VERSION 5.8 ;
BUSBITCHARS "[]" ;
DIVIDERCHAR "/" ;
UNITS
    DATABASE MICRONS 1000 ;
END UNITS

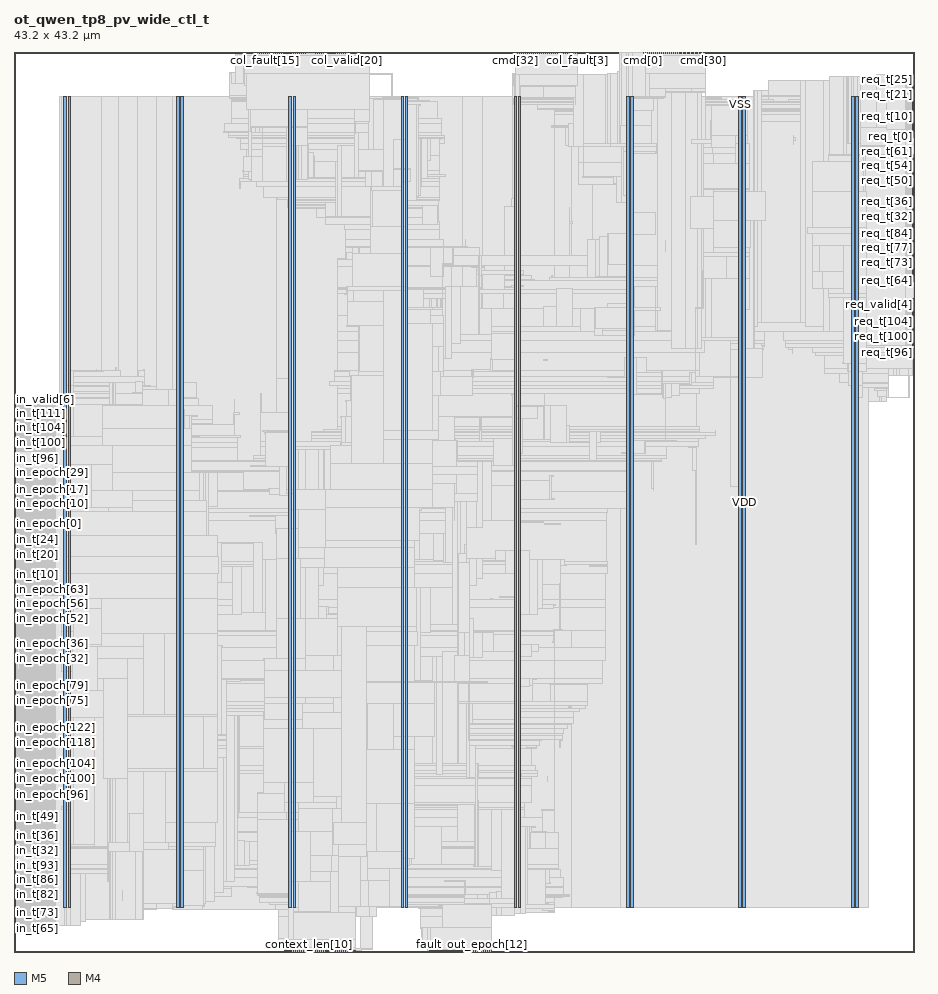
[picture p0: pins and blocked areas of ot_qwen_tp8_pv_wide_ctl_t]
MACRO ot_qwen_tp8_pv_wide_ctl_t
  FOREIGN ot_qwen_tp8_pv_wide_ctl_t 0 0 ;
  CLASS BLOCK ;
  SIZE 43.2 BY 43.2 ;
  PIN busy
    DIRECTION OUTPUT ;
    USE SIGNAL ;
    PORT
      LAYER M5 ;
        RECT  13.008 0 13.032 0.084 ;
    END
  END busy
  PIN clk
    DIRECTION INPUT ;
    USE SIGNAL ;
    PORT
      LAYER M5 ;
        RECT  13.104 0 13.128 0.084 ;
    END
  END clk
  PIN cmd[0]
    DIRECTION OUTPUT ;
    USE SIGNAL ;
    PORT
      LAYER M5 ;
        RECT  30.192 43.116 30.216 43.2 ;
    END
  END cmd[0]
  PIN cmd[10]
    DIRECTION OUTPUT ;
    USE SIGNAL ;
    PORT
      LAYER M5 ;
        RECT  31.152 43.116 31.176 43.2 ;
    END
  END cmd[10]
  PIN cmd[11]
    DIRECTION OUTPUT ;
    USE SIGNAL ;
    PORT
      LAYER M5 ;
        RECT  31.248 43.116 31.272 43.2 ;
    END
  END cmd[11]
  PIN cmd[12]
    DIRECTION OUTPUT ;
    USE SIGNAL ;
    PORT
      LAYER M5 ;
        RECT  31.344 43.116 31.368 43.2 ;
    END
  END cmd[12]
  PIN cmd[13]
    DIRECTION OUTPUT ;
    USE SIGNAL ;
    PORT
      LAYER M5 ;
        RECT  31.44 43.116 31.464 43.2 ;
    END
  END cmd[13]
  PIN cmd[14]
    DIRECTION OUTPUT ;
    USE SIGNAL ;
    PORT
      LAYER M5 ;
        RECT  31.536 43.116 31.56 43.2 ;
    END
  END cmd[14]
  PIN cmd[15]
    DIRECTION OUTPUT ;
    USE SIGNAL ;
    PORT
      LAYER M5 ;
        RECT  31.632 43.116 31.656 43.2 ;
    END
  END cmd[15]
  PIN cmd[16]
    DIRECTION OUTPUT ;
    USE SIGNAL ;
    PORT
      LAYER M5 ;
        RECT  31.728 43.116 31.752 43.2 ;
    END
  END cmd[16]
  PIN cmd[17]
    DIRECTION OUTPUT ;
    USE SIGNAL ;
    PORT
      LAYER M5 ;
        RECT  31.824 43.116 31.848 43.2 ;
    END
  END cmd[17]
  PIN cmd[18]
    DIRECTION OUTPUT ;
    USE SIGNAL ;
    PORT
      LAYER M5 ;
        RECT  31.92 43.116 31.944 43.2 ;
    END
  END cmd[18]
  PIN cmd[19]
    DIRECTION OUTPUT ;
    USE SIGNAL ;
    PORT
      LAYER M5 ;
        RECT  32.016 43.116 32.04 43.2 ;
    END
  END cmd[19]
  PIN cmd[1]
    DIRECTION OUTPUT ;
    USE SIGNAL ;
    PORT
      LAYER M5 ;
        RECT  30.288 43.116 30.312 43.2 ;
    END
  END cmd[1]
  PIN cmd[20]
    DIRECTION OUTPUT ;
    USE SIGNAL ;
    PORT
      LAYER M5 ;
        RECT  32.112 43.116 32.136 43.2 ;
    END
  END cmd[20]
  PIN cmd[21]
    DIRECTION OUTPUT ;
    USE SIGNAL ;
    PORT
      LAYER M5 ;
        RECT  32.208 43.116 32.232 43.2 ;
    END
  END cmd[21]
  PIN cmd[22]
    DIRECTION OUTPUT ;
    USE SIGNAL ;
    PORT
      LAYER M5 ;
        RECT  32.304 43.116 32.328 43.2 ;
    END
  END cmd[22]
  PIN cmd[23]
    DIRECTION OUTPUT ;
    USE SIGNAL ;
    PORT
      LAYER M5 ;
        RECT  32.4 43.116 32.424 43.2 ;
    END
  END cmd[23]
  PIN cmd[24]
    DIRECTION OUTPUT ;
    USE SIGNAL ;
    PORT
      LAYER M5 ;
        RECT  32.496 43.116 32.52 43.2 ;
    END
  END cmd[24]
  PIN cmd[25]
    DIRECTION OUTPUT ;
    USE SIGNAL ;
    PORT
      LAYER M5 ;
        RECT  32.592 43.116 32.616 43.2 ;
    END
  END cmd[25]
  PIN cmd[26]
    DIRECTION OUTPUT ;
    USE SIGNAL ;
    PORT
      LAYER M5 ;
        RECT  32.688 43.116 32.712 43.2 ;
    END
  END cmd[26]
  PIN cmd[27]
    DIRECTION OUTPUT ;
    USE SIGNAL ;
    PORT
      LAYER M5 ;
        RECT  32.784 43.116 32.808 43.2 ;
    END
  END cmd[27]
  PIN cmd[28]
    DIRECTION OUTPUT ;
    USE SIGNAL ;
    PORT
      LAYER M5 ;
        RECT  32.88 43.116 32.904 43.2 ;
    END
  END cmd[28]
  PIN cmd[29]
    DIRECTION OUTPUT ;
    USE SIGNAL ;
    PORT
      LAYER M5 ;
        RECT  32.976 43.116 33 43.2 ;
    END
  END cmd[29]
  PIN cmd[2]
    DIRECTION OUTPUT ;
    USE SIGNAL ;
    PORT
      LAYER M5 ;
        RECT  30.384 43.116 30.408 43.2 ;
    END
  END cmd[2]
  PIN cmd[30]
    DIRECTION OUTPUT ;
    USE SIGNAL ;
    PORT
      LAYER M5 ;
        RECT  33.072 43.116 33.096 43.2 ;
    END
  END cmd[30]
  PIN cmd[31]
    DIRECTION OUTPUT ;
    USE SIGNAL ;
    PORT
      LAYER M5 ;
        RECT  33.168 43.116 33.192 43.2 ;
    END
  END cmd[31]
  PIN cmd[32]
    DIRECTION OUTPUT ;
    USE SIGNAL ;
    PORT
      LAYER M5 ;
        RECT  24.048 43.116 24.072 43.2 ;
    END
  END cmd[32]
  PIN cmd[33]
    DIRECTION OUTPUT ;
    USE SIGNAL ;
    PORT
      LAYER M5 ;
        RECT  24.144 43.116 24.168 43.2 ;
    END
  END cmd[33]
  PIN cmd[34]
    DIRECTION OUTPUT ;
    USE SIGNAL ;
    PORT
      LAYER M5 ;
        RECT  24.24 43.116 24.264 43.2 ;
    END
  END cmd[34]
  PIN cmd[35]
    DIRECTION OUTPUT ;
    USE SIGNAL ;
    PORT
      LAYER M5 ;
        RECT  24.336 43.116 24.36 43.2 ;
    END
  END cmd[35]
  PIN cmd[36]
    DIRECTION OUTPUT ;
    USE SIGNAL ;
    PORT
      LAYER M5 ;
        RECT  24.432 43.116 24.456 43.2 ;
    END
  END cmd[36]
  PIN cmd[37]
    DIRECTION OUTPUT ;
    USE SIGNAL ;
    PORT
      LAYER M5 ;
        RECT  24.528 43.116 24.552 43.2 ;
    END
  END cmd[37]
  PIN cmd[38]
    DIRECTION OUTPUT ;
    USE SIGNAL ;
    PORT
      LAYER M5 ;
        RECT  24.624 43.116 24.648 43.2 ;
    END
  END cmd[38]
  PIN cmd[39]
    DIRECTION OUTPUT ;
    USE SIGNAL ;
    PORT
      LAYER M5 ;
        RECT  24.72 43.116 24.744 43.2 ;
    END
  END cmd[39]
  PIN cmd[3]
    DIRECTION OUTPUT ;
    USE SIGNAL ;
    PORT
      LAYER M5 ;
        RECT  30.48 43.116 30.504 43.2 ;
    END
  END cmd[3]
  PIN cmd[40]
    DIRECTION OUTPUT ;
    USE SIGNAL ;
    PORT
      LAYER M5 ;
        RECT  24.816 43.116 24.84 43.2 ;
    END
  END cmd[40]
  PIN cmd[41]
    DIRECTION OUTPUT ;
    USE SIGNAL ;
    PORT
      LAYER M5 ;
        RECT  24.912 43.116 24.936 43.2 ;
    END
  END cmd[41]
  PIN cmd[42]
    DIRECTION OUTPUT ;
    USE SIGNAL ;
    PORT
      LAYER M5 ;
        RECT  25.008 43.116 25.032 43.2 ;
    END
  END cmd[42]
  PIN cmd[43]
    DIRECTION OUTPUT ;
    USE SIGNAL ;
    PORT
      LAYER M5 ;
        RECT  25.104 43.116 25.128 43.2 ;
    END
  END cmd[43]
  PIN cmd[44]
    DIRECTION OUTPUT ;
    USE SIGNAL ;
    PORT
      LAYER M5 ;
        RECT  25.2 43.116 25.224 43.2 ;
    END
  END cmd[44]
  PIN cmd[45]
    DIRECTION OUTPUT ;
    USE SIGNAL ;
    PORT
      LAYER M5 ;
        RECT  25.296 43.116 25.32 43.2 ;
    END
  END cmd[45]
  PIN cmd[46]
    DIRECTION OUTPUT ;
    USE SIGNAL ;
    PORT
      LAYER M5 ;
        RECT  25.392 43.116 25.416 43.2 ;
    END
  END cmd[46]
  PIN cmd[47]
    DIRECTION OUTPUT ;
    USE SIGNAL ;
    PORT
      LAYER M5 ;
        RECT  25.488 43.116 25.512 43.2 ;
    END
  END cmd[47]
  PIN cmd[48]
    DIRECTION OUTPUT ;
    USE SIGNAL ;
    PORT
      LAYER M5 ;
        RECT  25.584 43.116 25.608 43.2 ;
    END
  END cmd[48]
  PIN cmd[49]
    DIRECTION OUTPUT ;
    USE SIGNAL ;
    PORT
      LAYER M5 ;
        RECT  25.68 43.116 25.704 43.2 ;
    END
  END cmd[49]
  PIN cmd[4]
    DIRECTION OUTPUT ;
    USE SIGNAL ;
    PORT
      LAYER M5 ;
        RECT  30.576 43.116 30.6 43.2 ;
    END
  END cmd[4]
  PIN cmd[50]
    DIRECTION OUTPUT ;
    USE SIGNAL ;
    PORT
      LAYER M5 ;
        RECT  25.776 43.116 25.8 43.2 ;
    END
  END cmd[50]
  PIN cmd[51]
    DIRECTION OUTPUT ;
    USE SIGNAL ;
    PORT
      LAYER M5 ;
        RECT  25.872 43.116 25.896 43.2 ;
    END
  END cmd[51]
  PIN cmd[52]
    DIRECTION OUTPUT ;
    USE SIGNAL ;
    PORT
      LAYER M5 ;
        RECT  25.968 43.116 25.992 43.2 ;
    END
  END cmd[52]
  PIN cmd[53]
    DIRECTION OUTPUT ;
    USE SIGNAL ;
    PORT
      LAYER M5 ;
        RECT  26.064 43.116 26.088 43.2 ;
    END
  END cmd[53]
  PIN cmd[54]
    DIRECTION OUTPUT ;
    USE SIGNAL ;
    PORT
      LAYER M5 ;
        RECT  26.16 43.116 26.184 43.2 ;
    END
  END cmd[54]
  PIN cmd[55]
    DIRECTION OUTPUT ;
    USE SIGNAL ;
    PORT
      LAYER M5 ;
        RECT  26.256 43.116 26.28 43.2 ;
    END
  END cmd[55]
  PIN cmd[56]
    DIRECTION OUTPUT ;
    USE SIGNAL ;
    PORT
      LAYER M5 ;
        RECT  26.352 43.116 26.376 43.2 ;
    END
  END cmd[56]
  PIN cmd[57]
    DIRECTION OUTPUT ;
    USE SIGNAL ;
    PORT
      LAYER M5 ;
        RECT  26.448 43.116 26.472 43.2 ;
    END
  END cmd[57]
  PIN cmd[58]
    DIRECTION OUTPUT ;
    USE SIGNAL ;
    PORT
      LAYER M5 ;
        RECT  26.544 43.116 26.568 43.2 ;
    END
  END cmd[58]
  PIN cmd[59]
    DIRECTION OUTPUT ;
    USE SIGNAL ;
    PORT
      LAYER M5 ;
        RECT  26.64 43.116 26.664 43.2 ;
    END
  END cmd[59]
  PIN cmd[5]
    DIRECTION OUTPUT ;
    USE SIGNAL ;
    PORT
      LAYER M5 ;
        RECT  30.672 43.116 30.696 43.2 ;
    END
  END cmd[5]
  PIN cmd[6]
    DIRECTION OUTPUT ;
    USE SIGNAL ;
    PORT
      LAYER M5 ;
        RECT  30.768 43.116 30.792 43.2 ;
    END
  END cmd[6]
  PIN cmd[7]
    DIRECTION OUTPUT ;
    USE SIGNAL ;
    PORT
      LAYER M5 ;
        RECT  30.864 43.116 30.888 43.2 ;
    END
  END cmd[7]
  PIN cmd[8]
    DIRECTION OUTPUT ;
    USE SIGNAL ;
    PORT
      LAYER M5 ;
        RECT  30.96 43.116 30.984 43.2 ;
    END
  END cmd[8]
  PIN cmd[9]
    DIRECTION OUTPUT ;
    USE SIGNAL ;
    PORT
      LAYER M5 ;
        RECT  31.056 43.116 31.08 43.2 ;
    END
  END cmd[9]
  PIN col_fault[0]
    DIRECTION INPUT ;
    USE SIGNAL ;
    PORT
      LAYER M5 ;
        RECT  26.736 43.116 26.76 43.2 ;
    END
  END col_fault[0]
  PIN col_fault[10]
    DIRECTION INPUT ;
    USE SIGNAL ;
    PORT
      LAYER M5 ;
        RECT  11.568 43.116 11.592 43.2 ;
    END
  END col_fault[10]
  PIN col_fault[11]
    DIRECTION INPUT ;
    USE SIGNAL ;
    PORT
      LAYER M5 ;
        RECT  11.664 43.116 11.688 43.2 ;
    END
  END col_fault[11]
  PIN col_fault[12]
    DIRECTION INPUT ;
    USE SIGNAL ;
    PORT
      LAYER M5 ;
        RECT  11.76 43.116 11.784 43.2 ;
    END
  END col_fault[12]
  PIN col_fault[13]
    DIRECTION INPUT ;
    USE SIGNAL ;
    PORT
      LAYER M5 ;
        RECT  11.856 43.116 11.88 43.2 ;
    END
  END col_fault[13]
  PIN col_fault[14]
    DIRECTION INPUT ;
    USE SIGNAL ;
    PORT
      LAYER M5 ;
        RECT  11.952 43.116 11.976 43.2 ;
    END
  END col_fault[14]
  PIN col_fault[15]
    DIRECTION INPUT ;
    USE SIGNAL ;
    PORT
      LAYER M5 ;
        RECT  12.048 43.116 12.072 43.2 ;
    END
  END col_fault[15]
  PIN col_fault[16]
    DIRECTION INPUT ;
    USE SIGNAL ;
    PORT
      LAYER M5 ;
        RECT  12.144 43.116 12.168 43.2 ;
    END
  END col_fault[16]
  PIN col_fault[17]
    DIRECTION INPUT ;
    USE SIGNAL ;
    PORT
      LAYER M5 ;
        RECT  12.24 43.116 12.264 43.2 ;
    END
  END col_fault[17]
  PIN col_fault[18]
    DIRECTION INPUT ;
    USE SIGNAL ;
    PORT
      LAYER M5 ;
        RECT  12.336 43.116 12.36 43.2 ;
    END
  END col_fault[18]
  PIN col_fault[19]
    DIRECTION INPUT ;
    USE SIGNAL ;
    PORT
      LAYER M5 ;
        RECT  12.432 43.116 12.456 43.2 ;
    END
  END col_fault[19]
  PIN col_fault[1]
    DIRECTION INPUT ;
    USE SIGNAL ;
    PORT
      LAYER M5 ;
        RECT  26.832 43.116 26.856 43.2 ;
    END
  END col_fault[1]
  PIN col_fault[20]
    DIRECTION INPUT ;
    USE SIGNAL ;
    PORT
      LAYER M5 ;
        RECT  12.528 43.116 12.552 43.2 ;
    END
  END col_fault[20]
  PIN col_fault[21]
    DIRECTION INPUT ;
    USE SIGNAL ;
    PORT
      LAYER M5 ;
        RECT  12.624 43.116 12.648 43.2 ;
    END
  END col_fault[21]
  PIN col_fault[22]
    DIRECTION INPUT ;
    USE SIGNAL ;
    PORT
      LAYER M5 ;
        RECT  12.72 43.116 12.744 43.2 ;
    END
  END col_fault[22]
  PIN col_fault[23]
    DIRECTION INPUT ;
    USE SIGNAL ;
    PORT
      LAYER M5 ;
        RECT  12.816 43.116 12.84 43.2 ;
    END
  END col_fault[23]
  PIN col_fault[24]
    DIRECTION INPUT ;
    USE SIGNAL ;
    PORT
      LAYER M5 ;
        RECT  12.912 43.116 12.936 43.2 ;
    END
  END col_fault[24]
  PIN col_fault[25]
    DIRECTION INPUT ;
    USE SIGNAL ;
    PORT
      LAYER M5 ;
        RECT  13.008 43.116 13.032 43.2 ;
    END
  END col_fault[25]
  PIN col_fault[26]
    DIRECTION INPUT ;
    USE SIGNAL ;
    PORT
      LAYER M5 ;
        RECT  13.104 43.116 13.128 43.2 ;
    END
  END col_fault[26]
  PIN col_fault[27]
    DIRECTION INPUT ;
    USE SIGNAL ;
    PORT
      LAYER M5 ;
        RECT  13.2 43.116 13.224 43.2 ;
    END
  END col_fault[27]
  PIN col_fault[28]
    DIRECTION INPUT ;
    USE SIGNAL ;
    PORT
      LAYER M5 ;
        RECT  13.296 43.116 13.32 43.2 ;
    END
  END col_fault[28]
  PIN col_fault[29]
    DIRECTION INPUT ;
    USE SIGNAL ;
    PORT
      LAYER M5 ;
        RECT  13.392 43.116 13.416 43.2 ;
    END
  END col_fault[29]
  PIN col_fault[2]
    DIRECTION INPUT ;
    USE SIGNAL ;
    PORT
      LAYER M5 ;
        RECT  26.928 43.116 26.952 43.2 ;
    END
  END col_fault[2]
  PIN col_fault[30]
    DIRECTION INPUT ;
    USE SIGNAL ;
    PORT
      LAYER M5 ;
        RECT  13.488 43.116 13.512 43.2 ;
    END
  END col_fault[30]
  PIN col_fault[31]
    DIRECTION INPUT ;
    USE SIGNAL ;
    PORT
      LAYER M5 ;
        RECT  13.584 43.116 13.608 43.2 ;
    END
  END col_fault[31]
  PIN col_fault[3]
    DIRECTION INPUT ;
    USE SIGNAL ;
    PORT
      LAYER M5 ;
        RECT  27.024 43.116 27.048 43.2 ;
    END
  END col_fault[3]
  PIN col_fault[4]
    DIRECTION INPUT ;
    USE SIGNAL ;
    PORT
      LAYER M5 ;
        RECT  10.992 43.116 11.016 43.2 ;
    END
  END col_fault[4]
  PIN col_fault[5]
    DIRECTION INPUT ;
    USE SIGNAL ;
    PORT
      LAYER M5 ;
        RECT  11.088 43.116 11.112 43.2 ;
    END
  END col_fault[5]
  PIN col_fault[6]
    DIRECTION INPUT ;
    USE SIGNAL ;
    PORT
      LAYER M5 ;
        RECT  11.184 43.116 11.208 43.2 ;
    END
  END col_fault[6]
  PIN col_fault[7]
    DIRECTION INPUT ;
    USE SIGNAL ;
    PORT
      LAYER M5 ;
        RECT  11.28 43.116 11.304 43.2 ;
    END
  END col_fault[7]
  PIN col_fault[8]
    DIRECTION INPUT ;
    USE SIGNAL ;
    PORT
      LAYER M5 ;
        RECT  11.376 43.116 11.4 43.2 ;
    END
  END col_fault[8]
  PIN col_fault[9]
    DIRECTION INPUT ;
    USE SIGNAL ;
    PORT
      LAYER M5 ;
        RECT  11.472 43.116 11.496 43.2 ;
    END
  END col_fault[9]
  PIN col_valid[0]
    DIRECTION INPUT ;
    USE SIGNAL ;
    PORT
      LAYER M5 ;
        RECT  13.68 43.116 13.704 43.2 ;
    END
  END col_valid[0]
  PIN col_valid[10]
    DIRECTION INPUT ;
    USE SIGNAL ;
    PORT
      LAYER M5 ;
        RECT  15.024 43.116 15.048 43.2 ;
    END
  END col_valid[10]
  PIN col_valid[11]
    DIRECTION INPUT ;
    USE SIGNAL ;
    PORT
      LAYER M5 ;
        RECT  15.12 43.116 15.144 43.2 ;
    END
  END col_valid[11]
  PIN col_valid[12]
    DIRECTION INPUT ;
    USE SIGNAL ;
    PORT
      LAYER M5 ;
        RECT  15.216 43.116 15.24 43.2 ;
    END
  END col_valid[12]
  PIN col_valid[13]
    DIRECTION INPUT ;
    USE SIGNAL ;
    PORT
      LAYER M5 ;
        RECT  15.312 43.116 15.336 43.2 ;
    END
  END col_valid[13]
  PIN col_valid[14]
    DIRECTION INPUT ;
    USE SIGNAL ;
    PORT
      LAYER M5 ;
        RECT  15.408 43.116 15.432 43.2 ;
    END
  END col_valid[14]
  PIN col_valid[15]
    DIRECTION INPUT ;
    USE SIGNAL ;
    PORT
      LAYER M5 ;
        RECT  15.504 43.116 15.528 43.2 ;
    END
  END col_valid[15]
  PIN col_valid[16]
    DIRECTION INPUT ;
    USE SIGNAL ;
    PORT
      LAYER M5 ;
        RECT  15.6 43.116 15.624 43.2 ;
    END
  END col_valid[16]
  PIN col_valid[17]
    DIRECTION INPUT ;
    USE SIGNAL ;
    PORT
      LAYER M5 ;
        RECT  15.696 43.116 15.72 43.2 ;
    END
  END col_valid[17]
  PIN col_valid[18]
    DIRECTION INPUT ;
    USE SIGNAL ;
    PORT
      LAYER M5 ;
        RECT  15.792 43.116 15.816 43.2 ;
    END
  END col_valid[18]
  PIN col_valid[19]
    DIRECTION INPUT ;
    USE SIGNAL ;
    PORT
      LAYER M5 ;
        RECT  15.888 43.116 15.912 43.2 ;
    END
  END col_valid[19]
  PIN col_valid[1]
    DIRECTION INPUT ;
    USE SIGNAL ;
    PORT
      LAYER M5 ;
        RECT  13.776 43.116 13.8 43.2 ;
    END
  END col_valid[1]
  PIN col_valid[20]
    DIRECTION INPUT ;
    USE SIGNAL ;
    PORT
      LAYER M5 ;
        RECT  15.984 43.116 16.008 43.2 ;
    END
  END col_valid[20]
  PIN col_valid[21]
    DIRECTION INPUT ;
    USE SIGNAL ;
    PORT
      LAYER M5 ;
        RECT  16.08 43.116 16.104 43.2 ;
    END
  END col_valid[21]
  PIN col_valid[22]
    DIRECTION INPUT ;
    USE SIGNAL ;
    PORT
      LAYER M5 ;
        RECT  16.176 43.116 16.2 43.2 ;
    END
  END col_valid[22]
  PIN col_valid[23]
    DIRECTION INPUT ;
    USE SIGNAL ;
    PORT
      LAYER M5 ;
        RECT  16.272 43.116 16.296 43.2 ;
    END
  END col_valid[23]
  PIN col_valid[24]
    DIRECTION INPUT ;
    USE SIGNAL ;
    PORT
      LAYER M5 ;
        RECT  16.368 43.116 16.392 43.2 ;
    END
  END col_valid[24]
  PIN col_valid[25]
    DIRECTION INPUT ;
    USE SIGNAL ;
    PORT
      LAYER M5 ;
        RECT  16.464 43.116 16.488 43.2 ;
    END
  END col_valid[25]
  PIN col_valid[26]
    DIRECTION INPUT ;
    USE SIGNAL ;
    PORT
      LAYER M5 ;
        RECT  16.56 43.116 16.584 43.2 ;
    END
  END col_valid[26]
  PIN col_valid[27]
    DIRECTION INPUT ;
    USE SIGNAL ;
    PORT
      LAYER M5 ;
        RECT  16.656 43.116 16.68 43.2 ;
    END
  END col_valid[27]
  PIN col_valid[28]
    DIRECTION INPUT ;
    USE SIGNAL ;
    PORT
      LAYER M5 ;
        RECT  16.752 43.116 16.776 43.2 ;
    END
  END col_valid[28]
  PIN col_valid[29]
    DIRECTION INPUT ;
    USE SIGNAL ;
    PORT
      LAYER M5 ;
        RECT  16.848 43.116 16.872 43.2 ;
    END
  END col_valid[29]
  PIN col_valid[2]
    DIRECTION INPUT ;
    USE SIGNAL ;
    PORT
      LAYER M5 ;
        RECT  13.872 43.116 13.896 43.2 ;
    END
  END col_valid[2]
  PIN col_valid[30]
    DIRECTION INPUT ;
    USE SIGNAL ;
    PORT
      LAYER M5 ;
        RECT  16.944 43.116 16.968 43.2 ;
    END
  END col_valid[30]
  PIN col_valid[31]
    DIRECTION INPUT ;
    USE SIGNAL ;
    PORT
      LAYER M5 ;
        RECT  17.04 43.116 17.064 43.2 ;
    END
  END col_valid[31]
  PIN col_valid[3]
    DIRECTION INPUT ;
    USE SIGNAL ;
    PORT
      LAYER M5 ;
        RECT  13.968 43.116 13.992 43.2 ;
    END
  END col_valid[3]
  PIN col_valid[4]
    DIRECTION INPUT ;
    USE SIGNAL ;
    PORT
      LAYER M5 ;
        RECT  14.448 43.116 14.472 43.2 ;
    END
  END col_valid[4]
  PIN col_valid[5]
    DIRECTION INPUT ;
    USE SIGNAL ;
    PORT
      LAYER M5 ;
        RECT  14.544 43.116 14.568 43.2 ;
    END
  END col_valid[5]
  PIN col_valid[6]
    DIRECTION INPUT ;
    USE SIGNAL ;
    PORT
      LAYER M5 ;
        RECT  14.64 43.116 14.664 43.2 ;
    END
  END col_valid[6]
  PIN col_valid[7]
    DIRECTION INPUT ;
    USE SIGNAL ;
    PORT
      LAYER M5 ;
        RECT  14.736 43.116 14.76 43.2 ;
    END
  END col_valid[7]
  PIN col_valid[8]
    DIRECTION INPUT ;
    USE SIGNAL ;
    PORT
      LAYER M5 ;
        RECT  14.832 43.116 14.856 43.2 ;
    END
  END col_valid[8]
  PIN col_valid[9]
    DIRECTION INPUT ;
    USE SIGNAL ;
    PORT
      LAYER M5 ;
        RECT  14.928 43.116 14.952 43.2 ;
    END
  END col_valid[9]
  PIN context_len[0]
    DIRECTION INPUT ;
    USE SIGNAL ;
    PORT
      LAYER M5 ;
        RECT  13.2 0 13.224 0.084 ;
    END
  END context_len[0]
  PIN context_len[10]
    DIRECTION INPUT ;
    USE SIGNAL ;
    PORT
      LAYER M5 ;
        RECT  14.16 0 14.184 0.084 ;
    END
  END context_len[10]
  PIN context_len[11]
    DIRECTION INPUT ;
    USE SIGNAL ;
    PORT
      LAYER M5 ;
        RECT  14.256 0 14.28 0.084 ;
    END
  END context_len[11]
  PIN context_len[12]
    DIRECTION INPUT ;
    USE SIGNAL ;
    PORT
      LAYER M5 ;
        RECT  14.352 0 14.376 0.084 ;
    END
  END context_len[12]
  PIN context_len[13]
    DIRECTION INPUT ;
    USE SIGNAL ;
    PORT
      LAYER M5 ;
        RECT  14.448 0 14.472 0.084 ;
    END
  END context_len[13]
  PIN context_len[1]
    DIRECTION INPUT ;
    USE SIGNAL ;
    PORT
      LAYER M5 ;
        RECT  13.296 0 13.32 0.084 ;
    END
  END context_len[1]
  PIN context_len[2]
    DIRECTION INPUT ;
    USE SIGNAL ;
    PORT
      LAYER M5 ;
        RECT  13.392 0 13.416 0.084 ;
    END
  END context_len[2]
  PIN context_len[3]
    DIRECTION INPUT ;
    USE SIGNAL ;
    PORT
      LAYER M5 ;
        RECT  13.488 0 13.512 0.084 ;
    END
  END context_len[3]
  PIN context_len[4]
    DIRECTION INPUT ;
    USE SIGNAL ;
    PORT
      LAYER M5 ;
        RECT  13.584 0 13.608 0.084 ;
    END
  END context_len[4]
  PIN context_len[5]
    DIRECTION INPUT ;
    USE SIGNAL ;
    PORT
      LAYER M5 ;
        RECT  13.68 0 13.704 0.084 ;
    END
  END context_len[5]
  PIN context_len[6]
    DIRECTION INPUT ;
    USE SIGNAL ;
    PORT
      LAYER M5 ;
        RECT  13.776 0 13.8 0.084 ;
    END
  END context_len[6]
  PIN context_len[7]
    DIRECTION INPUT ;
    USE SIGNAL ;
    PORT
      LAYER M5 ;
        RECT  13.872 0 13.896 0.084 ;
    END
  END context_len[7]
  PIN context_len[8]
    DIRECTION INPUT ;
    USE SIGNAL ;
    PORT
      LAYER M5 ;
        RECT  13.968 0 13.992 0.084 ;
    END
  END context_len[8]
  PIN context_len[9]
    DIRECTION INPUT ;
    USE SIGNAL ;
    PORT
      LAYER M5 ;
        RECT  14.064 0 14.088 0.084 ;
    END
  END context_len[9]
  PIN epoch[0]
    DIRECTION INPUT ;
    USE SIGNAL ;
    PORT
      LAYER M5 ;
        RECT  14.544 0 14.568 0.084 ;
    END
  END epoch[0]
  PIN epoch[10]
    DIRECTION INPUT ;
    USE SIGNAL ;
    PORT
      LAYER M5 ;
        RECT  15.504 0 15.528 0.084 ;
    END
  END epoch[10]
  PIN epoch[11]
    DIRECTION INPUT ;
    USE SIGNAL ;
    PORT
      LAYER M5 ;
        RECT  15.6 0 15.624 0.084 ;
    END
  END epoch[11]
  PIN epoch[12]
    DIRECTION INPUT ;
    USE SIGNAL ;
    PORT
      LAYER M5 ;
        RECT  15.696 0 15.72 0.084 ;
    END
  END epoch[12]
  PIN epoch[13]
    DIRECTION INPUT ;
    USE SIGNAL ;
    PORT
      LAYER M5 ;
        RECT  15.792 0 15.816 0.084 ;
    END
  END epoch[13]
  PIN epoch[14]
    DIRECTION INPUT ;
    USE SIGNAL ;
    PORT
      LAYER M5 ;
        RECT  15.888 0 15.912 0.084 ;
    END
  END epoch[14]
  PIN epoch[15]
    DIRECTION INPUT ;
    USE SIGNAL ;
    PORT
      LAYER M5 ;
        RECT  15.984 0 16.008 0.084 ;
    END
  END epoch[15]
  PIN epoch[1]
    DIRECTION INPUT ;
    USE SIGNAL ;
    PORT
      LAYER M5 ;
        RECT  14.64 0 14.664 0.084 ;
    END
  END epoch[1]
  PIN epoch[2]
    DIRECTION INPUT ;
    USE SIGNAL ;
    PORT
      LAYER M5 ;
        RECT  14.736 0 14.76 0.084 ;
    END
  END epoch[2]
  PIN epoch[3]
    DIRECTION INPUT ;
    USE SIGNAL ;
    PORT
      LAYER M5 ;
        RECT  14.832 0 14.856 0.084 ;
    END
  END epoch[3]
  PIN epoch[4]
    DIRECTION INPUT ;
    USE SIGNAL ;
    PORT
      LAYER M5 ;
        RECT  14.928 0 14.952 0.084 ;
    END
  END epoch[4]
  PIN epoch[5]
    DIRECTION INPUT ;
    USE SIGNAL ;
    PORT
      LAYER M5 ;
        RECT  15.024 0 15.048 0.084 ;
    END
  END epoch[5]
  PIN epoch[6]
    DIRECTION INPUT ;
    USE SIGNAL ;
    PORT
      LAYER M5 ;
        RECT  15.12 0 15.144 0.084 ;
    END
  END epoch[6]
  PIN epoch[7]
    DIRECTION INPUT ;
    USE SIGNAL ;
    PORT
      LAYER M5 ;
        RECT  15.216 0 15.24 0.084 ;
    END
  END epoch[7]
  PIN epoch[8]
    DIRECTION INPUT ;
    USE SIGNAL ;
    PORT
      LAYER M5 ;
        RECT  15.312 0 15.336 0.084 ;
    END
  END epoch[8]
  PIN epoch[9]
    DIRECTION INPUT ;
    USE SIGNAL ;
    PORT
      LAYER M5 ;
        RECT  15.408 0 15.432 0.084 ;
    END
  END epoch[9]
  PIN fault
    DIRECTION OUTPUT ;
    USE SIGNAL ;
    PORT
      LAYER M5 ;
        RECT  19.92 0 19.944 0.084 ;
    END
  END fault
  PIN in_epoch[0]
    DIRECTION INPUT ;
    USE SIGNAL ;
    PORT
      LAYER M4 ;
        RECT  0 20.208 0.084 20.232 ;
    END
  END in_epoch[0]
  PIN in_epoch[100]
    DIRECTION INPUT ;
    USE SIGNAL ;
    PORT
      LAYER M4 ;
        RECT  0 8.304 0.084 8.328 ;
    END
  END in_epoch[100]
  PIN in_epoch[101]
    DIRECTION INPUT ;
    USE SIGNAL ;
    PORT
      LAYER M4 ;
        RECT  0 8.4 0.084 8.424 ;
    END
  END in_epoch[101]
  PIN in_epoch[102]
    DIRECTION INPUT ;
    USE SIGNAL ;
    PORT
      LAYER M4 ;
        RECT  0 8.496 0.084 8.52 ;
    END
  END in_epoch[102]
  PIN in_epoch[103]
    DIRECTION INPUT ;
    USE SIGNAL ;
    PORT
      LAYER M4 ;
        RECT  0 8.592 0.084 8.616 ;
    END
  END in_epoch[103]
  PIN in_epoch[104]
    DIRECTION INPUT ;
    USE SIGNAL ;
    PORT
      LAYER M4 ;
        RECT  0 8.688 0.084 8.712 ;
    END
  END in_epoch[104]
  PIN in_epoch[105]
    DIRECTION INPUT ;
    USE SIGNAL ;
    PORT
      LAYER M4 ;
        RECT  0 8.784 0.084 8.808 ;
    END
  END in_epoch[105]
  PIN in_epoch[106]
    DIRECTION INPUT ;
    USE SIGNAL ;
    PORT
      LAYER M4 ;
        RECT  0 8.88 0.084 8.904 ;
    END
  END in_epoch[106]
  PIN in_epoch[107]
    DIRECTION INPUT ;
    USE SIGNAL ;
    PORT
      LAYER M4 ;
        RECT  0 8.976 0.084 9 ;
    END
  END in_epoch[107]
  PIN in_epoch[108]
    DIRECTION INPUT ;
    USE SIGNAL ;
    PORT
      LAYER M4 ;
        RECT  0 9.072 0.084 9.096 ;
    END
  END in_epoch[108]
  PIN in_epoch[109]
    DIRECTION INPUT ;
    USE SIGNAL ;
    PORT
      LAYER M4 ;
        RECT  0 9.168 0.084 9.192 ;
    END
  END in_epoch[109]
  PIN in_epoch[10]
    DIRECTION INPUT ;
    USE SIGNAL ;
    PORT
      LAYER M4 ;
        RECT  0 21.168 0.084 21.192 ;
    END
  END in_epoch[10]
  PIN in_epoch[110]
    DIRECTION INPUT ;
    USE SIGNAL ;
    PORT
      LAYER M4 ;
        RECT  0 9.264 0.084 9.288 ;
    END
  END in_epoch[110]
  PIN in_epoch[111]
    DIRECTION INPUT ;
    USE SIGNAL ;
    PORT
      LAYER M4 ;
        RECT  0 9.36 0.084 9.384 ;
    END
  END in_epoch[111]
  PIN in_epoch[112]
    DIRECTION INPUT ;
    USE SIGNAL ;
    PORT
      LAYER M4 ;
        RECT  0 9.456 0.084 9.48 ;
    END
  END in_epoch[112]
  PIN in_epoch[113]
    DIRECTION INPUT ;
    USE SIGNAL ;
    PORT
      LAYER M4 ;
        RECT  0 9.552 0.084 9.576 ;
    END
  END in_epoch[113]
  PIN in_epoch[114]
    DIRECTION INPUT ;
    USE SIGNAL ;
    PORT
      LAYER M4 ;
        RECT  0 9.648 0.084 9.672 ;
    END
  END in_epoch[114]
  PIN in_epoch[115]
    DIRECTION INPUT ;
    USE SIGNAL ;
    PORT
      LAYER M4 ;
        RECT  0 9.744 0.084 9.768 ;
    END
  END in_epoch[115]
  PIN in_epoch[116]
    DIRECTION INPUT ;
    USE SIGNAL ;
    PORT
      LAYER M4 ;
        RECT  0 9.84 0.084 9.864 ;
    END
  END in_epoch[116]
  PIN in_epoch[117]
    DIRECTION INPUT ;
    USE SIGNAL ;
    PORT
      LAYER M4 ;
        RECT  0 9.936 0.084 9.96 ;
    END
  END in_epoch[117]
  PIN in_epoch[118]
    DIRECTION INPUT ;
    USE SIGNAL ;
    PORT
      LAYER M4 ;
        RECT  0 10.032 0.084 10.056 ;
    END
  END in_epoch[118]
  PIN in_epoch[119]
    DIRECTION INPUT ;
    USE SIGNAL ;
    PORT
      LAYER M4 ;
        RECT  0 10.128 0.084 10.152 ;
    END
  END in_epoch[119]
  PIN in_epoch[11]
    DIRECTION INPUT ;
    USE SIGNAL ;
    PORT
      LAYER M4 ;
        RECT  0 21.264 0.084 21.288 ;
    END
  END in_epoch[11]
  PIN in_epoch[120]
    DIRECTION INPUT ;
    USE SIGNAL ;
    PORT
      LAYER M4 ;
        RECT  0 10.224 0.084 10.248 ;
    END
  END in_epoch[120]
  PIN in_epoch[121]
    DIRECTION INPUT ;
    USE SIGNAL ;
    PORT
      LAYER M4 ;
        RECT  0 10.32 0.084 10.344 ;
    END
  END in_epoch[121]
  PIN in_epoch[122]
    DIRECTION INPUT ;
    USE SIGNAL ;
    PORT
      LAYER M4 ;
        RECT  0 10.416 0.084 10.44 ;
    END
  END in_epoch[122]
  PIN in_epoch[123]
    DIRECTION INPUT ;
    USE SIGNAL ;
    PORT
      LAYER M4 ;
        RECT  0 10.512 0.084 10.536 ;
    END
  END in_epoch[123]
  PIN in_epoch[124]
    DIRECTION INPUT ;
    USE SIGNAL ;
    PORT
      LAYER M4 ;
        RECT  0 10.608 0.084 10.632 ;
    END
  END in_epoch[124]
  PIN in_epoch[125]
    DIRECTION INPUT ;
    USE SIGNAL ;
    PORT
      LAYER M4 ;
        RECT  0 10.704 0.084 10.728 ;
    END
  END in_epoch[125]
  PIN in_epoch[126]
    DIRECTION INPUT ;
    USE SIGNAL ;
    PORT
      LAYER M4 ;
        RECT  0 10.8 0.084 10.824 ;
    END
  END in_epoch[126]
  PIN in_epoch[127]
    DIRECTION INPUT ;
    USE SIGNAL ;
    PORT
      LAYER M4 ;
        RECT  0 10.896 0.084 10.92 ;
    END
  END in_epoch[127]
  PIN in_epoch[12]
    DIRECTION INPUT ;
    USE SIGNAL ;
    PORT
      LAYER M4 ;
        RECT  0 21.36 0.084 21.384 ;
    END
  END in_epoch[12]
  PIN in_epoch[13]
    DIRECTION INPUT ;
    USE SIGNAL ;
    PORT
      LAYER M4 ;
        RECT  0 21.456 0.084 21.48 ;
    END
  END in_epoch[13]
  PIN in_epoch[14]
    DIRECTION INPUT ;
    USE SIGNAL ;
    PORT
      LAYER M4 ;
        RECT  0 21.552 0.084 21.576 ;
    END
  END in_epoch[14]
  PIN in_epoch[15]
    DIRECTION INPUT ;
    USE SIGNAL ;
    PORT
      LAYER M4 ;
        RECT  0 21.648 0.084 21.672 ;
    END
  END in_epoch[15]
  PIN in_epoch[16]
    DIRECTION INPUT ;
    USE SIGNAL ;
    PORT
      LAYER M4 ;
        RECT  0 21.744 0.084 21.768 ;
    END
  END in_epoch[16]
  PIN in_epoch[17]
    DIRECTION INPUT ;
    USE SIGNAL ;
    PORT
      LAYER M4 ;
        RECT  0 21.84 0.084 21.864 ;
    END
  END in_epoch[17]
  PIN in_epoch[18]
    DIRECTION INPUT ;
    USE SIGNAL ;
    PORT
      LAYER M4 ;
        RECT  0 21.936 0.084 21.96 ;
    END
  END in_epoch[18]
  PIN in_epoch[19]
    DIRECTION INPUT ;
    USE SIGNAL ;
    PORT
      LAYER M4 ;
        RECT  0 22.032 0.084 22.056 ;
    END
  END in_epoch[19]
  PIN in_epoch[1]
    DIRECTION INPUT ;
    USE SIGNAL ;
    PORT
      LAYER M4 ;
        RECT  0 20.304 0.084 20.328 ;
    END
  END in_epoch[1]
  PIN in_epoch[20]
    DIRECTION INPUT ;
    USE SIGNAL ;
    PORT
      LAYER M4 ;
        RECT  0 22.128 0.084 22.152 ;
    END
  END in_epoch[20]
  PIN in_epoch[21]
    DIRECTION INPUT ;
    USE SIGNAL ;
    PORT
      LAYER M4 ;
        RECT  0 22.224 0.084 22.248 ;
    END
  END in_epoch[21]
  PIN in_epoch[22]
    DIRECTION INPUT ;
    USE SIGNAL ;
    PORT
      LAYER M4 ;
        RECT  0 22.32 0.084 22.344 ;
    END
  END in_epoch[22]
  PIN in_epoch[23]
    DIRECTION INPUT ;
    USE SIGNAL ;
    PORT
      LAYER M4 ;
        RECT  0 22.416 0.084 22.44 ;
    END
  END in_epoch[23]
  PIN in_epoch[24]
    DIRECTION INPUT ;
    USE SIGNAL ;
    PORT
      LAYER M4 ;
        RECT  0 22.512 0.084 22.536 ;
    END
  END in_epoch[24]
  PIN in_epoch[25]
    DIRECTION INPUT ;
    USE SIGNAL ;
    PORT
      LAYER M4 ;
        RECT  0 22.608 0.084 22.632 ;
    END
  END in_epoch[25]
  PIN in_epoch[26]
    DIRECTION INPUT ;
    USE SIGNAL ;
    PORT
      LAYER M4 ;
        RECT  0 22.704 0.084 22.728 ;
    END
  END in_epoch[26]
  PIN in_epoch[27]
    DIRECTION INPUT ;
    USE SIGNAL ;
    PORT
      LAYER M4 ;
        RECT  0 22.8 0.084 22.824 ;
    END
  END in_epoch[27]
  PIN in_epoch[28]
    DIRECTION INPUT ;
    USE SIGNAL ;
    PORT
      LAYER M4 ;
        RECT  0 22.896 0.084 22.92 ;
    END
  END in_epoch[28]
  PIN in_epoch[29]
    DIRECTION INPUT ;
    USE SIGNAL ;
    PORT
      LAYER M4 ;
        RECT  0 22.992 0.084 23.016 ;
    END
  END in_epoch[29]
  PIN in_epoch[2]
    DIRECTION INPUT ;
    USE SIGNAL ;
    PORT
      LAYER M4 ;
        RECT  0 20.4 0.084 20.424 ;
    END
  END in_epoch[2]
  PIN in_epoch[30]
    DIRECTION INPUT ;
    USE SIGNAL ;
    PORT
      LAYER M4 ;
        RECT  0 23.088 0.084 23.112 ;
    END
  END in_epoch[30]
  PIN in_epoch[31]
    DIRECTION INPUT ;
    USE SIGNAL ;
    PORT
      LAYER M4 ;
        RECT  0 23.184 0.084 23.208 ;
    END
  END in_epoch[31]
  PIN in_epoch[32]
    DIRECTION INPUT ;
    USE SIGNAL ;
    PORT
      LAYER M4 ;
        RECT  0 14.064 0.084 14.088 ;
    END
  END in_epoch[32]
  PIN in_epoch[33]
    DIRECTION INPUT ;
    USE SIGNAL ;
    PORT
      LAYER M4 ;
        RECT  0 14.16 0.084 14.184 ;
    END
  END in_epoch[33]
  PIN in_epoch[34]
    DIRECTION INPUT ;
    USE SIGNAL ;
    PORT
      LAYER M4 ;
        RECT  0 14.256 0.084 14.28 ;
    END
  END in_epoch[34]
  PIN in_epoch[35]
    DIRECTION INPUT ;
    USE SIGNAL ;
    PORT
      LAYER M4 ;
        RECT  0 14.352 0.084 14.376 ;
    END
  END in_epoch[35]
  PIN in_epoch[36]
    DIRECTION INPUT ;
    USE SIGNAL ;
    PORT
      LAYER M4 ;
        RECT  0 14.448 0.084 14.472 ;
    END
  END in_epoch[36]
  PIN in_epoch[37]
    DIRECTION INPUT ;
    USE SIGNAL ;
    PORT
      LAYER M4 ;
        RECT  0 14.544 0.084 14.568 ;
    END
  END in_epoch[37]
  PIN in_epoch[38]
    DIRECTION INPUT ;
    USE SIGNAL ;
    PORT
      LAYER M4 ;
        RECT  0 14.64 0.084 14.664 ;
    END
  END in_epoch[38]
  PIN in_epoch[39]
    DIRECTION INPUT ;
    USE SIGNAL ;
    PORT
      LAYER M4 ;
        RECT  0 14.736 0.084 14.76 ;
    END
  END in_epoch[39]
  PIN in_epoch[3]
    DIRECTION INPUT ;
    USE SIGNAL ;
    PORT
      LAYER M4 ;
        RECT  0 20.496 0.084 20.52 ;
    END
  END in_epoch[3]
  PIN in_epoch[40]
    DIRECTION INPUT ;
    USE SIGNAL ;
    PORT
      LAYER M4 ;
        RECT  0 14.832 0.084 14.856 ;
    END
  END in_epoch[40]
  PIN in_epoch[41]
    DIRECTION INPUT ;
    USE SIGNAL ;
    PORT
      LAYER M4 ;
        RECT  0 14.928 0.084 14.952 ;
    END
  END in_epoch[41]
  PIN in_epoch[42]
    DIRECTION INPUT ;
    USE SIGNAL ;
    PORT
      LAYER M4 ;
        RECT  0 15.024 0.084 15.048 ;
    END
  END in_epoch[42]
  PIN in_epoch[43]
    DIRECTION INPUT ;
    USE SIGNAL ;
    PORT
      LAYER M4 ;
        RECT  0 15.12 0.084 15.144 ;
    END
  END in_epoch[43]
  PIN in_epoch[44]
    DIRECTION INPUT ;
    USE SIGNAL ;
    PORT
      LAYER M4 ;
        RECT  0 15.216 0.084 15.24 ;
    END
  END in_epoch[44]
  PIN in_epoch[45]
    DIRECTION INPUT ;
    USE SIGNAL ;
    PORT
      LAYER M4 ;
        RECT  0 15.312 0.084 15.336 ;
    END
  END in_epoch[45]
  PIN in_epoch[46]
    DIRECTION INPUT ;
    USE SIGNAL ;
    PORT
      LAYER M4 ;
        RECT  0 15.408 0.084 15.432 ;
    END
  END in_epoch[46]
  PIN in_epoch[47]
    DIRECTION INPUT ;
    USE SIGNAL ;
    PORT
      LAYER M4 ;
        RECT  0 15.504 0.084 15.528 ;
    END
  END in_epoch[47]
  PIN in_epoch[48]
    DIRECTION INPUT ;
    USE SIGNAL ;
    PORT
      LAYER M4 ;
        RECT  0 15.6 0.084 15.624 ;
    END
  END in_epoch[48]
  PIN in_epoch[49]
    DIRECTION INPUT ;
    USE SIGNAL ;
    PORT
      LAYER M4 ;
        RECT  0 15.696 0.084 15.72 ;
    END
  END in_epoch[49]
  PIN in_epoch[4]
    DIRECTION INPUT ;
    USE SIGNAL ;
    PORT
      LAYER M4 ;
        RECT  0 20.592 0.084 20.616 ;
    END
  END in_epoch[4]
  PIN in_epoch[50]
    DIRECTION INPUT ;
    USE SIGNAL ;
    PORT
      LAYER M4 ;
        RECT  0 15.792 0.084 15.816 ;
    END
  END in_epoch[50]
  PIN in_epoch[51]
    DIRECTION INPUT ;
    USE SIGNAL ;
    PORT
      LAYER M4 ;
        RECT  0 15.888 0.084 15.912 ;
    END
  END in_epoch[51]
  PIN in_epoch[52]
    DIRECTION INPUT ;
    USE SIGNAL ;
    PORT
      LAYER M4 ;
        RECT  0 15.984 0.084 16.008 ;
    END
  END in_epoch[52]
  PIN in_epoch[53]
    DIRECTION INPUT ;
    USE SIGNAL ;
    PORT
      LAYER M4 ;
        RECT  0 16.08 0.084 16.104 ;
    END
  END in_epoch[53]
  PIN in_epoch[54]
    DIRECTION INPUT ;
    USE SIGNAL ;
    PORT
      LAYER M4 ;
        RECT  0 16.176 0.084 16.2 ;
    END
  END in_epoch[54]
  PIN in_epoch[55]
    DIRECTION INPUT ;
    USE SIGNAL ;
    PORT
      LAYER M4 ;
        RECT  0 16.272 0.084 16.296 ;
    END
  END in_epoch[55]
  PIN in_epoch[56]
    DIRECTION INPUT ;
    USE SIGNAL ;
    PORT
      LAYER M4 ;
        RECT  0 16.368 0.084 16.392 ;
    END
  END in_epoch[56]
  PIN in_epoch[57]
    DIRECTION INPUT ;
    USE SIGNAL ;
    PORT
      LAYER M4 ;
        RECT  0 16.464 0.084 16.488 ;
    END
  END in_epoch[57]
  PIN in_epoch[58]
    DIRECTION INPUT ;
    USE SIGNAL ;
    PORT
      LAYER M4 ;
        RECT  0 16.56 0.084 16.584 ;
    END
  END in_epoch[58]
  PIN in_epoch[59]
    DIRECTION INPUT ;
    USE SIGNAL ;
    PORT
      LAYER M4 ;
        RECT  0 16.656 0.084 16.68 ;
    END
  END in_epoch[59]
  PIN in_epoch[5]
    DIRECTION INPUT ;
    USE SIGNAL ;
    PORT
      LAYER M4 ;
        RECT  0 20.688 0.084 20.712 ;
    END
  END in_epoch[5]
  PIN in_epoch[60]
    DIRECTION INPUT ;
    USE SIGNAL ;
    PORT
      LAYER M4 ;
        RECT  0 16.752 0.084 16.776 ;
    END
  END in_epoch[60]
  PIN in_epoch[61]
    DIRECTION INPUT ;
    USE SIGNAL ;
    PORT
      LAYER M4 ;
        RECT  0 16.848 0.084 16.872 ;
    END
  END in_epoch[61]
  PIN in_epoch[62]
    DIRECTION INPUT ;
    USE SIGNAL ;
    PORT
      LAYER M4 ;
        RECT  0 16.944 0.084 16.968 ;
    END
  END in_epoch[62]
  PIN in_epoch[63]
    DIRECTION INPUT ;
    USE SIGNAL ;
    PORT
      LAYER M4 ;
        RECT  0 17.04 0.084 17.064 ;
    END
  END in_epoch[63]
  PIN in_epoch[64]
    DIRECTION INPUT ;
    USE SIGNAL ;
    PORT
      LAYER M4 ;
        RECT  0 10.992 0.084 11.016 ;
    END
  END in_epoch[64]
  PIN in_epoch[65]
    DIRECTION INPUT ;
    USE SIGNAL ;
    PORT
      LAYER M4 ;
        RECT  0 11.088 0.084 11.112 ;
    END
  END in_epoch[65]
  PIN in_epoch[66]
    DIRECTION INPUT ;
    USE SIGNAL ;
    PORT
      LAYER M4 ;
        RECT  0 11.184 0.084 11.208 ;
    END
  END in_epoch[66]
  PIN in_epoch[67]
    DIRECTION INPUT ;
    USE SIGNAL ;
    PORT
      LAYER M4 ;
        RECT  0 11.28 0.084 11.304 ;
    END
  END in_epoch[67]
  PIN in_epoch[68]
    DIRECTION INPUT ;
    USE SIGNAL ;
    PORT
      LAYER M4 ;
        RECT  0 11.376 0.084 11.4 ;
    END
  END in_epoch[68]
  PIN in_epoch[69]
    DIRECTION INPUT ;
    USE SIGNAL ;
    PORT
      LAYER M4 ;
        RECT  0 11.472 0.084 11.496 ;
    END
  END in_epoch[69]
  PIN in_epoch[6]
    DIRECTION INPUT ;
    USE SIGNAL ;
    PORT
      LAYER M4 ;
        RECT  0 20.784 0.084 20.808 ;
    END
  END in_epoch[6]
  PIN in_epoch[70]
    DIRECTION INPUT ;
    USE SIGNAL ;
    PORT
      LAYER M4 ;
        RECT  0 11.568 0.084 11.592 ;
    END
  END in_epoch[70]
  PIN in_epoch[71]
    DIRECTION INPUT ;
    USE SIGNAL ;
    PORT
      LAYER M4 ;
        RECT  0 11.664 0.084 11.688 ;
    END
  END in_epoch[71]
  PIN in_epoch[72]
    DIRECTION INPUT ;
    USE SIGNAL ;
    PORT
      LAYER M4 ;
        RECT  0 11.76 0.084 11.784 ;
    END
  END in_epoch[72]
  PIN in_epoch[73]
    DIRECTION INPUT ;
    USE SIGNAL ;
    PORT
      LAYER M4 ;
        RECT  0 11.856 0.084 11.88 ;
    END
  END in_epoch[73]
  PIN in_epoch[74]
    DIRECTION INPUT ;
    USE SIGNAL ;
    PORT
      LAYER M4 ;
        RECT  0 11.952 0.084 11.976 ;
    END
  END in_epoch[74]
  PIN in_epoch[75]
    DIRECTION INPUT ;
    USE SIGNAL ;
    PORT
      LAYER M4 ;
        RECT  0 12.048 0.084 12.072 ;
    END
  END in_epoch[75]
  PIN in_epoch[76]
    DIRECTION INPUT ;
    USE SIGNAL ;
    PORT
      LAYER M4 ;
        RECT  0 12.144 0.084 12.168 ;
    END
  END in_epoch[76]
  PIN in_epoch[77]
    DIRECTION INPUT ;
    USE SIGNAL ;
    PORT
      LAYER M4 ;
        RECT  0 12.24 0.084 12.264 ;
    END
  END in_epoch[77]
  PIN in_epoch[78]
    DIRECTION INPUT ;
    USE SIGNAL ;
    PORT
      LAYER M4 ;
        RECT  0 12.336 0.084 12.36 ;
    END
  END in_epoch[78]
  PIN in_epoch[79]
    DIRECTION INPUT ;
    USE SIGNAL ;
    PORT
      LAYER M4 ;
        RECT  0 12.432 0.084 12.456 ;
    END
  END in_epoch[79]
  PIN in_epoch[7]
    DIRECTION INPUT ;
    USE SIGNAL ;
    PORT
      LAYER M4 ;
        RECT  0 20.88 0.084 20.904 ;
    END
  END in_epoch[7]
  PIN in_epoch[80]
    DIRECTION INPUT ;
    USE SIGNAL ;
    PORT
      LAYER M4 ;
        RECT  0 12.528 0.084 12.552 ;
    END
  END in_epoch[80]
  PIN in_epoch[81]
    DIRECTION INPUT ;
    USE SIGNAL ;
    PORT
      LAYER M4 ;
        RECT  0 12.624 0.084 12.648 ;
    END
  END in_epoch[81]
  PIN in_epoch[82]
    DIRECTION INPUT ;
    USE SIGNAL ;
    PORT
      LAYER M4 ;
        RECT  0 12.72 0.084 12.744 ;
    END
  END in_epoch[82]
  PIN in_epoch[83]
    DIRECTION INPUT ;
    USE SIGNAL ;
    PORT
      LAYER M4 ;
        RECT  0 12.816 0.084 12.84 ;
    END
  END in_epoch[83]
  PIN in_epoch[84]
    DIRECTION INPUT ;
    USE SIGNAL ;
    PORT
      LAYER M4 ;
        RECT  0 12.912 0.084 12.936 ;
    END
  END in_epoch[84]
  PIN in_epoch[85]
    DIRECTION INPUT ;
    USE SIGNAL ;
    PORT
      LAYER M4 ;
        RECT  0 13.008 0.084 13.032 ;
    END
  END in_epoch[85]
  PIN in_epoch[86]
    DIRECTION INPUT ;
    USE SIGNAL ;
    PORT
      LAYER M4 ;
        RECT  0 13.104 0.084 13.128 ;
    END
  END in_epoch[86]
  PIN in_epoch[87]
    DIRECTION INPUT ;
    USE SIGNAL ;
    PORT
      LAYER M4 ;
        RECT  0 13.2 0.084 13.224 ;
    END
  END in_epoch[87]
  PIN in_epoch[88]
    DIRECTION INPUT ;
    USE SIGNAL ;
    PORT
      LAYER M4 ;
        RECT  0 13.296 0.084 13.32 ;
    END
  END in_epoch[88]
  PIN in_epoch[89]
    DIRECTION INPUT ;
    USE SIGNAL ;
    PORT
      LAYER M4 ;
        RECT  0 13.392 0.084 13.416 ;
    END
  END in_epoch[89]
  PIN in_epoch[8]
    DIRECTION INPUT ;
    USE SIGNAL ;
    PORT
      LAYER M4 ;
        RECT  0 20.976 0.084 21 ;
    END
  END in_epoch[8]
  PIN in_epoch[90]
    DIRECTION INPUT ;
    USE SIGNAL ;
    PORT
      LAYER M4 ;
        RECT  0 13.488 0.084 13.512 ;
    END
  END in_epoch[90]
  PIN in_epoch[91]
    DIRECTION INPUT ;
    USE SIGNAL ;
    PORT
      LAYER M4 ;
        RECT  0 13.584 0.084 13.608 ;
    END
  END in_epoch[91]
  PIN in_epoch[92]
    DIRECTION INPUT ;
    USE SIGNAL ;
    PORT
      LAYER M4 ;
        RECT  0 13.68 0.084 13.704 ;
    END
  END in_epoch[92]
  PIN in_epoch[93]
    DIRECTION INPUT ;
    USE SIGNAL ;
    PORT
      LAYER M4 ;
        RECT  0 13.776 0.084 13.8 ;
    END
  END in_epoch[93]
  PIN in_epoch[94]
    DIRECTION INPUT ;
    USE SIGNAL ;
    PORT
      LAYER M4 ;
        RECT  0 13.872 0.084 13.896 ;
    END
  END in_epoch[94]
  PIN in_epoch[95]
    DIRECTION INPUT ;
    USE SIGNAL ;
    PORT
      LAYER M4 ;
        RECT  0 13.968 0.084 13.992 ;
    END
  END in_epoch[95]
  PIN in_epoch[96]
    DIRECTION INPUT ;
    USE SIGNAL ;
    PORT
      LAYER M4 ;
        RECT  0 7.92 0.084 7.944 ;
    END
  END in_epoch[96]
  PIN in_epoch[97]
    DIRECTION INPUT ;
    USE SIGNAL ;
    PORT
      LAYER M4 ;
        RECT  0 8.016 0.084 8.04 ;
    END
  END in_epoch[97]
  PIN in_epoch[98]
    DIRECTION INPUT ;
    USE SIGNAL ;
    PORT
      LAYER M4 ;
        RECT  0 8.112 0.084 8.136 ;
    END
  END in_epoch[98]
  PIN in_epoch[99]
    DIRECTION INPUT ;
    USE SIGNAL ;
    PORT
      LAYER M4 ;
        RECT  0 8.208 0.084 8.232 ;
    END
  END in_epoch[99]
  PIN in_epoch[9]
    DIRECTION INPUT ;
    USE SIGNAL ;
    PORT
      LAYER M4 ;
        RECT  0 21.072 0.084 21.096 ;
    END
  END in_epoch[9]
  PIN in_t[0]
    DIRECTION INPUT ;
    USE SIGNAL ;
    PORT
      LAYER M4 ;
        RECT  0 17.136 0.084 17.16 ;
    END
  END in_t[0]
  PIN in_t[100]
    DIRECTION INPUT ;
    USE SIGNAL ;
    PORT
      LAYER M4 ;
        RECT  0 24.432 0.084 24.456 ;
    END
  END in_t[100]
  PIN in_t[101]
    DIRECTION INPUT ;
    USE SIGNAL ;
    PORT
      LAYER M4 ;
        RECT  0 24.528 0.084 24.552 ;
    END
  END in_t[101]
  PIN in_t[102]
    DIRECTION INPUT ;
    USE SIGNAL ;
    PORT
      LAYER M4 ;
        RECT  0 24.624 0.084 24.648 ;
    END
  END in_t[102]
  PIN in_t[103]
    DIRECTION INPUT ;
    USE SIGNAL ;
    PORT
      LAYER M4 ;
        RECT  0 24.72 0.084 24.744 ;
    END
  END in_t[103]
  PIN in_t[104]
    DIRECTION INPUT ;
    USE SIGNAL ;
    PORT
      LAYER M4 ;
        RECT  0 24.816 0.084 24.84 ;
    END
  END in_t[104]
  PIN in_t[105]
    DIRECTION INPUT ;
    USE SIGNAL ;
    PORT
      LAYER M4 ;
        RECT  0 24.912 0.084 24.936 ;
    END
  END in_t[105]
  PIN in_t[106]
    DIRECTION INPUT ;
    USE SIGNAL ;
    PORT
      LAYER M4 ;
        RECT  0 25.008 0.084 25.032 ;
    END
  END in_t[106]
  PIN in_t[107]
    DIRECTION INPUT ;
    USE SIGNAL ;
    PORT
      LAYER M4 ;
        RECT  0 25.104 0.084 25.128 ;
    END
  END in_t[107]
  PIN in_t[108]
    DIRECTION INPUT ;
    USE SIGNAL ;
    PORT
      LAYER M4 ;
        RECT  0 25.2 0.084 25.224 ;
    END
  END in_t[108]
  PIN in_t[109]
    DIRECTION INPUT ;
    USE SIGNAL ;
    PORT
      LAYER M4 ;
        RECT  0 25.296 0.084 25.32 ;
    END
  END in_t[109]
  PIN in_t[10]
    DIRECTION INPUT ;
    USE SIGNAL ;
    PORT
      LAYER M4 ;
        RECT  0 18.096 0.084 18.12 ;
    END
  END in_t[10]
  PIN in_t[110]
    DIRECTION INPUT ;
    USE SIGNAL ;
    PORT
      LAYER M4 ;
        RECT  0 25.392 0.084 25.416 ;
    END
  END in_t[110]
  PIN in_t[111]
    DIRECTION INPUT ;
    USE SIGNAL ;
    PORT
      LAYER M4 ;
        RECT  0 25.488 0.084 25.512 ;
    END
  END in_t[111]
  PIN in_t[11]
    DIRECTION INPUT ;
    USE SIGNAL ;
    PORT
      LAYER M4 ;
        RECT  0 18.192 0.084 18.216 ;
    END
  END in_t[11]
  PIN in_t[12]
    DIRECTION INPUT ;
    USE SIGNAL ;
    PORT
      LAYER M4 ;
        RECT  0 18.288 0.084 18.312 ;
    END
  END in_t[12]
  PIN in_t[13]
    DIRECTION INPUT ;
    USE SIGNAL ;
    PORT
      LAYER M4 ;
        RECT  0 18.384 0.084 18.408 ;
    END
  END in_t[13]
  PIN in_t[14]
    DIRECTION INPUT ;
    USE SIGNAL ;
    PORT
      LAYER M4 ;
        RECT  0 18.48 0.084 18.504 ;
    END
  END in_t[14]
  PIN in_t[15]
    DIRECTION INPUT ;
    USE SIGNAL ;
    PORT
      LAYER M4 ;
        RECT  0 18.576 0.084 18.6 ;
    END
  END in_t[15]
  PIN in_t[16]
    DIRECTION INPUT ;
    USE SIGNAL ;
    PORT
      LAYER M4 ;
        RECT  0 18.672 0.084 18.696 ;
    END
  END in_t[16]
  PIN in_t[17]
    DIRECTION INPUT ;
    USE SIGNAL ;
    PORT
      LAYER M4 ;
        RECT  0 18.768 0.084 18.792 ;
    END
  END in_t[17]
  PIN in_t[18]
    DIRECTION INPUT ;
    USE SIGNAL ;
    PORT
      LAYER M4 ;
        RECT  0 18.864 0.084 18.888 ;
    END
  END in_t[18]
  PIN in_t[19]
    DIRECTION INPUT ;
    USE SIGNAL ;
    PORT
      LAYER M4 ;
        RECT  0 18.96 0.084 18.984 ;
    END
  END in_t[19]
  PIN in_t[1]
    DIRECTION INPUT ;
    USE SIGNAL ;
    PORT
      LAYER M4 ;
        RECT  0 17.232 0.084 17.256 ;
    END
  END in_t[1]
  PIN in_t[20]
    DIRECTION INPUT ;
    USE SIGNAL ;
    PORT
      LAYER M4 ;
        RECT  0 19.056 0.084 19.08 ;
    END
  END in_t[20]
  PIN in_t[21]
    DIRECTION INPUT ;
    USE SIGNAL ;
    PORT
      LAYER M4 ;
        RECT  0 19.152 0.084 19.176 ;
    END
  END in_t[21]
  PIN in_t[22]
    DIRECTION INPUT ;
    USE SIGNAL ;
    PORT
      LAYER M4 ;
        RECT  0 19.248 0.084 19.272 ;
    END
  END in_t[22]
  PIN in_t[23]
    DIRECTION INPUT ;
    USE SIGNAL ;
    PORT
      LAYER M4 ;
        RECT  0 19.344 0.084 19.368 ;
    END
  END in_t[23]
  PIN in_t[24]
    DIRECTION INPUT ;
    USE SIGNAL ;
    PORT
      LAYER M4 ;
        RECT  0 19.44 0.084 19.464 ;
    END
  END in_t[24]
  PIN in_t[25]
    DIRECTION INPUT ;
    USE SIGNAL ;
    PORT
      LAYER M4 ;
        RECT  0 19.536 0.084 19.56 ;
    END
  END in_t[25]
  PIN in_t[26]
    DIRECTION INPUT ;
    USE SIGNAL ;
    PORT
      LAYER M4 ;
        RECT  0 19.632 0.084 19.656 ;
    END
  END in_t[26]
  PIN in_t[27]
    DIRECTION INPUT ;
    USE SIGNAL ;
    PORT
      LAYER M4 ;
        RECT  0 19.728 0.084 19.752 ;
    END
  END in_t[27]
  PIN in_t[28]
    DIRECTION INPUT ;
    USE SIGNAL ;
    PORT
      LAYER M4 ;
        RECT  0 19.824 0.084 19.848 ;
    END
  END in_t[28]
  PIN in_t[29]
    DIRECTION INPUT ;
    USE SIGNAL ;
    PORT
      LAYER M4 ;
        RECT  0 19.92 0.084 19.944 ;
    END
  END in_t[29]
  PIN in_t[2]
    DIRECTION INPUT ;
    USE SIGNAL ;
    PORT
      LAYER M4 ;
        RECT  0 17.328 0.084 17.352 ;
    END
  END in_t[2]
  PIN in_t[30]
    DIRECTION INPUT ;
    USE SIGNAL ;
    PORT
      LAYER M4 ;
        RECT  0 20.016 0.084 20.04 ;
    END
  END in_t[30]
  PIN in_t[31]
    DIRECTION INPUT ;
    USE SIGNAL ;
    PORT
      LAYER M4 ;
        RECT  0 20.112 0.084 20.136 ;
    END
  END in_t[31]
  PIN in_t[32]
    DIRECTION INPUT ;
    USE SIGNAL ;
    PORT
      LAYER M4 ;
        RECT  0 4.848 0.084 4.872 ;
    END
  END in_t[32]
  PIN in_t[33]
    DIRECTION INPUT ;
    USE SIGNAL ;
    PORT
      LAYER M4 ;
        RECT  0 4.944 0.084 4.968 ;
    END
  END in_t[33]
  PIN in_t[34]
    DIRECTION INPUT ;
    USE SIGNAL ;
    PORT
      LAYER M4 ;
        RECT  0 5.04 0.084 5.064 ;
    END
  END in_t[34]
  PIN in_t[35]
    DIRECTION INPUT ;
    USE SIGNAL ;
    PORT
      LAYER M4 ;
        RECT  0 5.136 0.084 5.16 ;
    END
  END in_t[35]
  PIN in_t[36]
    DIRECTION INPUT ;
    USE SIGNAL ;
    PORT
      LAYER M4 ;
        RECT  0 5.232 0.084 5.256 ;
    END
  END in_t[36]
  PIN in_t[37]
    DIRECTION INPUT ;
    USE SIGNAL ;
    PORT
      LAYER M4 ;
        RECT  0 5.328 0.084 5.352 ;
    END
  END in_t[37]
  PIN in_t[38]
    DIRECTION INPUT ;
    USE SIGNAL ;
    PORT
      LAYER M4 ;
        RECT  0 5.424 0.084 5.448 ;
    END
  END in_t[38]
  PIN in_t[39]
    DIRECTION INPUT ;
    USE SIGNAL ;
    PORT
      LAYER M4 ;
        RECT  0 5.52 0.084 5.544 ;
    END
  END in_t[39]
  PIN in_t[3]
    DIRECTION INPUT ;
    USE SIGNAL ;
    PORT
      LAYER M4 ;
        RECT  0 17.424 0.084 17.448 ;
    END
  END in_t[3]
  PIN in_t[40]
    DIRECTION INPUT ;
    USE SIGNAL ;
    PORT
      LAYER M4 ;
        RECT  0 5.616 0.084 5.64 ;
    END
  END in_t[40]
  PIN in_t[41]
    DIRECTION INPUT ;
    USE SIGNAL ;
    PORT
      LAYER M4 ;
        RECT  0 5.712 0.084 5.736 ;
    END
  END in_t[41]
  PIN in_t[42]
    DIRECTION INPUT ;
    USE SIGNAL ;
    PORT
      LAYER M4 ;
        RECT  0 5.808 0.084 5.832 ;
    END
  END in_t[42]
  PIN in_t[43]
    DIRECTION INPUT ;
    USE SIGNAL ;
    PORT
      LAYER M4 ;
        RECT  0 5.904 0.084 5.928 ;
    END
  END in_t[43]
  PIN in_t[44]
    DIRECTION INPUT ;
    USE SIGNAL ;
    PORT
      LAYER M4 ;
        RECT  0 6 0.084 6.024 ;
    END
  END in_t[44]
  PIN in_t[45]
    DIRECTION INPUT ;
    USE SIGNAL ;
    PORT
      LAYER M4 ;
        RECT  0 6.096 0.084 6.12 ;
    END
  END in_t[45]
  PIN in_t[46]
    DIRECTION INPUT ;
    USE SIGNAL ;
    PORT
      LAYER M4 ;
        RECT  0 6.192 0.084 6.216 ;
    END
  END in_t[46]
  PIN in_t[47]
    DIRECTION INPUT ;
    USE SIGNAL ;
    PORT
      LAYER M4 ;
        RECT  0 6.288 0.084 6.312 ;
    END
  END in_t[47]
  PIN in_t[48]
    DIRECTION INPUT ;
    USE SIGNAL ;
    PORT
      LAYER M4 ;
        RECT  0 6.384 0.084 6.408 ;
    END
  END in_t[48]
  PIN in_t[49]
    DIRECTION INPUT ;
    USE SIGNAL ;
    PORT
      LAYER M4 ;
        RECT  0 6.48 0.084 6.504 ;
    END
  END in_t[49]
  PIN in_t[4]
    DIRECTION INPUT ;
    USE SIGNAL ;
    PORT
      LAYER M4 ;
        RECT  0 17.52 0.084 17.544 ;
    END
  END in_t[4]
  PIN in_t[50]
    DIRECTION INPUT ;
    USE SIGNAL ;
    PORT
      LAYER M4 ;
        RECT  0 6.576 0.084 6.6 ;
    END
  END in_t[50]
  PIN in_t[51]
    DIRECTION INPUT ;
    USE SIGNAL ;
    PORT
      LAYER M4 ;
        RECT  0 6.672 0.084 6.696 ;
    END
  END in_t[51]
  PIN in_t[52]
    DIRECTION INPUT ;
    USE SIGNAL ;
    PORT
      LAYER M4 ;
        RECT  0 6.768 0.084 6.792 ;
    END
  END in_t[52]
  PIN in_t[53]
    DIRECTION INPUT ;
    USE SIGNAL ;
    PORT
      LAYER M4 ;
        RECT  0 6.864 0.084 6.888 ;
    END
  END in_t[53]
  PIN in_t[54]
    DIRECTION INPUT ;
    USE SIGNAL ;
    PORT
      LAYER M4 ;
        RECT  0 6.96 0.084 6.984 ;
    END
  END in_t[54]
  PIN in_t[55]
    DIRECTION INPUT ;
    USE SIGNAL ;
    PORT
      LAYER M4 ;
        RECT  0 7.056 0.084 7.08 ;
    END
  END in_t[55]
  PIN in_t[56]
    DIRECTION INPUT ;
    USE SIGNAL ;
    PORT
      LAYER M4 ;
        RECT  0 7.152 0.084 7.176 ;
    END
  END in_t[56]
  PIN in_t[57]
    DIRECTION INPUT ;
    USE SIGNAL ;
    PORT
      LAYER M4 ;
        RECT  0 7.248 0.084 7.272 ;
    END
  END in_t[57]
  PIN in_t[58]
    DIRECTION INPUT ;
    USE SIGNAL ;
    PORT
      LAYER M4 ;
        RECT  0 7.344 0.084 7.368 ;
    END
  END in_t[58]
  PIN in_t[59]
    DIRECTION INPUT ;
    USE SIGNAL ;
    PORT
      LAYER M4 ;
        RECT  0 7.44 0.084 7.464 ;
    END
  END in_t[59]
  PIN in_t[5]
    DIRECTION INPUT ;
    USE SIGNAL ;
    PORT
      LAYER M4 ;
        RECT  0 17.616 0.084 17.64 ;
    END
  END in_t[5]
  PIN in_t[60]
    DIRECTION INPUT ;
    USE SIGNAL ;
    PORT
      LAYER M4 ;
        RECT  0 7.536 0.084 7.56 ;
    END
  END in_t[60]
  PIN in_t[61]
    DIRECTION INPUT ;
    USE SIGNAL ;
    PORT
      LAYER M4 ;
        RECT  0 7.632 0.084 7.656 ;
    END
  END in_t[61]
  PIN in_t[62]
    DIRECTION INPUT ;
    USE SIGNAL ;
    PORT
      LAYER M4 ;
        RECT  0 7.728 0.084 7.752 ;
    END
  END in_t[62]
  PIN in_t[63]
    DIRECTION INPUT ;
    USE SIGNAL ;
    PORT
      LAYER M4 ;
        RECT  0 7.824 0.084 7.848 ;
    END
  END in_t[63]
  PIN in_t[64]
    DIRECTION INPUT ;
    USE SIGNAL ;
    PORT
      LAYER M4 ;
        RECT  0 1.008 0.084 1.032 ;
    END
  END in_t[64]
  PIN in_t[65]
    DIRECTION INPUT ;
    USE SIGNAL ;
    PORT
      LAYER M4 ;
        RECT  0 1.104 0.084 1.128 ;
    END
  END in_t[65]
  PIN in_t[66]
    DIRECTION INPUT ;
    USE SIGNAL ;
    PORT
      LAYER M4 ;
        RECT  0 1.2 0.084 1.224 ;
    END
  END in_t[66]
  PIN in_t[67]
    DIRECTION INPUT ;
    USE SIGNAL ;
    PORT
      LAYER M4 ;
        RECT  0 1.296 0.084 1.32 ;
    END
  END in_t[67]
  PIN in_t[68]
    DIRECTION INPUT ;
    USE SIGNAL ;
    PORT
      LAYER M4 ;
        RECT  0 1.392 0.084 1.416 ;
    END
  END in_t[68]
  PIN in_t[69]
    DIRECTION INPUT ;
    USE SIGNAL ;
    PORT
      LAYER M4 ;
        RECT  0 1.488 0.084 1.512 ;
    END
  END in_t[69]
  PIN in_t[6]
    DIRECTION INPUT ;
    USE SIGNAL ;
    PORT
      LAYER M4 ;
        RECT  0 17.712 0.084 17.736 ;
    END
  END in_t[6]
  PIN in_t[70]
    DIRECTION INPUT ;
    USE SIGNAL ;
    PORT
      LAYER M4 ;
        RECT  0 1.584 0.084 1.608 ;
    END
  END in_t[70]
  PIN in_t[71]
    DIRECTION INPUT ;
    USE SIGNAL ;
    PORT
      LAYER M4 ;
        RECT  0 1.68 0.084 1.704 ;
    END
  END in_t[71]
  PIN in_t[72]
    DIRECTION INPUT ;
    USE SIGNAL ;
    PORT
      LAYER M4 ;
        RECT  0 1.776 0.084 1.8 ;
    END
  END in_t[72]
  PIN in_t[73]
    DIRECTION INPUT ;
    USE SIGNAL ;
    PORT
      LAYER M4 ;
        RECT  0 1.872 0.084 1.896 ;
    END
  END in_t[73]
  PIN in_t[74]
    DIRECTION INPUT ;
    USE SIGNAL ;
    PORT
      LAYER M4 ;
        RECT  0 1.968 0.084 1.992 ;
    END
  END in_t[74]
  PIN in_t[75]
    DIRECTION INPUT ;
    USE SIGNAL ;
    PORT
      LAYER M4 ;
        RECT  0 2.064 0.084 2.088 ;
    END
  END in_t[75]
  PIN in_t[76]
    DIRECTION INPUT ;
    USE SIGNAL ;
    PORT
      LAYER M4 ;
        RECT  0 2.16 0.084 2.184 ;
    END
  END in_t[76]
  PIN in_t[77]
    DIRECTION INPUT ;
    USE SIGNAL ;
    PORT
      LAYER M4 ;
        RECT  0 2.256 0.084 2.28 ;
    END
  END in_t[77]
  PIN in_t[78]
    DIRECTION INPUT ;
    USE SIGNAL ;
    PORT
      LAYER M4 ;
        RECT  0 2.352 0.084 2.376 ;
    END
  END in_t[78]
  PIN in_t[79]
    DIRECTION INPUT ;
    USE SIGNAL ;
    PORT
      LAYER M4 ;
        RECT  0 2.448 0.084 2.472 ;
    END
  END in_t[79]
  PIN in_t[7]
    DIRECTION INPUT ;
    USE SIGNAL ;
    PORT
      LAYER M4 ;
        RECT  0 17.808 0.084 17.832 ;
    END
  END in_t[7]
  PIN in_t[80]
    DIRECTION INPUT ;
    USE SIGNAL ;
    PORT
      LAYER M4 ;
        RECT  0 2.544 0.084 2.568 ;
    END
  END in_t[80]
  PIN in_t[81]
    DIRECTION INPUT ;
    USE SIGNAL ;
    PORT
      LAYER M4 ;
        RECT  0 2.64 0.084 2.664 ;
    END
  END in_t[81]
  PIN in_t[82]
    DIRECTION INPUT ;
    USE SIGNAL ;
    PORT
      LAYER M4 ;
        RECT  0 2.736 0.084 2.76 ;
    END
  END in_t[82]
  PIN in_t[83]
    DIRECTION INPUT ;
    USE SIGNAL ;
    PORT
      LAYER M4 ;
        RECT  0 2.832 0.084 2.856 ;
    END
  END in_t[83]
  PIN in_t[84]
    DIRECTION INPUT ;
    USE SIGNAL ;
    PORT
      LAYER M4 ;
        RECT  0 2.928 0.084 2.952 ;
    END
  END in_t[84]
  PIN in_t[85]
    DIRECTION INPUT ;
    USE SIGNAL ;
    PORT
      LAYER M4 ;
        RECT  0 3.024 0.084 3.048 ;
    END
  END in_t[85]
  PIN in_t[86]
    DIRECTION INPUT ;
    USE SIGNAL ;
    PORT
      LAYER M4 ;
        RECT  0 3.12 0.084 3.144 ;
    END
  END in_t[86]
  PIN in_t[87]
    DIRECTION INPUT ;
    USE SIGNAL ;
    PORT
      LAYER M4 ;
        RECT  0 3.216 0.084 3.24 ;
    END
  END in_t[87]
  PIN in_t[88]
    DIRECTION INPUT ;
    USE SIGNAL ;
    PORT
      LAYER M4 ;
        RECT  0 3.312 0.084 3.336 ;
    END
  END in_t[88]
  PIN in_t[89]
    DIRECTION INPUT ;
    USE SIGNAL ;
    PORT
      LAYER M4 ;
        RECT  0 3.408 0.084 3.432 ;
    END
  END in_t[89]
  PIN in_t[8]
    DIRECTION INPUT ;
    USE SIGNAL ;
    PORT
      LAYER M4 ;
        RECT  0 17.904 0.084 17.928 ;
    END
  END in_t[8]
  PIN in_t[90]
    DIRECTION INPUT ;
    USE SIGNAL ;
    PORT
      LAYER M4 ;
        RECT  0 3.504 0.084 3.528 ;
    END
  END in_t[90]
  PIN in_t[91]
    DIRECTION INPUT ;
    USE SIGNAL ;
    PORT
      LAYER M4 ;
        RECT  0 3.6 0.084 3.624 ;
    END
  END in_t[91]
  PIN in_t[92]
    DIRECTION INPUT ;
    USE SIGNAL ;
    PORT
      LAYER M4 ;
        RECT  0 3.696 0.084 3.72 ;
    END
  END in_t[92]
  PIN in_t[93]
    DIRECTION INPUT ;
    USE SIGNAL ;
    PORT
      LAYER M4 ;
        RECT  0 3.792 0.084 3.816 ;
    END
  END in_t[93]
  PIN in_t[94]
    DIRECTION INPUT ;
    USE SIGNAL ;
    PORT
      LAYER M4 ;
        RECT  0 3.888 0.084 3.912 ;
    END
  END in_t[94]
  PIN in_t[95]
    DIRECTION INPUT ;
    USE SIGNAL ;
    PORT
      LAYER M4 ;
        RECT  0 3.984 0.084 4.008 ;
    END
  END in_t[95]
  PIN in_t[96]
    DIRECTION INPUT ;
    USE SIGNAL ;
    PORT
      LAYER M4 ;
        RECT  0 24.048 0.084 24.072 ;
    END
  END in_t[96]
  PIN in_t[97]
    DIRECTION INPUT ;
    USE SIGNAL ;
    PORT
      LAYER M4 ;
        RECT  0 24.144 0.084 24.168 ;
    END
  END in_t[97]
  PIN in_t[98]
    DIRECTION INPUT ;
    USE SIGNAL ;
    PORT
      LAYER M4 ;
        RECT  0 24.24 0.084 24.264 ;
    END
  END in_t[98]
  PIN in_t[99]
    DIRECTION INPUT ;
    USE SIGNAL ;
    PORT
      LAYER M4 ;
        RECT  0 24.336 0.084 24.36 ;
    END
  END in_t[99]
  PIN in_t[9]
    DIRECTION INPUT ;
    USE SIGNAL ;
    PORT
      LAYER M4 ;
        RECT  0 18 0.084 18.024 ;
    END
  END in_t[9]
  PIN in_valid[0]
    DIRECTION INPUT ;
    USE SIGNAL ;
    PORT
      LAYER M4 ;
        RECT  0 25.584 0.084 25.608 ;
    END
  END in_valid[0]
  PIN in_valid[1]
    DIRECTION INPUT ;
    USE SIGNAL ;
    PORT
      LAYER M4 ;
        RECT  0 25.68 0.084 25.704 ;
    END
  END in_valid[1]
  PIN in_valid[2]
    DIRECTION INPUT ;
    USE SIGNAL ;
    PORT
      LAYER M4 ;
        RECT  0 25.776 0.084 25.8 ;
    END
  END in_valid[2]
  PIN in_valid[3]
    DIRECTION INPUT ;
    USE SIGNAL ;
    PORT
      LAYER M4 ;
        RECT  0 25.872 0.084 25.896 ;
    END
  END in_valid[3]
  PIN in_valid[4]
    DIRECTION INPUT ;
    USE SIGNAL ;
    PORT
      LAYER M4 ;
        RECT  0 25.968 0.084 25.992 ;
    END
  END in_valid[4]
  PIN in_valid[5]
    DIRECTION INPUT ;
    USE SIGNAL ;
    PORT
      LAYER M4 ;
        RECT  0 26.064 0.084 26.088 ;
    END
  END in_valid[5]
  PIN in_valid[6]
    DIRECTION INPUT ;
    USE SIGNAL ;
    PORT
      LAYER M4 ;
        RECT  0 26.16 0.084 26.184 ;
    END
  END in_valid[6]
  PIN in_valid[7]
    DIRECTION INPUT ;
    USE SIGNAL ;
    PORT
      LAYER M4 ;
        RECT  0 26.256 0.084 26.28 ;
    END
  END in_valid[7]
  PIN out_age[0]
    DIRECTION OUTPUT ;
    USE SIGNAL ;
    PORT
      LAYER M5 ;
        RECT  20.016 0 20.04 0.084 ;
    END
  END out_age[0]
  PIN out_age[10]
    DIRECTION OUTPUT ;
    USE SIGNAL ;
    PORT
      LAYER M5 ;
        RECT  20.976 0 21 0.084 ;
    END
  END out_age[10]
  PIN out_age[11]
    DIRECTION OUTPUT ;
    USE SIGNAL ;
    PORT
      LAYER M5 ;
        RECT  21.072 0 21.096 0.084 ;
    END
  END out_age[11]
  PIN out_age[12]
    DIRECTION OUTPUT ;
    USE SIGNAL ;
    PORT
      LAYER M5 ;
        RECT  21.168 0 21.192 0.084 ;
    END
  END out_age[12]
  PIN out_age[13]
    DIRECTION OUTPUT ;
    USE SIGNAL ;
    PORT
      LAYER M5 ;
        RECT  21.264 0 21.288 0.084 ;
    END
  END out_age[13]
  PIN out_age[14]
    DIRECTION OUTPUT ;
    USE SIGNAL ;
    PORT
      LAYER M5 ;
        RECT  21.36 0 21.384 0.084 ;
    END
  END out_age[14]
  PIN out_age[15]
    DIRECTION OUTPUT ;
    USE SIGNAL ;
    PORT
      LAYER M5 ;
        RECT  21.456 0 21.48 0.084 ;
    END
  END out_age[15]
  PIN out_age[1]
    DIRECTION OUTPUT ;
    USE SIGNAL ;
    PORT
      LAYER M5 ;
        RECT  20.112 0 20.136 0.084 ;
    END
  END out_age[1]
  PIN out_age[2]
    DIRECTION OUTPUT ;
    USE SIGNAL ;
    PORT
      LAYER M5 ;
        RECT  20.208 0 20.232 0.084 ;
    END
  END out_age[2]
  PIN out_age[3]
    DIRECTION OUTPUT ;
    USE SIGNAL ;
    PORT
      LAYER M5 ;
        RECT  20.304 0 20.328 0.084 ;
    END
  END out_age[3]
  PIN out_age[4]
    DIRECTION OUTPUT ;
    USE SIGNAL ;
    PORT
      LAYER M5 ;
        RECT  20.4 0 20.424 0.084 ;
    END
  END out_age[4]
  PIN out_age[5]
    DIRECTION OUTPUT ;
    USE SIGNAL ;
    PORT
      LAYER M5 ;
        RECT  20.496 0 20.52 0.084 ;
    END
  END out_age[5]
  PIN out_age[6]
    DIRECTION OUTPUT ;
    USE SIGNAL ;
    PORT
      LAYER M5 ;
        RECT  20.592 0 20.616 0.084 ;
    END
  END out_age[6]
  PIN out_age[7]
    DIRECTION OUTPUT ;
    USE SIGNAL ;
    PORT
      LAYER M5 ;
        RECT  20.688 0 20.712 0.084 ;
    END
  END out_age[7]
  PIN out_age[8]
    DIRECTION OUTPUT ;
    USE SIGNAL ;
    PORT
      LAYER M5 ;
        RECT  20.784 0 20.808 0.084 ;
    END
  END out_age[8]
  PIN out_age[9]
    DIRECTION OUTPUT ;
    USE SIGNAL ;
    PORT
      LAYER M5 ;
        RECT  20.88 0 20.904 0.084 ;
    END
  END out_age[9]
  PIN out_epoch[0]
    DIRECTION OUTPUT ;
    USE SIGNAL ;
    PORT
      LAYER M5 ;
        RECT  21.552 0 21.576 0.084 ;
    END
  END out_epoch[0]
  PIN out_epoch[10]
    DIRECTION OUTPUT ;
    USE SIGNAL ;
    PORT
      LAYER M5 ;
        RECT  22.512 0 22.536 0.084 ;
    END
  END out_epoch[10]
  PIN out_epoch[11]
    DIRECTION OUTPUT ;
    USE SIGNAL ;
    PORT
      LAYER M5 ;
        RECT  22.608 0 22.632 0.084 ;
    END
  END out_epoch[11]
  PIN out_epoch[12]
    DIRECTION OUTPUT ;
    USE SIGNAL ;
    PORT
      LAYER M5 ;
        RECT  22.704 0 22.728 0.084 ;
    END
  END out_epoch[12]
  PIN out_epoch[13]
    DIRECTION OUTPUT ;
    USE SIGNAL ;
    PORT
      LAYER M5 ;
        RECT  22.8 0 22.824 0.084 ;
    END
  END out_epoch[13]
  PIN out_epoch[14]
    DIRECTION OUTPUT ;
    USE SIGNAL ;
    PORT
      LAYER M5 ;
        RECT  22.896 0 22.92 0.084 ;
    END
  END out_epoch[14]
  PIN out_epoch[15]
    DIRECTION OUTPUT ;
    USE SIGNAL ;
    PORT
      LAYER M5 ;
        RECT  16.08 0 16.104 0.084 ;
    END
  END out_epoch[15]
  PIN out_epoch[1]
    DIRECTION OUTPUT ;
    USE SIGNAL ;
    PORT
      LAYER M5 ;
        RECT  21.648 0 21.672 0.084 ;
    END
  END out_epoch[1]
  PIN out_epoch[2]
    DIRECTION OUTPUT ;
    USE SIGNAL ;
    PORT
      LAYER M5 ;
        RECT  21.744 0 21.768 0.084 ;
    END
  END out_epoch[2]
  PIN out_epoch[3]
    DIRECTION OUTPUT ;
    USE SIGNAL ;
    PORT
      LAYER M5 ;
        RECT  21.84 0 21.864 0.084 ;
    END
  END out_epoch[3]
  PIN out_epoch[4]
    DIRECTION OUTPUT ;
    USE SIGNAL ;
    PORT
      LAYER M5 ;
        RECT  21.936 0 21.96 0.084 ;
    END
  END out_epoch[4]
  PIN out_epoch[5]
    DIRECTION OUTPUT ;
    USE SIGNAL ;
    PORT
      LAYER M5 ;
        RECT  22.032 0 22.056 0.084 ;
    END
  END out_epoch[5]
  PIN out_epoch[6]
    DIRECTION OUTPUT ;
    USE SIGNAL ;
    PORT
      LAYER M5 ;
        RECT  22.128 0 22.152 0.084 ;
    END
  END out_epoch[6]
  PIN out_epoch[7]
    DIRECTION OUTPUT ;
    USE SIGNAL ;
    PORT
      LAYER M5 ;
        RECT  22.224 0 22.248 0.084 ;
    END
  END out_epoch[7]
  PIN out_epoch[8]
    DIRECTION OUTPUT ;
    USE SIGNAL ;
    PORT
      LAYER M5 ;
        RECT  22.32 0 22.344 0.084 ;
    END
  END out_epoch[8]
  PIN out_epoch[9]
    DIRECTION OUTPUT ;
    USE SIGNAL ;
    PORT
      LAYER M5 ;
        RECT  22.416 0 22.44 0.084 ;
    END
  END out_epoch[9]
  PIN pair_id
    DIRECTION INPUT ;
    USE SIGNAL ;
    PORT
      LAYER M5 ;
        RECT  16.176 0 16.2 0.084 ;
    END
  END pair_id
  PIN req_t[0]
    DIRECTION OUTPUT ;
    USE SIGNAL ;
    PORT
      LAYER M4 ;
        RECT  43.116 39.12 43.2 39.144 ;
    END
  END req_t[0]
  PIN req_t[100]
    DIRECTION OUTPUT ;
    USE SIGNAL ;
    PORT
      LAYER M4 ;
        RECT  43.116 29.52 43.2 29.544 ;
    END
  END req_t[100]
  PIN req_t[101]
    DIRECTION OUTPUT ;
    USE SIGNAL ;
    PORT
      LAYER M4 ;
        RECT  43.116 29.616 43.2 29.64 ;
    END
  END req_t[101]
  PIN req_t[102]
    DIRECTION OUTPUT ;
    USE SIGNAL ;
    PORT
      LAYER M4 ;
        RECT  43.116 29.712 43.2 29.736 ;
    END
  END req_t[102]
  PIN req_t[103]
    DIRECTION OUTPUT ;
    USE SIGNAL ;
    PORT
      LAYER M4 ;
        RECT  43.116 29.808 43.2 29.832 ;
    END
  END req_t[103]
  PIN req_t[104]
    DIRECTION OUTPUT ;
    USE SIGNAL ;
    PORT
      LAYER M4 ;
        RECT  43.116 29.904 43.2 29.928 ;
    END
  END req_t[104]
  PIN req_t[105]
    DIRECTION OUTPUT ;
    USE SIGNAL ;
    PORT
      LAYER M4 ;
        RECT  43.116 30 43.2 30.024 ;
    END
  END req_t[105]
  PIN req_t[106]
    DIRECTION OUTPUT ;
    USE SIGNAL ;
    PORT
      LAYER M4 ;
        RECT  43.116 30.096 43.2 30.12 ;
    END
  END req_t[106]
  PIN req_t[107]
    DIRECTION OUTPUT ;
    USE SIGNAL ;
    PORT
      LAYER M4 ;
        RECT  43.116 30.192 43.2 30.216 ;
    END
  END req_t[107]
  PIN req_t[108]
    DIRECTION OUTPUT ;
    USE SIGNAL ;
    PORT
      LAYER M4 ;
        RECT  43.116 30.288 43.2 30.312 ;
    END
  END req_t[108]
  PIN req_t[109]
    DIRECTION OUTPUT ;
    USE SIGNAL ;
    PORT
      LAYER M4 ;
        RECT  43.116 30.384 43.2 30.408 ;
    END
  END req_t[109]
  PIN req_t[10]
    DIRECTION OUTPUT ;
    USE SIGNAL ;
    PORT
      LAYER M4 ;
        RECT  43.116 40.08 43.2 40.104 ;
    END
  END req_t[10]
  PIN req_t[110]
    DIRECTION OUTPUT ;
    USE SIGNAL ;
    PORT
      LAYER M4 ;
        RECT  43.116 30.48 43.2 30.504 ;
    END
  END req_t[110]
  PIN req_t[111]
    DIRECTION OUTPUT ;
    USE SIGNAL ;
    PORT
      LAYER M4 ;
        RECT  43.116 30.576 43.2 30.6 ;
    END
  END req_t[111]
  PIN req_t[11]
    DIRECTION OUTPUT ;
    USE SIGNAL ;
    PORT
      LAYER M4 ;
        RECT  43.116 40.176 43.2 40.2 ;
    END
  END req_t[11]
  PIN req_t[12]
    DIRECTION OUTPUT ;
    USE SIGNAL ;
    PORT
      LAYER M4 ;
        RECT  43.116 40.272 43.2 40.296 ;
    END
  END req_t[12]
  PIN req_t[13]
    DIRECTION OUTPUT ;
    USE SIGNAL ;
    PORT
      LAYER M4 ;
        RECT  43.116 40.368 43.2 40.392 ;
    END
  END req_t[13]
  PIN req_t[14]
    DIRECTION OUTPUT ;
    USE SIGNAL ;
    PORT
      LAYER M4 ;
        RECT  43.116 40.464 43.2 40.488 ;
    END
  END req_t[14]
  PIN req_t[15]
    DIRECTION OUTPUT ;
    USE SIGNAL ;
    PORT
      LAYER M4 ;
        RECT  43.116 40.56 43.2 40.584 ;
    END
  END req_t[15]
  PIN req_t[16]
    DIRECTION OUTPUT ;
    USE SIGNAL ;
    PORT
      LAYER M4 ;
        RECT  43.116 40.656 43.2 40.68 ;
    END
  END req_t[16]
  PIN req_t[17]
    DIRECTION OUTPUT ;
    USE SIGNAL ;
    PORT
      LAYER M4 ;
        RECT  43.116 40.752 43.2 40.776 ;
    END
  END req_t[17]
  PIN req_t[18]
    DIRECTION OUTPUT ;
    USE SIGNAL ;
    PORT
      LAYER M4 ;
        RECT  43.116 40.848 43.2 40.872 ;
    END
  END req_t[18]
  PIN req_t[19]
    DIRECTION OUTPUT ;
    USE SIGNAL ;
    PORT
      LAYER M4 ;
        RECT  43.116 40.944 43.2 40.968 ;
    END
  END req_t[19]
  PIN req_t[1]
    DIRECTION OUTPUT ;
    USE SIGNAL ;
    PORT
      LAYER M4 ;
        RECT  43.116 39.216 43.2 39.24 ;
    END
  END req_t[1]
  PIN req_t[20]
    DIRECTION OUTPUT ;
    USE SIGNAL ;
    PORT
      LAYER M4 ;
        RECT  43.116 41.04 43.2 41.064 ;
    END
  END req_t[20]
  PIN req_t[21]
    DIRECTION OUTPUT ;
    USE SIGNAL ;
    PORT
      LAYER M4 ;
        RECT  43.116 41.136 43.2 41.16 ;
    END
  END req_t[21]
  PIN req_t[22]
    DIRECTION OUTPUT ;
    USE SIGNAL ;
    PORT
      LAYER M4 ;
        RECT  43.116 41.232 43.2 41.256 ;
    END
  END req_t[22]
  PIN req_t[23]
    DIRECTION OUTPUT ;
    USE SIGNAL ;
    PORT
      LAYER M4 ;
        RECT  43.116 41.328 43.2 41.352 ;
    END
  END req_t[23]
  PIN req_t[24]
    DIRECTION OUTPUT ;
    USE SIGNAL ;
    PORT
      LAYER M4 ;
        RECT  43.116 41.424 43.2 41.448 ;
    END
  END req_t[24]
  PIN req_t[25]
    DIRECTION OUTPUT ;
    USE SIGNAL ;
    PORT
      LAYER M4 ;
        RECT  43.116 41.52 43.2 41.544 ;
    END
  END req_t[25]
  PIN req_t[26]
    DIRECTION OUTPUT ;
    USE SIGNAL ;
    PORT
      LAYER M4 ;
        RECT  43.116 41.616 43.2 41.64 ;
    END
  END req_t[26]
  PIN req_t[27]
    DIRECTION OUTPUT ;
    USE SIGNAL ;
    PORT
      LAYER M4 ;
        RECT  43.116 41.712 43.2 41.736 ;
    END
  END req_t[27]
  PIN req_t[28]
    DIRECTION OUTPUT ;
    USE SIGNAL ;
    PORT
      LAYER M4 ;
        RECT  43.116 41.808 43.2 41.832 ;
    END
  END req_t[28]
  PIN req_t[29]
    DIRECTION OUTPUT ;
    USE SIGNAL ;
    PORT
      LAYER M4 ;
        RECT  43.116 41.904 43.2 41.928 ;
    END
  END req_t[29]
  PIN req_t[2]
    DIRECTION OUTPUT ;
    USE SIGNAL ;
    PORT
      LAYER M4 ;
        RECT  43.116 39.312 43.2 39.336 ;
    END
  END req_t[2]
  PIN req_t[30]
    DIRECTION OUTPUT ;
    USE SIGNAL ;
    PORT
      LAYER M4 ;
        RECT  43.116 42 43.2 42.024 ;
    END
  END req_t[30]
  PIN req_t[31]
    DIRECTION OUTPUT ;
    USE SIGNAL ;
    PORT
      LAYER M4 ;
        RECT  43.116 42.096 43.2 42.12 ;
    END
  END req_t[31]
  PIN req_t[32]
    DIRECTION OUTPUT ;
    USE SIGNAL ;
    PORT
      LAYER M4 ;
        RECT  43.116 35.28 43.2 35.304 ;
    END
  END req_t[32]
  PIN req_t[33]
    DIRECTION OUTPUT ;
    USE SIGNAL ;
    PORT
      LAYER M4 ;
        RECT  43.116 35.376 43.2 35.4 ;
    END
  END req_t[33]
  PIN req_t[34]
    DIRECTION OUTPUT ;
    USE SIGNAL ;
    PORT
      LAYER M4 ;
        RECT  43.116 35.472 43.2 35.496 ;
    END
  END req_t[34]
  PIN req_t[35]
    DIRECTION OUTPUT ;
    USE SIGNAL ;
    PORT
      LAYER M4 ;
        RECT  43.116 35.568 43.2 35.592 ;
    END
  END req_t[35]
  PIN req_t[36]
    DIRECTION OUTPUT ;
    USE SIGNAL ;
    PORT
      LAYER M4 ;
        RECT  43.116 35.664 43.2 35.688 ;
    END
  END req_t[36]
  PIN req_t[37]
    DIRECTION OUTPUT ;
    USE SIGNAL ;
    PORT
      LAYER M4 ;
        RECT  43.116 35.76 43.2 35.784 ;
    END
  END req_t[37]
  PIN req_t[38]
    DIRECTION OUTPUT ;
    USE SIGNAL ;
    PORT
      LAYER M4 ;
        RECT  43.116 35.856 43.2 35.88 ;
    END
  END req_t[38]
  PIN req_t[39]
    DIRECTION OUTPUT ;
    USE SIGNAL ;
    PORT
      LAYER M4 ;
        RECT  43.116 35.952 43.2 35.976 ;
    END
  END req_t[39]
  PIN req_t[3]
    DIRECTION OUTPUT ;
    USE SIGNAL ;
    PORT
      LAYER M4 ;
        RECT  43.116 39.408 43.2 39.432 ;
    END
  END req_t[3]
  PIN req_t[40]
    DIRECTION OUTPUT ;
    USE SIGNAL ;
    PORT
      LAYER M4 ;
        RECT  43.116 36.048 43.2 36.072 ;
    END
  END req_t[40]
  PIN req_t[41]
    DIRECTION OUTPUT ;
    USE SIGNAL ;
    PORT
      LAYER M4 ;
        RECT  43.116 36.144 43.2 36.168 ;
    END
  END req_t[41]
  PIN req_t[42]
    DIRECTION OUTPUT ;
    USE SIGNAL ;
    PORT
      LAYER M4 ;
        RECT  43.116 36.24 43.2 36.264 ;
    END
  END req_t[42]
  PIN req_t[43]
    DIRECTION OUTPUT ;
    USE SIGNAL ;
    PORT
      LAYER M4 ;
        RECT  43.116 36.336 43.2 36.36 ;
    END
  END req_t[43]
  PIN req_t[44]
    DIRECTION OUTPUT ;
    USE SIGNAL ;
    PORT
      LAYER M4 ;
        RECT  43.116 36.432 43.2 36.456 ;
    END
  END req_t[44]
  PIN req_t[45]
    DIRECTION OUTPUT ;
    USE SIGNAL ;
    PORT
      LAYER M4 ;
        RECT  43.116 36.528 43.2 36.552 ;
    END
  END req_t[45]
  PIN req_t[46]
    DIRECTION OUTPUT ;
    USE SIGNAL ;
    PORT
      LAYER M4 ;
        RECT  43.116 36.624 43.2 36.648 ;
    END
  END req_t[46]
  PIN req_t[47]
    DIRECTION OUTPUT ;
    USE SIGNAL ;
    PORT
      LAYER M4 ;
        RECT  43.116 36.72 43.2 36.744 ;
    END
  END req_t[47]
  PIN req_t[48]
    DIRECTION OUTPUT ;
    USE SIGNAL ;
    PORT
      LAYER M4 ;
        RECT  43.116 36.816 43.2 36.84 ;
    END
  END req_t[48]
  PIN req_t[49]
    DIRECTION OUTPUT ;
    USE SIGNAL ;
    PORT
      LAYER M4 ;
        RECT  43.116 36.912 43.2 36.936 ;
    END
  END req_t[49]
  PIN req_t[4]
    DIRECTION OUTPUT ;
    USE SIGNAL ;
    PORT
      LAYER M4 ;
        RECT  43.116 39.504 43.2 39.528 ;
    END
  END req_t[4]
  PIN req_t[50]
    DIRECTION OUTPUT ;
    USE SIGNAL ;
    PORT
      LAYER M4 ;
        RECT  43.116 37.008 43.2 37.032 ;
    END
  END req_t[50]
  PIN req_t[51]
    DIRECTION OUTPUT ;
    USE SIGNAL ;
    PORT
      LAYER M4 ;
        RECT  43.116 37.104 43.2 37.128 ;
    END
  END req_t[51]
  PIN req_t[52]
    DIRECTION OUTPUT ;
    USE SIGNAL ;
    PORT
      LAYER M4 ;
        RECT  43.116 37.2 43.2 37.224 ;
    END
  END req_t[52]
  PIN req_t[53]
    DIRECTION OUTPUT ;
    USE SIGNAL ;
    PORT
      LAYER M4 ;
        RECT  43.116 37.296 43.2 37.32 ;
    END
  END req_t[53]
  PIN req_t[54]
    DIRECTION OUTPUT ;
    USE SIGNAL ;
    PORT
      LAYER M4 ;
        RECT  43.116 37.392 43.2 37.416 ;
    END
  END req_t[54]
  PIN req_t[55]
    DIRECTION OUTPUT ;
    USE SIGNAL ;
    PORT
      LAYER M4 ;
        RECT  43.116 37.488 43.2 37.512 ;
    END
  END req_t[55]
  PIN req_t[56]
    DIRECTION OUTPUT ;
    USE SIGNAL ;
    PORT
      LAYER M4 ;
        RECT  43.116 37.584 43.2 37.608 ;
    END
  END req_t[56]
  PIN req_t[57]
    DIRECTION OUTPUT ;
    USE SIGNAL ;
    PORT
      LAYER M4 ;
        RECT  43.116 37.68 43.2 37.704 ;
    END
  END req_t[57]
  PIN req_t[58]
    DIRECTION OUTPUT ;
    USE SIGNAL ;
    PORT
      LAYER M4 ;
        RECT  43.116 37.776 43.2 37.8 ;
    END
  END req_t[58]
  PIN req_t[59]
    DIRECTION OUTPUT ;
    USE SIGNAL ;
    PORT
      LAYER M4 ;
        RECT  43.116 37.872 43.2 37.896 ;
    END
  END req_t[59]
  PIN req_t[5]
    DIRECTION OUTPUT ;
    USE SIGNAL ;
    PORT
      LAYER M4 ;
        RECT  43.116 39.6 43.2 39.624 ;
    END
  END req_t[5]
  PIN req_t[60]
    DIRECTION OUTPUT ;
    USE SIGNAL ;
    PORT
      LAYER M4 ;
        RECT  43.116 37.968 43.2 37.992 ;
    END
  END req_t[60]
  PIN req_t[61]
    DIRECTION OUTPUT ;
    USE SIGNAL ;
    PORT
      LAYER M4 ;
        RECT  43.116 38.064 43.2 38.088 ;
    END
  END req_t[61]
  PIN req_t[62]
    DIRECTION OUTPUT ;
    USE SIGNAL ;
    PORT
      LAYER M4 ;
        RECT  43.116 38.16 43.2 38.184 ;
    END
  END req_t[62]
  PIN req_t[63]
    DIRECTION OUTPUT ;
    USE SIGNAL ;
    PORT
      LAYER M4 ;
        RECT  43.116 38.256 43.2 38.28 ;
    END
  END req_t[63]
  PIN req_t[64]
    DIRECTION OUTPUT ;
    USE SIGNAL ;
    PORT
      LAYER M4 ;
        RECT  43.116 32.208 43.2 32.232 ;
    END
  END req_t[64]
  PIN req_t[65]
    DIRECTION OUTPUT ;
    USE SIGNAL ;
    PORT
      LAYER M4 ;
        RECT  43.116 32.304 43.2 32.328 ;
    END
  END req_t[65]
  PIN req_t[66]
    DIRECTION OUTPUT ;
    USE SIGNAL ;
    PORT
      LAYER M4 ;
        RECT  43.116 32.4 43.2 32.424 ;
    END
  END req_t[66]
  PIN req_t[67]
    DIRECTION OUTPUT ;
    USE SIGNAL ;
    PORT
      LAYER M4 ;
        RECT  43.116 32.496 43.2 32.52 ;
    END
  END req_t[67]
  PIN req_t[68]
    DIRECTION OUTPUT ;
    USE SIGNAL ;
    PORT
      LAYER M4 ;
        RECT  43.116 32.592 43.2 32.616 ;
    END
  END req_t[68]
  PIN req_t[69]
    DIRECTION OUTPUT ;
    USE SIGNAL ;
    PORT
      LAYER M4 ;
        RECT  43.116 32.688 43.2 32.712 ;
    END
  END req_t[69]
  PIN req_t[6]
    DIRECTION OUTPUT ;
    USE SIGNAL ;
    PORT
      LAYER M4 ;
        RECT  43.116 39.696 43.2 39.72 ;
    END
  END req_t[6]
  PIN req_t[70]
    DIRECTION OUTPUT ;
    USE SIGNAL ;
    PORT
      LAYER M4 ;
        RECT  43.116 32.784 43.2 32.808 ;
    END
  END req_t[70]
  PIN req_t[71]
    DIRECTION OUTPUT ;
    USE SIGNAL ;
    PORT
      LAYER M4 ;
        RECT  43.116 32.88 43.2 32.904 ;
    END
  END req_t[71]
  PIN req_t[72]
    DIRECTION OUTPUT ;
    USE SIGNAL ;
    PORT
      LAYER M4 ;
        RECT  43.116 32.976 43.2 33 ;
    END
  END req_t[72]
  PIN req_t[73]
    DIRECTION OUTPUT ;
    USE SIGNAL ;
    PORT
      LAYER M4 ;
        RECT  43.116 33.072 43.2 33.096 ;
    END
  END req_t[73]
  PIN req_t[74]
    DIRECTION OUTPUT ;
    USE SIGNAL ;
    PORT
      LAYER M4 ;
        RECT  43.116 33.168 43.2 33.192 ;
    END
  END req_t[74]
  PIN req_t[75]
    DIRECTION OUTPUT ;
    USE SIGNAL ;
    PORT
      LAYER M4 ;
        RECT  43.116 33.264 43.2 33.288 ;
    END
  END req_t[75]
  PIN req_t[76]
    DIRECTION OUTPUT ;
    USE SIGNAL ;
    PORT
      LAYER M4 ;
        RECT  43.116 33.36 43.2 33.384 ;
    END
  END req_t[76]
  PIN req_t[77]
    DIRECTION OUTPUT ;
    USE SIGNAL ;
    PORT
      LAYER M4 ;
        RECT  43.116 33.456 43.2 33.48 ;
    END
  END req_t[77]
  PIN req_t[78]
    DIRECTION OUTPUT ;
    USE SIGNAL ;
    PORT
      LAYER M4 ;
        RECT  43.116 33.552 43.2 33.576 ;
    END
  END req_t[78]
  PIN req_t[79]
    DIRECTION OUTPUT ;
    USE SIGNAL ;
    PORT
      LAYER M4 ;
        RECT  43.116 33.648 43.2 33.672 ;
    END
  END req_t[79]
  PIN req_t[7]
    DIRECTION OUTPUT ;
    USE SIGNAL ;
    PORT
      LAYER M4 ;
        RECT  43.116 39.792 43.2 39.816 ;
    END
  END req_t[7]
  PIN req_t[80]
    DIRECTION OUTPUT ;
    USE SIGNAL ;
    PORT
      LAYER M4 ;
        RECT  43.116 33.744 43.2 33.768 ;
    END
  END req_t[80]
  PIN req_t[81]
    DIRECTION OUTPUT ;
    USE SIGNAL ;
    PORT
      LAYER M4 ;
        RECT  43.116 33.84 43.2 33.864 ;
    END
  END req_t[81]
  PIN req_t[82]
    DIRECTION OUTPUT ;
    USE SIGNAL ;
    PORT
      LAYER M4 ;
        RECT  43.116 33.936 43.2 33.96 ;
    END
  END req_t[82]
  PIN req_t[83]
    DIRECTION OUTPUT ;
    USE SIGNAL ;
    PORT
      LAYER M4 ;
        RECT  43.116 34.032 43.2 34.056 ;
    END
  END req_t[83]
  PIN req_t[84]
    DIRECTION OUTPUT ;
    USE SIGNAL ;
    PORT
      LAYER M4 ;
        RECT  43.116 34.128 43.2 34.152 ;
    END
  END req_t[84]
  PIN req_t[85]
    DIRECTION OUTPUT ;
    USE SIGNAL ;
    PORT
      LAYER M4 ;
        RECT  43.116 34.224 43.2 34.248 ;
    END
  END req_t[85]
  PIN req_t[86]
    DIRECTION OUTPUT ;
    USE SIGNAL ;
    PORT
      LAYER M4 ;
        RECT  43.116 34.32 43.2 34.344 ;
    END
  END req_t[86]
  PIN req_t[87]
    DIRECTION OUTPUT ;
    USE SIGNAL ;
    PORT
      LAYER M4 ;
        RECT  43.116 34.416 43.2 34.44 ;
    END
  END req_t[87]
  PIN req_t[88]
    DIRECTION OUTPUT ;
    USE SIGNAL ;
    PORT
      LAYER M4 ;
        RECT  43.116 34.512 43.2 34.536 ;
    END
  END req_t[88]
  PIN req_t[89]
    DIRECTION OUTPUT ;
    USE SIGNAL ;
    PORT
      LAYER M4 ;
        RECT  43.116 34.608 43.2 34.632 ;
    END
  END req_t[89]
  PIN req_t[8]
    DIRECTION OUTPUT ;
    USE SIGNAL ;
    PORT
      LAYER M4 ;
        RECT  43.116 39.888 43.2 39.912 ;
    END
  END req_t[8]
  PIN req_t[90]
    DIRECTION OUTPUT ;
    USE SIGNAL ;
    PORT
      LAYER M4 ;
        RECT  43.116 34.704 43.2 34.728 ;
    END
  END req_t[90]
  PIN req_t[91]
    DIRECTION OUTPUT ;
    USE SIGNAL ;
    PORT
      LAYER M4 ;
        RECT  43.116 34.8 43.2 34.824 ;
    END
  END req_t[91]
  PIN req_t[92]
    DIRECTION OUTPUT ;
    USE SIGNAL ;
    PORT
      LAYER M4 ;
        RECT  43.116 34.896 43.2 34.92 ;
    END
  END req_t[92]
  PIN req_t[93]
    DIRECTION OUTPUT ;
    USE SIGNAL ;
    PORT
      LAYER M4 ;
        RECT  43.116 34.992 43.2 35.016 ;
    END
  END req_t[93]
  PIN req_t[94]
    DIRECTION OUTPUT ;
    USE SIGNAL ;
    PORT
      LAYER M4 ;
        RECT  43.116 35.088 43.2 35.112 ;
    END
  END req_t[94]
  PIN req_t[95]
    DIRECTION OUTPUT ;
    USE SIGNAL ;
    PORT
      LAYER M4 ;
        RECT  43.116 35.184 43.2 35.208 ;
    END
  END req_t[95]
  PIN req_t[96]
    DIRECTION OUTPUT ;
    USE SIGNAL ;
    PORT
      LAYER M4 ;
        RECT  43.116 29.136 43.2 29.16 ;
    END
  END req_t[96]
  PIN req_t[97]
    DIRECTION OUTPUT ;
    USE SIGNAL ;
    PORT
      LAYER M4 ;
        RECT  43.116 29.232 43.2 29.256 ;
    END
  END req_t[97]
  PIN req_t[98]
    DIRECTION OUTPUT ;
    USE SIGNAL ;
    PORT
      LAYER M4 ;
        RECT  43.116 29.328 43.2 29.352 ;
    END
  END req_t[98]
  PIN req_t[99]
    DIRECTION OUTPUT ;
    USE SIGNAL ;
    PORT
      LAYER M4 ;
        RECT  43.116 29.424 43.2 29.448 ;
    END
  END req_t[99]
  PIN req_t[9]
    DIRECTION OUTPUT ;
    USE SIGNAL ;
    PORT
      LAYER M4 ;
        RECT  43.116 39.984 43.2 40.008 ;
    END
  END req_t[9]
  PIN req_valid[0]
    DIRECTION OUTPUT ;
    USE SIGNAL ;
    PORT
      LAYER M4 ;
        RECT  43.116 30.672 43.2 30.696 ;
    END
  END req_valid[0]
  PIN req_valid[1]
    DIRECTION OUTPUT ;
    USE SIGNAL ;
    PORT
      LAYER M4 ;
        RECT  43.116 30.768 43.2 30.792 ;
    END
  END req_valid[1]
  PIN req_valid[2]
    DIRECTION OUTPUT ;
    USE SIGNAL ;
    PORT
      LAYER M4 ;
        RECT  43.116 30.864 43.2 30.888 ;
    END
  END req_valid[2]
  PIN req_valid[3]
    DIRECTION OUTPUT ;
    USE SIGNAL ;
    PORT
      LAYER M4 ;
        RECT  43.116 30.96 43.2 30.984 ;
    END
  END req_valid[3]
  PIN req_valid[4]
    DIRECTION OUTPUT ;
    USE SIGNAL ;
    PORT
      LAYER M4 ;
        RECT  43.116 31.056 43.2 31.08 ;
    END
  END req_valid[4]
  PIN req_valid[5]
    DIRECTION OUTPUT ;
    USE SIGNAL ;
    PORT
      LAYER M4 ;
        RECT  43.116 31.152 43.2 31.176 ;
    END
  END req_valid[5]
  PIN req_valid[6]
    DIRECTION OUTPUT ;
    USE SIGNAL ;
    PORT
      LAYER M4 ;
        RECT  43.116 31.248 43.2 31.272 ;
    END
  END req_valid[6]
  PIN req_valid[7]
    DIRECTION OUTPUT ;
    USE SIGNAL ;
    PORT
      LAYER M4 ;
        RECT  43.116 31.344 43.2 31.368 ;
    END
  END req_valid[7]
  PIN rst_n
    DIRECTION INPUT ;
    USE SIGNAL ;
    PORT
      LAYER M5 ;
        RECT  16.272 0 16.296 0.084 ;
    END
  END rst_n
  PIN start
    DIRECTION INPUT ;
    USE SIGNAL ;
    PORT
      LAYER M5 ;
        RECT  16.368 0 16.392 0.084 ;
    END
  END start
  PIN VDD
    DIRECTION INOUT ;
    USE POWER ;
    PORT
      LAYER M5 ;
        RECT  40.392 2.151 40.512 41.049 ;
        RECT  34.992 2.151 35.112 41.049 ;
        RECT  29.592 2.151 29.712 41.049 ;
        RECT  24.192 2.151 24.312 41.049 ;
        RECT  18.792 2.151 18.912 41.049 ;
        RECT  13.392 2.151 13.512 41.049 ;
        RECT  7.992 2.151 8.112 41.049 ;
        RECT  2.592 2.151 2.712 41.049 ;
    END
  END VDD
  PIN VSS
    DIRECTION INOUT ;
    USE GROUND ;
    PORT
      LAYER M5 ;
        RECT  40.2 2.137 40.32 41.063 ;
        RECT  34.8 2.137 34.92 41.063 ;
        RECT  29.4 2.137 29.52 41.063 ;
        RECT  24 2.137 24.12 41.063 ;
        RECT  18.6 2.137 18.72 41.063 ;
        RECT  13.2 2.137 13.32 41.063 ;
        RECT  7.8 2.137 7.92 41.063 ;
        RECT  2.4 2.137 2.52 41.063 ;
    END
  END VSS
  # OT_OBS_CLOSED layer=M5 d_um=1.536 added=119
  OBS
    LAYER RVTN ;
     RECT  2.16 2.16 41.04 2.295 ;
     RECT  2.16 2.565 41.04 2.835 ;
     RECT  2.16 3.105 41.04 3.375 ;
     RECT  2.16 3.645 41.04 3.915 ;
     RECT  2.16 4.185 41.04 4.455 ;
     RECT  2.16 4.725 41.04 4.995 ;
     RECT  2.16 5.265 41.04 5.535 ;
     RECT  2.16 5.805 41.04 6.075 ;
     RECT  2.16 6.345 41.04 6.615 ;
     RECT  2.16 6.885 41.04 7.155 ;
     RECT  2.16 7.425 41.04 7.695 ;
     RECT  2.16 7.965 41.04 8.235 ;
     RECT  2.16 8.505 41.04 8.775 ;
     RECT  2.16 9.045 41.04 9.315 ;
     RECT  2.16 9.585 41.04 9.855 ;
     RECT  2.16 10.125 41.04 10.395 ;
     RECT  2.16 10.665 41.04 10.935 ;
     RECT  2.16 11.205 41.04 11.475 ;
     RECT  2.16 11.745 41.04 12.015 ;
     RECT  2.16 12.285 41.04 12.555 ;
     RECT  2.16 12.825 41.04 13.095 ;
     RECT  2.16 13.365 41.04 13.635 ;
     RECT  2.16 13.905 41.04 14.175 ;
     RECT  2.16 14.445 41.04 14.715 ;
     RECT  2.16 14.985 41.04 15.255 ;
     RECT  2.16 15.525 41.04 15.795 ;
     RECT  2.16 16.065 41.04 16.335 ;
     RECT  2.16 16.605 41.04 16.875 ;
     RECT  2.16 17.145 41.04 17.415 ;
     RECT  2.16 17.685 41.04 17.955 ;
     RECT  2.16 18.225 41.04 18.495 ;
     RECT  2.16 18.765 41.04 19.035 ;
     RECT  2.16 19.305 41.04 19.575 ;
     RECT  2.16 19.845 41.04 20.115 ;
     RECT  2.16 20.385 41.04 20.655 ;
     RECT  2.16 20.925 41.04 21.195 ;
     RECT  2.16 21.465 41.04 21.735 ;
     RECT  2.16 22.005 41.04 22.275 ;
     RECT  2.16 22.545 41.04 22.815 ;
     RECT  2.16 23.085 41.04 23.355 ;
     RECT  2.16 23.625 41.04 23.895 ;
     RECT  2.16 24.165 41.04 24.435 ;
     RECT  2.16 24.705 41.04 24.975 ;
     RECT  2.16 25.245 41.04 25.515 ;
     RECT  2.16 25.785 41.04 26.055 ;
     RECT  2.16 26.325 41.04 26.595 ;
     RECT  2.16 26.865 41.04 27.135 ;
     RECT  2.16 27.405 41.04 27.675 ;
     RECT  2.16 27.945 41.04 28.215 ;
     RECT  2.16 28.485 41.04 28.755 ;
     RECT  2.16 29.025 41.04 29.295 ;
     RECT  2.16 29.565 41.04 29.835 ;
     RECT  2.16 30.105 41.04 30.375 ;
     RECT  2.16 30.645 41.04 30.915 ;
     RECT  2.16 31.185 41.04 31.455 ;
     RECT  2.16 31.725 41.04 31.995 ;
     RECT  2.16 32.265 41.04 32.535 ;
     RECT  2.16 32.805 41.04 33.075 ;
     RECT  2.16 33.345 41.04 33.615 ;
     RECT  2.16 33.885 41.04 34.155 ;
     RECT  2.16 34.425 41.04 34.695 ;
     RECT  2.16 34.965 41.04 35.235 ;
     RECT  2.16 35.505 41.04 35.775 ;
     RECT  2.16 36.045 41.04 36.315 ;
     RECT  2.16 36.585 41.04 36.855 ;
     RECT  2.16 37.125 41.04 37.395 ;
     RECT  2.16 37.665 41.04 37.935 ;
     RECT  2.16 38.205 41.04 38.475 ;
     RECT  2.16 38.745 41.04 39.015 ;
     RECT  2.16 39.285 41.04 39.555 ;
     RECT  2.16 39.825 41.04 40.095 ;
     RECT  2.16 40.365 41.04 40.635 ;
     RECT  2.16 40.905 41.04 41.04 ;
    LAYER RVTP ;
     RECT  2.16 2.295 41.04 2.565 ;
     RECT  2.16 2.835 41.04 3.105 ;
     RECT  2.16 3.375 41.04 3.645 ;
     RECT  2.16 3.915 41.04 4.185 ;
     RECT  2.16 4.455 41.04 4.725 ;
     RECT  2.16 4.995 41.04 5.265 ;
     RECT  2.16 5.535 41.04 5.805 ;
     RECT  2.16 6.075 41.04 6.345 ;
     RECT  2.16 6.615 41.04 6.885 ;
     RECT  2.16 7.155 41.04 7.425 ;
     RECT  2.16 7.695 41.04 7.965 ;
     RECT  2.16 8.235 41.04 8.505 ;
     RECT  2.16 8.775 41.04 9.045 ;
     RECT  2.16 9.315 41.04 9.585 ;
     RECT  2.16 9.855 41.04 10.125 ;
     RECT  2.16 10.395 41.04 10.665 ;
     RECT  2.16 10.935 41.04 11.205 ;
     RECT  2.16 11.475 41.04 11.745 ;
     RECT  2.16 12.015 41.04 12.285 ;
     RECT  2.16 12.555 41.04 12.825 ;
     RECT  2.16 13.095 41.04 13.365 ;
     RECT  2.16 13.635 41.04 13.905 ;
     RECT  2.16 14.175 41.04 14.445 ;
     RECT  2.16 14.715 41.04 14.985 ;
     RECT  2.16 15.255 41.04 15.525 ;
     RECT  2.16 15.795 41.04 16.065 ;
     RECT  2.16 16.335 41.04 16.605 ;
     RECT  2.16 16.875 41.04 17.145 ;
     RECT  2.16 17.415 41.04 17.685 ;
     RECT  2.16 17.955 41.04 18.225 ;
     RECT  2.16 18.495 41.04 18.765 ;
     RECT  2.16 19.035 41.04 19.305 ;
     RECT  2.16 19.575 41.04 19.845 ;
     RECT  2.16 20.115 41.04 20.385 ;
     RECT  2.16 20.655 41.04 20.925 ;
     RECT  2.16 21.195 41.04 21.465 ;
     RECT  2.16 21.735 41.04 22.005 ;
     RECT  2.16 22.275 41.04 22.545 ;
     RECT  2.16 22.815 41.04 23.085 ;
     RECT  2.16 23.355 41.04 23.625 ;
     RECT  2.16 23.895 41.04 24.165 ;
     RECT  2.16 24.435 41.04 24.705 ;
     RECT  2.16 24.975 41.04 25.245 ;
     RECT  2.16 25.515 41.04 25.785 ;
     RECT  2.16 26.055 41.04 26.325 ;
     RECT  2.16 26.595 41.04 26.865 ;
     RECT  2.16 27.135 41.04 27.405 ;
     RECT  2.16 27.675 41.04 27.945 ;
     RECT  2.16 28.215 41.04 28.485 ;
     RECT  2.16 28.755 41.04 29.025 ;
     RECT  2.16 29.295 41.04 29.565 ;
     RECT  2.16 29.835 41.04 30.105 ;
     RECT  2.16 30.375 41.04 30.645 ;
     RECT  2.16 30.915 41.04 31.185 ;
     RECT  2.16 31.455 41.04 31.725 ;
     RECT  2.16 31.995 41.04 32.265 ;
     RECT  2.16 32.535 41.04 32.805 ;
     RECT  2.16 33.075 41.04 33.345 ;
     RECT  2.16 33.615 41.04 33.885 ;
     RECT  2.16 34.155 41.04 34.425 ;
     RECT  2.16 34.695 41.04 34.965 ;
     RECT  2.16 35.235 41.04 35.505 ;
     RECT  2.16 35.775 41.04 36.045 ;
     RECT  2.16 36.315 41.04 36.585 ;
     RECT  2.16 36.855 41.04 37.125 ;
     RECT  2.16 37.395 41.04 37.665 ;
     RECT  2.16 37.935 41.04 38.205 ;
     RECT  2.16 38.475 41.04 38.745 ;
     RECT  2.16 39.015 41.04 39.285 ;
     RECT  2.16 39.555 41.04 39.825 ;
     RECT  2.16 40.095 41.04 40.365 ;
     RECT  2.16 40.635 41.04 40.905 ;
    LAYER M1 ;
     RECT  2.16 2.151 41.04 41.049 ;
    LAYER M2 ;
     RECT  0.103 4.23 0.175 4.248 ;
     RECT  0.103 7.776 0.175 7.794 ;
     RECT  0.103 14.958 0.175 14.976 ;
     RECT  0.103 22.05 0.175 22.068 ;
     RECT  0.103 5.661 0.211 5.868 ;
     RECT  0.103 6.822 0.211 6.84 ;
     RECT  0.139 11.952 0.211 11.97 ;
     RECT  0.211 5.661 0.239 6.84 ;
     RECT  0.175 3.996 0.247 4.248 ;
     RECT  0.175 14.652 0.247 14.976 ;
     RECT  0.247 3.996 0.283 4.284 ;
     RECT  0.103 15.876 0.347 16.398 ;
     RECT  0.175 21.978 0.347 22.068 ;
     RECT  0.247 14.526 0.383 14.976 ;
     RECT  0.103 9.9 0.499 9.918 ;
     RECT  0.175 7.776 0.535 8.298 ;
     RECT  0.499 9.36 0.535 9.918 ;
     RECT  0.103 19.62 0.535 19.638 ;
     RECT  0.211 2.808 1.147 2.826 ;
     RECT  0.535 24.48 1.147 24.498 ;
     RECT  1.147 2.808 1.183 3.06 ;
     RECT  0.283 3.996 1.183 4.554 ;
     RECT  1.183 2.808 1.399 4.554 ;
     RECT  0.239 5.742 1.399 6.84 ;
     RECT  1.399 2.808 1.687 6.84 ;
     RECT  1.687 2.772 1.723 6.84 ;
     RECT  0.211 11.25 1.723 11.97 ;
     RECT  0.103 13.68 1.723 13.698 ;
     RECT  0.383 14.526 1.723 14.67 ;
     RECT  0.347 16.38 1.723 16.398 ;
     RECT  0.103 17.622 1.723 17.64 ;
     RECT  1.723 16.38 1.759 17.64 ;
     RECT  1.723 18.576 1.759 18.594 ;
     RECT  1.723 2.268 2.16 6.84 ;
     RECT  0.535 7.776 2.16 9.918 ;
     RECT  1.723 11.25 2.16 12.546 ;
     RECT  1.723 13.68 2.16 14.67 ;
     RECT  1.759 16.38 2.16 18.594 ;
     RECT  0.535 19.584 2.16 19.638 ;
     RECT  0.347 21.978 2.16 21.996 ;
     RECT  1.147 24.48 2.16 25.2 ;
     RECT  2.16 2.151 2.299 41.049 ;
     RECT  2.299 1.926 4.199 41.049 ;
     RECT  4.199 2.034 5.035 41.049 ;
     RECT  5.035 1.962 5.927 41.049 ;
     RECT  5.927 2.034 6.863 41.049 ;
     RECT  6.863 2.106 7.627 41.049 ;
     RECT  7.627 2.034 12.587 41.049 ;
     RECT  12.587 2.151 19.399 41.049 ;
     RECT  19.399 2.106 21.551 41.049 ;
     RECT  21.551 2.151 22.495 41.049 ;
     RECT  22.495 2.034 23.935 41.049 ;
     RECT  23.935 1.998 24.007 41.049 ;
     RECT  24.007 1.881 25.943 41.049 ;
     RECT  25.943 2.151 26.743 41.049 ;
     RECT  26.743 2.151 29.111 41.319 ;
     RECT  29.111 2.151 41.04 41.049 ;
     RECT  41.04 26.406 41.567 37.152 ;
     RECT  41.567 35.01 41.603 37.152 ;
     RECT  41.567 26.406 41.639 34.074 ;
     RECT  41.603 35.01 41.639 36.306 ;
     RECT  41.04 40.644 41.639 40.824 ;
     RECT  41.639 26.406 41.891 31.788 ;
     RECT  41.04 38.556 41.927 39.276 ;
     RECT  41.891 26.604 41.999 31.788 ;
     RECT  41.639 36.126 41.999 36.306 ;
     RECT  41.927 38.718 42.035 39.276 ;
     RECT  41.603 37.134 42.179 37.152 ;
     RECT  41.639 40.68 42.179 40.824 ;
     RECT  41.999 27.684 42.215 31.788 ;
     RECT  42.179 40.68 42.215 40.698 ;
     RECT  41.639 33.012 42.331 34.074 ;
     RECT  41.639 35.01 42.331 35.334 ;
     RECT  42.215 27.684 42.359 31.68 ;
     RECT  42.359 27.684 42.503 30.942 ;
     RECT  42.503 30.186 42.719 30.942 ;
     RECT  41.999 36.216 42.755 36.306 ;
     RECT  42.719 30.654 42.899 30.942 ;
     RECT  42.331 33.012 42.899 35.334 ;
     RECT  42.035 39.258 42.907 39.276 ;
     RECT  41.999 26.604 42.971 26.622 ;
     RECT  42.899 33.012 42.971 33.57 ;
     RECT  42.971 33.012 43.007 33.489 ;
     RECT  42.899 34.776 43.007 35.334 ;
     RECT  42.835 36.594 43.007 36.612 ;
     RECT  42.907 39.186 43.007 39.276 ;
     RECT  42.503 27.684 43.043 29.286 ;
     RECT  43.043 27.684 43.079 29.052 ;
     RECT  43.007 33.012 43.079 33.03 ;
     RECT  43.079 27.684 43.115 27.702 ;
     RECT  42.899 30.654 43.151 30.672 ;
     RECT  43.015 39.411 43.151 39.429 ;
     RECT  43.079 29.034 43.187 29.052 ;
     RECT  43.087 41.49 43.187 41.508 ;
    LAYER M3 ;
     RECT  16.632 0.091 16.65 0.139 ;
     RECT  19.872 0.091 19.89 0.139 ;
     RECT  20.664 0.091 22.554 0.139 ;
     RECT  12.996 0.091 13.95 0.283 ;
     RECT  12.672 0.283 13.95 0.413 ;
     RECT  19.62 0.139 19.89 0.523 ;
     RECT  20.664 0.139 22.662 0.523 ;
     RECT  19.584 0.523 19.89 0.571 ;
     RECT  20.628 0.523 22.662 0.571 ;
     RECT  12.672 0.413 13.59 0.653 ;
     RECT  19.584 0.571 22.662 1.147 ;
     RECT  1.98 1.003 1.998 1.195 ;
     RECT  0.108 1.099 0.126 1.387 ;
     RECT  3.168 1.291 3.186 1.483 ;
     RECT  1.764 1.195 1.998 1.675 ;
     RECT  12.672 0.653 13.194 1.723 ;
     RECT  14.184 1.147 14.202 1.723 ;
     RECT  14.94 0.091 14.958 1.723 ;
     RECT  16.632 0.139 17.19 1.723 ;
     RECT  19.512 1.147 22.662 1.723 ;
     RECT  24.012 1.771 24.03 1.819 ;
     RECT  3.168 1.483 3.438 1.867 ;
     RECT  23.94 1.819 24.03 1.867 ;
     RECT  1.152 1.675 1.998 1.921 ;
     RECT  2.736 1.867 3.438 1.921 ;
     RECT  25.92 1.876 25.938 1.921 ;
     RECT  6.192 1.579 6.21 1.957 ;
     RECT  1.152 1.921 3.438 1.963 ;
     RECT  4.176 1.921 4.194 1.963 ;
     RECT  25.632 1.921 25.938 1.993 ;
     RECT  5.04 1.957 5.058 2.029 ;
     RECT  5.904 1.957 6.21 2.029 ;
     RECT  12.672 1.723 17.37 2.029 ;
     RECT  1.152 1.963 4.194 2.101 ;
     RECT  5.04 2.029 6.858 2.101 ;
     RECT  19.512 1.723 22.734 2.101 ;
     RECT  23.94 1.867 24.534 2.101 ;
     RECT  25.38 1.993 25.938 2.101 ;
     RECT  7.632 2.029 7.65 2.143 ;
     RECT  19.404 2.101 22.734 2.143 ;
     RECT  7.632 2.143 7.905 2.191 ;
     RECT  9.036 2.101 9.054 2.191 ;
     RECT  18.615 2.143 22.734 2.191 ;
     RECT  9.036 2.191 9.162 2.227 ;
     RECT  12.564 2.029 17.37 2.263 ;
     RECT  18.468 2.191 22.734 2.263 ;
     RECT  23.544 2.101 25.938 2.263 ;
     RECT  12.276 2.263 17.37 2.299 ;
     RECT  1.152 2.101 6.858 2.347 ;
     RECT  7.632 2.191 8.19 2.347 ;
     RECT  8.964 2.227 9.162 2.371 ;
     RECT  12.276 2.299 17.694 2.371 ;
     RECT  18.468 2.263 25.938 2.371 ;
     RECT  29.415 2.143 29.505 2.413 ;
     RECT  34.815 2.143 34.905 2.413 ;
     RECT  40.215 2.143 40.305 2.413 ;
     RECT  0.108 1.387 0.27 2.443 ;
     RECT  1.152 2.347 8.19 2.443 ;
     RECT  8.928 2.371 9.162 2.443 ;
     RECT  0.108 2.443 0.342 2.573 ;
     RECT  11.772 2.371 25.938 2.605 ;
     RECT  1.152 2.443 9.594 2.641 ;
     RECT  11.772 2.605 26.334 2.641 ;
     RECT  11.772 2.641 26.658 2.731 ;
     RECT  11.664 2.731 26.658 2.759 ;
     RECT  1.152 2.641 10.458 3.065 ;
     RECT  11.664 2.759 26.37 3.109 ;
     RECT  1.188 3.065 10.458 3.145 ;
     RECT  11.196 3.109 26.37 3.145 ;
     RECT  1.188 3.145 26.37 3.569 ;
     RECT  0.108 2.573 0.27 3.787 ;
     RECT  0.108 3.787 0.342 3.917 ;
     RECT  1.188 3.569 26.226 3.983 ;
     RECT  1.188 3.983 26.118 3.991 ;
     RECT  1.152 3.991 26.118 4.217 ;
     RECT  0.108 3.917 0.306 4.253 ;
     RECT  0.252 4.253 0.306 4.289 ;
     RECT  1.692 4.217 26.118 4.991 ;
     RECT  1.692 4.991 24.786 5.035 ;
     RECT  1.404 5.035 24.786 5.069 ;
     RECT  0.288 4.289 0.306 5.131 ;
     RECT  0.288 5.131 0.342 5.323 ;
     RECT  0.288 5.323 0.414 5.419 ;
     RECT  0.216 5.419 0.414 5.549 ;
     RECT  0.216 5.549 0.306 5.611 ;
     RECT  25.524 4.991 26.118 5.729 ;
     RECT  0.108 5.611 0.306 5.741 ;
     RECT  2.304 5.069 24.786 5.755 ;
     RECT  25.524 5.729 25.542 5.755 ;
     RECT  2.304 5.755 25.542 5.765 ;
     RECT  2.304 5.765 25.362 6.449 ;
     RECT  0.108 5.741 0.234 6.475 ;
     RECT  0.108 6.475 0.342 6.583 ;
     RECT  0.108 6.583 0.558 6.764 ;
     RECT  2.304 6.449 24.498 6.817 ;
     RECT  25.344 6.449 25.362 6.845 ;
     RECT  0.108 6.764 0.234 6.893 ;
     RECT  2.232 6.817 24.498 6.917 ;
     RECT  2.268 6.917 24.498 7.195 ;
     RECT  0.108 6.893 0.126 7.627 ;
     RECT  1.404 5.069 1.422 8.011 ;
     RECT  2.268 7.195 24.858 8.011 ;
     RECT  1.404 8.011 24.858 8.333 ;
     RECT  25.596 8.203 25.614 8.429 ;
     RECT  1.728 8.333 24.858 8.437 ;
     RECT  0.108 7.627 0.342 8.509 ;
     RECT  0.108 8.509 0.558 8.525 ;
     RECT  1.728 8.437 25.146 8.573 ;
     RECT  2.268 8.573 25.146 8.735 ;
     RECT  2.304 8.735 25.038 8.969 ;
     RECT  0.18 8.525 0.558 9.499 ;
     RECT  2.304 8.969 24.858 9.751 ;
     RECT  2.304 9.751 24.894 9.787 ;
     RECT  0.144 9.499 0.558 9.895 ;
     RECT  2.304 9.787 25.074 9.895 ;
     RECT  0.108 9.895 0.558 10.123 ;
     RECT  2.304 9.895 25.218 10.129 ;
     RECT  26.208 9.823 26.226 10.165 ;
     RECT  2.304 10.129 25.326 10.201 ;
     RECT  26.208 10.165 26.334 10.201 ;
     RECT  0.108 10.123 0.63 10.253 ;
     RECT  2.304 10.201 26.334 10.411 ;
     RECT  2.196 10.411 26.334 10.471 ;
     RECT  2.196 10.471 26.37 10.705 ;
     RECT  2.196 10.705 26.55 10.939 ;
     RECT  2.196 10.939 26.766 10.975 ;
     RECT  0.108 10.253 0.162 11.245 ;
     RECT  2.196 10.975 26.838 11.275 ;
     RECT  1.728 11.275 26.838 11.551 ;
     RECT  1.728 11.551 27.162 11.677 ;
     RECT  1.728 11.677 27.414 11.821 ;
     RECT  1.728 11.821 27.522 12.047 ;
     RECT  0.108 11.245 0.234 12.427 ;
     RECT  25.74 12.047 27.522 12.829 ;
     RECT  1.728 12.047 24.894 12.901 ;
     RECT  25.704 12.829 27.522 12.901 ;
     RECT  1.728 12.901 28.242 13.147 ;
     RECT  0.108 12.427 0.342 13.325 ;
     RECT  0.108 13.325 0.27 13.703 ;
     RECT  1.152 13.147 28.242 13.973 ;
     RECT  2.304 13.973 28.242 13.981 ;
     RECT  1.152 13.973 1.17 14.141 ;
     RECT  0.144 13.703 0.27 14.539 ;
     RECT  2.304 13.981 28.386 14.639 ;
     RECT  0.144 14.539 0.342 14.923 ;
     RECT  0.108 14.923 0.342 14.953 ;
     RECT  0.108 14.953 0.378 14.981 ;
     RECT  0.144 14.981 0.378 15.053 ;
     RECT  2.304 14.639 25.938 15.187 ;
     RECT  2.268 15.187 25.938 15.403 ;
     RECT  1.728 15.403 25.938 15.451 ;
     RECT  26.748 14.639 28.386 15.451 ;
     RECT  0.144 15.053 0.342 15.871 ;
     RECT  0.108 15.871 0.342 15.899 ;
     RECT  1.728 15.451 28.386 16.555 ;
     RECT  0.108 15.899 0.126 16.589 ;
     RECT  0.144 16.747 0.342 16.877 ;
     RECT  1.152 16.555 28.386 16.925 ;
     RECT  0.144 16.877 0.162 17.357 ;
     RECT  1.728 16.925 28.386 18.157 ;
     RECT  0.108 17.617 0.126 18.317 ;
     RECT  1.728 18.157 28.494 18.599 ;
     RECT  2.196 18.599 28.494 18.761 ;
     RECT  0.54 19.579 0.558 19.615 ;
     RECT  0.108 19.615 0.558 20.045 ;
     RECT  0.108 20.045 0.126 20.237 ;
     RECT  2.196 18.761 28.458 20.723 ;
     RECT  2.304 20.723 28.458 21.091 ;
     RECT  2.304 21.091 28.494 21.271 ;
     RECT  29.415 2.413 29.697 21.271 ;
     RECT  0.144 20.923 0.162 21.403 ;
     RECT  0.144 21.403 0.234 21.643 ;
     RECT  0.144 21.643 0.342 21.931 ;
     RECT  0.108 21.931 0.342 22.073 ;
     RECT  2.304 21.271 29.697 22.123 ;
     RECT  30.672 22.171 30.69 22.243 ;
     RECT  34.815 2.413 35.097 22.351 ;
     RECT  0.18 22.073 0.198 22.445 ;
     RECT  2.268 22.123 29.697 23.08 ;
     RECT  2.196 23.08 29.697 23.117 ;
     RECT  32.724 19.543 32.742 23.125 ;
     RECT  2.304 23.117 29.697 23.521 ;
     RECT  30.6 22.243 30.69 23.521 ;
     RECT  2.304 23.521 30.69 23.557 ;
     RECT  2.304 23.557 31.086 23.585 ;
     RECT  11.52 23.585 31.086 23.701 ;
     RECT  11.52 23.701 31.302 23.819 ;
     RECT  32.58 23.125 32.742 24.205 ;
     RECT  2.304 23.585 10.746 24.235 ;
     RECT  11.844 23.819 31.302 24.241 ;
     RECT  32.364 24.205 32.742 24.241 ;
     RECT  2.268 24.235 10.746 24.467 ;
     RECT  0.144 24.331 0.162 24.475 ;
     RECT  1.152 23.179 1.17 24.475 ;
     RECT  11.844 24.241 32.85 24.503 ;
     RECT  14.256 24.503 32.85 24.637 ;
     RECT  0.144 24.475 1.17 24.653 ;
     RECT  2.304 24.467 10.746 24.709 ;
     RECT  14.256 24.637 33.21 24.781 ;
     RECT  2.304 24.709 10.854 24.809 ;
     RECT  0.144 24.653 0.162 24.845 ;
     RECT  14.256 24.781 33.678 24.935 ;
     RECT  14.256 24.935 32.886 25.007 ;
     RECT  33.66 24.935 33.678 25.043 ;
     RECT  14.832 25.007 32.886 25.079 ;
     RECT  1.152 24.653 1.17 25.205 ;
     RECT  15.516 25.079 32.886 25.241 ;
     RECT  2.304 24.809 10.602 25.313 ;
     RECT  2.304 25.313 9.522 25.387 ;
     RECT  2.268 25.387 9.522 25.547 ;
     RECT  10.548 25.313 10.602 25.789 ;
     RECT  10.548 25.789 10.818 25.889 ;
     RECT  11.844 24.503 13.497 25.889 ;
     RECT  0.324 25.675 0.342 26.059 ;
     RECT  0.144 26.059 0.342 26.093 ;
     RECT  0.144 26.093 0.162 26.237 ;
     RECT  2.304 25.547 9.522 26.249 ;
     RECT  10.584 25.889 10.602 26.519 ;
     RECT  2.304 26.249 8.838 26.555 ;
     RECT  2.304 26.555 8.766 26.627 ;
     RECT  41.868 26.401 41.886 26.671 ;
     RECT  11.844 25.889 11.862 26.789 ;
     RECT  15.516 25.241 32.742 26.797 ;
     RECT  2.304 26.627 6.93 26.825 ;
     RECT  2.376 26.825 6.93 26.909 ;
     RECT  41.436 26.671 41.886 26.941 ;
     RECT  15.516 26.797 32.922 27.031 ;
     RECT  41.292 26.941 41.886 27.031 ;
     RECT  40.215 2.413 40.497 27.103 ;
     RECT  41.292 27.031 41.994 27.103 ;
     RECT  2.376 26.909 6.858 27.131 ;
     RECT  15.516 27.031 33.57 27.175 ;
     RECT  2.376 27.131 6.534 27.203 ;
     RECT  40.215 27.103 41.994 27.301 ;
     RECT  2.376 27.203 6.246 27.329 ;
     RECT  7.776 26.627 8.766 27.329 ;
     RECT  40.068 27.301 41.994 27.337 ;
     RECT  15.156 27.175 33.57 27.365 ;
     RECT  12.6 25.889 13.497 27.509 ;
     RECT  7.776 27.329 8.097 27.599 ;
     RECT  2.415 27.329 6.246 27.635 ;
     RECT  15.408 27.365 33.57 27.635 ;
     RECT  42.948 26.599 42.966 27.679 ;
     RECT  39.636 27.337 41.994 27.751 ;
     RECT  2.415 27.635 5.094 27.905 ;
     RECT  5.976 27.635 6.246 27.905 ;
     RECT  2.415 27.905 4.914 27.917 ;
     RECT  15.408 27.635 32.922 27.917 ;
     RECT  3.96 27.917 3.978 27.941 ;
     RECT  6.228 27.905 6.246 27.941 ;
     RECT  38.88 27.751 41.994 28.021 ;
     RECT  42.948 27.679 43.11 28.021 ;
     RECT  4.896 27.917 4.914 28.049 ;
     RECT  38.88 28.021 43.11 28.651 ;
     RECT  15.516 27.917 32.922 28.759 ;
     RECT  38.484 28.651 43.11 28.795 ;
     RECT  34.416 22.351 35.097 28.921 ;
     RECT  37.368 28.723 37.386 28.921 ;
     RECT  37.152 28.921 37.386 28.993 ;
     RECT  38.34 28.795 43.11 28.993 ;
     RECT  37.044 28.993 43.11 29.029 ;
     RECT  35.928 28.939 35.946 29.065 ;
     RECT  35.928 29.065 36.018 29.101 ;
     RECT  37.044 29.029 43.182 29.191 ;
     RECT  34.38 28.921 35.097 29.227 ;
     RECT  35.856 29.101 36.018 29.227 ;
     RECT  15.516 28.759 33.138 29.371 ;
     RECT  34.38 29.227 36.018 29.371 ;
     RECT  37.008 29.191 43.182 29.371 ;
     RECT  15.516 29.371 36.018 29.767 ;
     RECT  36.936 29.371 43.182 29.767 ;
     RECT  15.516 29.767 43.182 30.569 ;
     RECT  15.516 30.569 22.446 31.621 ;
     RECT  23.472 30.569 43.182 31.621 ;
     RECT  15.516 31.621 43.182 31.793 ;
     RECT  15.516 31.793 22.446 31.829 ;
     RECT  15.516 31.829 21.078 31.919 ;
     RECT  22.068 31.829 22.446 31.919 ;
     RECT  23.544 31.793 43.182 32.225 ;
     RECT  23.544 32.225 24.966 32.261 ;
     RECT  25.704 32.225 43.182 32.369 ;
     RECT  25.776 32.369 25.866 32.459 ;
     RECT  23.544 32.261 24.822 32.495 ;
     RECT  25.848 32.459 25.866 32.495 ;
     RECT  22.212 31.919 22.446 32.539 ;
     RECT  23.544 32.495 24.462 32.539 ;
     RECT  22.212 32.539 24.462 32.729 ;
     RECT  22.212 32.729 22.59 32.845 ;
     RECT  15.516 31.919 21.006 32.881 ;
     RECT  21.96 32.845 22.59 32.881 ;
     RECT  26.64 32.369 43.182 33.053 ;
     RECT  15.516 32.881 22.59 33.293 ;
     RECT  15.912 33.293 22.59 33.449 ;
     RECT  15.912 33.449 22.338 33.809 ;
     RECT  15.912 33.809 21.762 33.845 ;
     RECT  15.912 33.845 20.61 34.187 ;
     RECT  21.672 33.845 21.69 34.187 ;
     RECT  27.54 33.053 43.182 34.205 ;
     RECT  15.912 34.187 20.43 34.699 ;
     RECT  15.84 34.699 20.43 34.897 ;
     RECT  15.768 34.897 20.43 34.925 ;
     RECT  14.94 34.897 14.958 34.933 ;
     RECT  15.768 34.925 19.602 34.933 ;
     RECT  26.64 33.053 26.658 34.969 ;
     RECT  20.34 34.925 20.43 35.069 ;
     RECT  26.64 34.969 26.802 35.069 ;
     RECT  14.94 34.933 19.602 35.275 ;
     RECT  13.215 27.509 13.497 35.671 ;
     RECT  14.508 35.275 19.602 35.671 ;
     RECT  26.64 35.069 26.658 35.735 ;
     RECT  13.215 35.671 19.602 35.743 ;
     RECT  23.544 32.729 24.297 35.771 ;
     RECT  13.14 35.743 19.602 35.815 ;
     RECT  20.34 35.069 20.358 35.815 ;
     RECT  13.14 35.815 20.358 36.049 ;
     RECT  13.14 36.049 20.43 36.121 ;
     RECT  23.904 35.771 24.297 36.149 ;
     RECT  12.636 36.121 20.43 36.211 ;
     RECT  11.988 36.211 20.43 36.751 ;
     RECT  27.756 34.205 43.182 36.859 ;
     RECT  10.836 36.661 10.854 37.003 ;
     RECT  11.628 36.751 20.43 37.003 ;
     RECT  10.836 37.003 20.43 37.121 ;
     RECT  11.016 37.121 20.43 37.201 ;
     RECT  11.016 37.201 20.718 37.319 ;
     RECT  11.016 37.319 20.43 37.517 ;
     RECT  27.072 36.859 43.182 37.901 ;
     RECT  11.16 37.517 20.43 38.515 ;
     RECT  27.072 37.901 41.994 38.677 ;
     RECT  26.604 38.677 41.994 38.713 ;
     RECT  42.732 37.901 43.182 38.713 ;
     RECT  10.872 38.515 20.43 38.821 ;
     RECT  10.872 38.821 20.646 39.055 ;
     RECT  10.692 39.055 20.646 39.091 ;
     RECT  10.296 39.091 20.646 39.209 ;
     RECT  10.296 39.209 20.538 39.355 ;
     RECT  26.496 38.713 43.182 39.595 ;
     RECT  25.812 39.595 43.182 39.659 ;
     RECT  10.08 39.355 20.538 39.785 ;
     RECT  10.44 39.785 20.538 40.019 ;
     RECT  25.956 39.659 43.182 40.205 ;
     RECT  25.956 40.205 42.21 40.361 ;
     RECT  25.956 40.361 40.554 40.405 ;
     RECT  25.92 40.405 40.554 40.441 ;
     RECT  25.128 40.441 40.554 40.469 ;
     RECT  24.015 36.149 24.297 40.675 ;
     RECT  25.128 40.469 40.497 40.675 ;
     RECT  41.328 40.361 42.21 40.703 ;
     RECT  2.415 27.917 2.697 40.787 ;
     RECT  7.815 27.599 8.097 40.787 ;
     RECT  23.976 40.675 40.497 40.787 ;
     RECT  10.44 40.019 20.322 40.829 ;
     RECT  23.976 40.787 40.305 40.829 ;
     RECT  41.328 40.703 42.174 40.829 ;
     RECT  10.44 40.829 19.962 40.865 ;
     RECT  10.44 40.865 15.066 40.901 ;
     RECT  23.976 40.829 36.45 40.901 ;
     RECT  37.188 40.829 40.305 40.901 ;
     RECT  32.94 40.901 36.45 40.937 ;
     RECT  10.44 40.901 13.77 40.945 ;
     RECT  10.332 40.945 13.77 40.973 ;
     RECT  14.544 40.901 15.066 40.973 ;
     RECT  15.876 40.865 19.386 40.973 ;
     RECT  32.94 40.937 33.966 40.973 ;
     RECT  38.052 40.901 40.305 40.973 ;
     RECT  23.976 40.901 31.95 40.981 ;
     RECT  14.544 40.973 14.994 41.009 ;
     RECT  17.676 40.973 19.386 41.009 ;
     RECT  32.976 40.973 33.966 41.009 ;
     RECT  38.34 40.973 39.186 41.009 ;
     RECT  40.068 40.973 40.305 41.009 ;
     RECT  10.332 40.973 13.734 41.021 ;
     RECT  14.616 41.009 14.994 41.021 ;
     RECT  15.876 40.973 16.938 41.021 ;
     RECT  2.415 40.787 2.505 41.057 ;
     RECT  7.815 40.787 7.905 41.057 ;
     RECT  13.215 41.021 13.734 41.057 ;
     RECT  18.144 41.009 18.705 41.057 ;
     RECT  34.815 40.937 36.234 41.057 ;
     RECT  40.215 41.009 40.305 41.057 ;
     RECT  32.976 41.009 32.994 41.069 ;
     RECT  41.328 40.829 41.994 41.069 ;
     RECT  10.332 41.021 12.366 41.117 ;
     RECT  13.536 41.057 13.734 41.165 ;
     RECT  38.34 41.009 38.358 41.261 ;
     RECT  35.496 41.057 36.234 41.357 ;
     RECT  42.948 40.205 43.182 41.513 ;
     RECT  42.948 41.513 43.11 41.549 ;
     RECT  15.876 41.021 15.894 41.645 ;
     RECT  42.948 41.549 42.966 41.645 ;
     RECT  41.328 41.069 41.958 41.741 ;
     RECT  36.216 41.357 36.234 41.837 ;
     RECT  41.4 41.741 41.958 41.933 ;
     RECT  23.94 40.981 31.95 41.981 ;
     RECT  39.168 41.009 39.186 42.029 ;
     RECT  28.44 41.981 31.95 42.077 ;
     RECT  23.94 41.981 27.414 42.125 ;
     RECT  41.4 41.933 41.418 42.125 ;
     RECT  10.332 41.117 11.394 42.173 ;
     RECT  12.348 41.117 12.366 42.173 ;
     RECT  18.144 41.057 18.162 42.173 ;
     RECT  23.94 42.125 26.55 42.173 ;
     RECT  28.476 42.077 31.95 42.173 ;
     RECT  10.332 42.173 11.322 42.221 ;
     RECT  24.48 42.173 24.498 42.221 ;
     RECT  26.136 42.173 26.19 42.221 ;
     RECT  28.98 42.173 31.95 42.221 ;
     RECT  28.98 42.221 29.574 42.269 ;
     RECT  26.136 42.221 26.154 42.845 ;
     RECT  13.68 41.165 13.734 42.989 ;
     RECT  30.888 42.221 31.698 43.037 ;
     RECT  10.62 42.221 10.638 43.085 ;
     RECT  13.68 42.989 13.698 43.085 ;
     RECT  29.088 42.269 29.574 43.085 ;
     RECT  31.14 43.037 31.698 43.085 ;
     RECT  29.088 43.085 29.106 43.181 ;
     RECT  33.048 43.051 33.066 43.181 ;
    LAYER M4 ;
     RECT  0.084 1.008 2.009 1.032 ;
     RECT  0.06 1.032 2.009 1.104 ;
     RECT  0.084 1.104 2.009 1.128 ;
     RECT  0.06 1.128 2.009 1.2 ;
     RECT  0.084 1.2 2.009 1.224 ;
     RECT  0.06 1.224 2.009 1.296 ;
     RECT  0.084 1.296 2.009 1.32 ;
     RECT  0.06 1.32 2.009 1.392 ;
     RECT  0.084 1.392 2.009 1.416 ;
     RECT  0.06 1.416 2.009 1.488 ;
     RECT  0.084 1.488 2.009 1.512 ;
     RECT  0.06 1.512 2.009 1.584 ;
     RECT  0.084 1.584 2.009 1.608 ;
     RECT  0.06 1.608 2.009 1.68 ;
     RECT  0.084 1.68 2.009 1.704 ;
     RECT  0.06 1.704 2.009 1.776 ;
     RECT  0.084 1.776 2.009 1.8 ;
     RECT  0.06 1.8 2.009 1.872 ;
     RECT  0.084 1.872 2.009 1.896 ;
     RECT  0.06 1.896 2.009 1.968 ;
     RECT  0.084 1.968 2.009 1.992 ;
     RECT  0.06 1.992 2.009 2.064 ;
     RECT  0.084 2.064 2.009 2.088 ;
     RECT  0.06 2.088 2.009 2.16 ;
     RECT  0.084 2.16 2.009 2.184 ;
     RECT  0.06 2.184 2.009 2.256 ;
     RECT  0.084 2.256 2.009 2.28 ;
     RECT  0.06 2.28 2.009 2.352 ;
     RECT  0.084 2.352 2.009 2.376 ;
     RECT  0.06 2.376 2.009 2.448 ;
     RECT  0.084 2.448 2.009 2.472 ;
     RECT  0.06 2.472 2.009 2.544 ;
     RECT  0.084 2.544 2.009 2.568 ;
     RECT  0.06 2.568 2.009 2.64 ;
     RECT  0.084 2.64 2.009 2.664 ;
     RECT  0.06 2.664 2.009 2.736 ;
     RECT  0.084 2.736 2.009 2.76 ;
     RECT  0.06 2.76 2.009 2.832 ;
     RECT  0.084 2.832 2.009 2.856 ;
     RECT  0.06 2.856 2.009 2.928 ;
     RECT  0.084 2.928 2.009 2.952 ;
     RECT  0.06 2.952 2.009 3.024 ;
     RECT  0.084 3.024 2.009 3.048 ;
     RECT  0.06 3.048 2.009 3.12 ;
     RECT  0.084 3.12 2.009 3.144 ;
     RECT  0.06 3.144 2.009 3.216 ;
     RECT  0.084 3.216 2.009 3.24 ;
     RECT  0.06 3.24 2.009 3.312 ;
     RECT  0.084 3.312 2.009 3.336 ;
     RECT  0.06 3.336 2.009 3.408 ;
     RECT  0.084 3.408 2.009 3.432 ;
     RECT  0.06 3.432 2.009 3.504 ;
     RECT  0.084 3.504 2.009 3.528 ;
     RECT  0.06 3.528 2.009 3.6 ;
     RECT  0.084 3.6 2.009 3.624 ;
     RECT  0.06 3.624 2.009 3.696 ;
     RECT  0.084 3.696 2.009 3.72 ;
     RECT  0.06 3.72 2.009 3.792 ;
     RECT  0.084 3.792 2.009 3.816 ;
     RECT  0.06 3.816 2.009 3.888 ;
     RECT  0.084 3.888 2.009 3.912 ;
     RECT  0.06 3.912 2.009 3.984 ;
     RECT  0.084 3.984 2.009 4.008 ;
     RECT  0.06 4.008 2.009 4.848 ;
     RECT  0.084 4.848 2.009 4.872 ;
     RECT  0.06 4.872 2.009 4.944 ;
     RECT  0.084 4.944 2.009 4.968 ;
     RECT  0.06 4.968 2.009 5.04 ;
     RECT  0.084 5.04 2.009 5.064 ;
     RECT  0.06 5.064 2.009 5.136 ;
     RECT  0.084 5.136 2.009 5.16 ;
     RECT  0.06 5.16 2.009 5.232 ;
     RECT  0.084 5.232 2.009 5.256 ;
     RECT  0.06 5.256 2.009 5.328 ;
     RECT  0.084 5.328 2.009 5.352 ;
     RECT  0.06 5.352 2.009 5.424 ;
     RECT  0.084 5.424 2.009 5.448 ;
     RECT  0.06 5.448 2.009 5.52 ;
     RECT  0.084 5.52 2.009 5.544 ;
     RECT  0.06 5.544 2.009 5.616 ;
     RECT  0.084 5.616 2.009 5.64 ;
     RECT  0.06 5.64 2.009 5.712 ;
     RECT  0.084 5.712 2.009 5.736 ;
     RECT  0.06 5.736 2.009 5.808 ;
     RECT  0.084 5.808 2.009 5.832 ;
     RECT  0.06 5.832 2.009 5.904 ;
     RECT  0.084 5.904 2.009 5.928 ;
     RECT  0.06 5.928 2.009 6 ;
     RECT  0.084 6 2.009 6.024 ;
     RECT  0.06 6.024 2.009 6.096 ;
     RECT  0.084 6.096 2.009 6.12 ;
     RECT  0.06 6.12 2.009 6.192 ;
     RECT  0.084 6.192 2.009 6.216 ;
     RECT  0.06 6.216 2.009 6.288 ;
     RECT  0.084 6.288 2.009 6.312 ;
     RECT  0.06 6.312 2.009 6.384 ;
     RECT  0.084 6.384 2.009 6.408 ;
     RECT  0.06 6.408 2.009 6.48 ;
     RECT  0.084 6.48 2.009 6.504 ;
     RECT  0.06 6.504 2.009 6.576 ;
     RECT  0.084 6.576 2.009 6.6 ;
     RECT  0.06 6.6 2.009 6.672 ;
     RECT  0.084 6.672 2.009 6.696 ;
     RECT  0.06 6.696 2.009 6.768 ;
     RECT  0.084 6.768 2.009 6.792 ;
     RECT  0.06 6.792 2.009 6.864 ;
     RECT  0.084 6.864 2.009 6.888 ;
     RECT  0.06 6.888 2.009 6.96 ;
     RECT  0.084 6.96 2.009 6.984 ;
     RECT  0.06 6.984 2.009 7.056 ;
     RECT  0.084 7.056 2.009 7.08 ;
     RECT  0.06 7.08 2.009 7.152 ;
     RECT  0.084 7.152 2.009 7.176 ;
     RECT  0.06 7.176 2.009 7.248 ;
     RECT  0.084 7.248 2.009 7.272 ;
     RECT  0.06 7.272 2.009 7.344 ;
     RECT  0.084 7.344 2.009 7.368 ;
     RECT  0.06 7.368 2.009 7.44 ;
     RECT  0.084 7.44 2.009 7.464 ;
     RECT  0.06 7.464 2.009 7.536 ;
     RECT  0.084 7.536 2.009 7.56 ;
     RECT  0.06 7.56 2.009 7.632 ;
     RECT  0.084 7.632 2.009 7.656 ;
     RECT  0.06 7.656 2.009 7.728 ;
     RECT  0.084 7.728 2.009 7.752 ;
     RECT  0.06 7.752 2.009 7.824 ;
     RECT  0.084 7.824 2.009 7.848 ;
     RECT  0.06 7.848 2.009 7.92 ;
     RECT  0.084 7.92 2.009 7.944 ;
     RECT  0.06 7.944 2.009 8.016 ;
     RECT  0.084 8.016 2.009 8.04 ;
     RECT  0.06 8.04 2.009 8.112 ;
     RECT  0.084 8.112 2.009 8.136 ;
     RECT  0.06 8.136 2.009 8.208 ;
     RECT  0.084 8.208 2.009 8.232 ;
     RECT  0.06 8.232 2.009 8.304 ;
     RECT  0.084 8.304 2.009 8.328 ;
     RECT  0.06 8.328 2.009 8.4 ;
     RECT  0.084 8.4 2.009 8.424 ;
     RECT  0.06 8.424 2.009 8.496 ;
     RECT  0.084 8.496 2.009 8.52 ;
     RECT  0.06 8.52 2.009 8.592 ;
     RECT  0.084 8.592 2.009 8.616 ;
     RECT  0.06 8.616 2.009 8.688 ;
     RECT  0.084 8.688 2.009 8.712 ;
     RECT  0.06 8.712 2.009 8.784 ;
     RECT  0.084 8.784 2.009 8.808 ;
     RECT  0.06 8.808 2.009 8.88 ;
     RECT  0.084 8.88 2.009 8.904 ;
     RECT  0.06 8.904 2.009 8.976 ;
     RECT  0.084 8.976 2.009 9 ;
     RECT  0.06 9 2.009 9.072 ;
     RECT  0.084 9.072 2.009 9.096 ;
     RECT  0.06 9.096 2.009 9.168 ;
     RECT  0.084 9.168 2.009 9.192 ;
     RECT  0.06 9.192 2.009 9.264 ;
     RECT  0.084 9.264 2.009 9.288 ;
     RECT  0.06 9.288 2.009 9.36 ;
     RECT  0.084 9.36 2.009 9.384 ;
     RECT  0.06 9.384 2.009 9.456 ;
     RECT  0.084 9.456 2.009 9.48 ;
     RECT  0.06 9.48 2.009 9.552 ;
     RECT  0.084 9.552 2.009 9.576 ;
     RECT  0.06 9.576 2.009 9.648 ;
     RECT  0.084 9.648 2.009 9.672 ;
     RECT  0.06 9.672 2.009 9.744 ;
     RECT  0.084 9.744 2.009 9.768 ;
     RECT  0.06 9.768 2.009 9.84 ;
     RECT  0.084 9.84 2.009 9.864 ;
     RECT  0.06 9.864 2.009 9.936 ;
     RECT  0.084 9.936 2.009 9.96 ;
     RECT  0.06 9.96 2.009 10.032 ;
     RECT  0.084 10.032 2.009 10.056 ;
     RECT  0.06 10.056 2.009 10.128 ;
     RECT  0.084 10.128 2.009 10.152 ;
     RECT  0.06 10.152 2.009 10.224 ;
     RECT  0.084 10.224 2.009 10.248 ;
     RECT  0.06 10.248 2.009 10.32 ;
     RECT  0.084 10.32 2.009 10.344 ;
     RECT  0.06 10.344 2.009 10.416 ;
     RECT  0.084 10.416 2.009 10.44 ;
     RECT  0.06 10.44 2.009 10.512 ;
     RECT  0.084 10.512 2.009 10.536 ;
     RECT  0.06 10.536 2.009 10.608 ;
     RECT  0.084 10.608 2.009 10.632 ;
     RECT  0.06 10.632 2.009 10.704 ;
     RECT  0.084 10.704 2.009 10.728 ;
     RECT  0.06 10.728 2.009 10.8 ;
     RECT  0.084 10.8 2.009 10.824 ;
     RECT  0.06 10.824 2.009 10.896 ;
     RECT  0.084 10.896 2.009 10.92 ;
     RECT  0.06 10.92 2.009 10.992 ;
     RECT  0.084 10.992 2.009 11.016 ;
     RECT  0.06 11.016 2.009 11.088 ;
     RECT  0.084 11.088 2.009 11.112 ;
     RECT  0.06 11.112 2.009 11.184 ;
     RECT  0.084 11.184 2.009 11.208 ;
     RECT  0.06 11.208 2.009 11.28 ;
     RECT  0.084 11.28 2.009 11.304 ;
     RECT  0.06 11.304 2.009 11.376 ;
     RECT  0.084 11.376 2.009 11.4 ;
     RECT  0.06 11.4 2.009 11.472 ;
     RECT  0.084 11.472 2.009 11.496 ;
     RECT  0.06 11.496 2.009 11.568 ;
     RECT  0.084 11.568 2.009 11.592 ;
     RECT  0.06 11.592 2.009 11.664 ;
     RECT  0.084 11.664 2.009 11.688 ;
     RECT  0.06 11.688 2.009 11.76 ;
     RECT  0.084 11.76 2.009 11.784 ;
     RECT  0.06 11.784 2.009 11.856 ;
     RECT  0.084 11.856 2.009 11.88 ;
     RECT  0.06 11.88 2.009 11.952 ;
     RECT  0.084 11.952 2.009 11.976 ;
     RECT  0.06 11.976 2.009 12.048 ;
     RECT  0.084 12.048 2.009 12.072 ;
     RECT  0.06 12.072 2.009 12.144 ;
     RECT  0.084 12.144 2.009 12.168 ;
     RECT  0.06 12.168 2.009 12.24 ;
     RECT  0.084 12.24 2.009 12.264 ;
     RECT  0.06 12.264 2.009 12.336 ;
     RECT  0.084 12.336 2.009 12.36 ;
     RECT  0.06 12.36 2.009 12.432 ;
     RECT  0.084 12.432 2.009 12.456 ;
     RECT  0.06 12.456 2.009 12.528 ;
     RECT  0.084 12.528 2.009 12.552 ;
     RECT  0.06 12.552 2.009 12.624 ;
     RECT  0.084 12.624 2.009 12.648 ;
     RECT  0.06 12.648 2.009 12.72 ;
     RECT  0.084 12.72 2.009 12.744 ;
     RECT  0.06 12.744 2.009 12.816 ;
     RECT  0.084 12.816 2.009 12.84 ;
     RECT  0.06 12.84 2.009 12.912 ;
     RECT  0.084 12.912 2.009 12.936 ;
     RECT  0.06 12.936 2.009 13.008 ;
     RECT  0.084 13.008 2.009 13.032 ;
     RECT  0.06 13.032 2.009 13.104 ;
     RECT  0.084 13.104 2.009 13.128 ;
     RECT  0.06 13.128 2.009 13.2 ;
     RECT  0.084 13.2 2.009 13.224 ;
     RECT  0.06 13.224 2.009 13.296 ;
     RECT  0.084 13.296 2.009 13.32 ;
     RECT  0.06 13.32 2.009 13.392 ;
     RECT  0.084 13.392 2.009 13.416 ;
     RECT  0.06 13.416 2.009 13.488 ;
     RECT  0.084 13.488 2.009 13.512 ;
     RECT  0.06 13.512 2.009 13.584 ;
     RECT  0.084 13.584 2.009 13.608 ;
     RECT  0.06 13.608 2.009 13.68 ;
     RECT  0.084 13.68 2.009 13.704 ;
     RECT  0.06 13.704 2.009 13.776 ;
     RECT  0.084 13.776 2.009 13.8 ;
     RECT  0.06 13.8 2.009 13.872 ;
     RECT  0.084 13.872 2.009 13.896 ;
     RECT  0.06 13.896 2.009 13.968 ;
     RECT  0.084 13.968 2.009 13.992 ;
     RECT  0.06 13.992 2.009 14.064 ;
     RECT  0.084 14.064 2.009 14.088 ;
     RECT  0.06 14.088 2.009 14.16 ;
     RECT  0.084 14.16 2.009 14.184 ;
     RECT  0.06 14.184 2.009 14.256 ;
     RECT  0.084 14.256 2.009 14.28 ;
     RECT  0.06 14.28 2.009 14.352 ;
     RECT  0.084 14.352 2.009 14.376 ;
     RECT  0.06 14.376 2.009 14.448 ;
     RECT  0.084 14.448 2.009 14.472 ;
     RECT  0.06 14.472 2.009 14.544 ;
     RECT  0.084 14.544 2.009 14.568 ;
     RECT  0.06 14.568 2.009 14.64 ;
     RECT  0.084 14.64 2.009 14.664 ;
     RECT  0.06 14.664 2.009 14.736 ;
     RECT  0.084 14.736 2.009 14.76 ;
     RECT  0.06 14.76 2.009 14.832 ;
     RECT  0.084 14.832 2.009 14.856 ;
     RECT  0.06 14.856 2.009 14.928 ;
     RECT  0.084 14.928 2.009 14.952 ;
     RECT  0.06 14.952 2.009 15.024 ;
     RECT  0.084 15.024 2.009 15.048 ;
     RECT  0.06 15.048 2.009 15.12 ;
     RECT  0.084 15.12 2.009 15.144 ;
     RECT  0.06 15.144 2.009 15.216 ;
     RECT  0.084 15.216 2.009 15.24 ;
     RECT  0.06 15.24 2.009 15.312 ;
     RECT  0.084 15.312 2.009 15.336 ;
     RECT  0.06 15.336 2.009 15.408 ;
     RECT  0.084 15.408 2.009 15.432 ;
     RECT  0.06 15.432 2.009 15.504 ;
     RECT  0.084 15.504 2.009 15.528 ;
     RECT  0.06 15.528 2.009 15.6 ;
     RECT  0.084 15.6 2.009 15.624 ;
     RECT  0.06 15.624 2.009 15.696 ;
     RECT  0.084 15.696 2.009 15.72 ;
     RECT  0.06 15.72 2.009 15.792 ;
     RECT  0.084 15.792 2.009 15.816 ;
     RECT  0.06 15.816 2.009 15.888 ;
     RECT  0.084 15.888 2.009 15.912 ;
     RECT  0.06 15.912 2.009 15.984 ;
     RECT  0.084 15.984 2.009 16.008 ;
     RECT  0.06 16.008 2.009 16.08 ;
     RECT  0.084 16.08 2.009 16.104 ;
     RECT  0.06 16.104 2.009 16.176 ;
     RECT  0.084 16.176 2.009 16.2 ;
     RECT  0.06 16.2 2.009 16.272 ;
     RECT  0.084 16.272 2.009 16.296 ;
     RECT  0.06 16.296 2.009 16.368 ;
     RECT  0.084 16.368 2.009 16.392 ;
     RECT  0.06 16.392 2.009 16.464 ;
     RECT  0.084 16.464 2.009 16.488 ;
     RECT  0.06 16.488 2.009 16.56 ;
     RECT  0.084 16.56 2.009 16.584 ;
     RECT  0.06 16.584 2.009 16.656 ;
     RECT  0.084 16.656 2.009 16.68 ;
     RECT  0.06 16.68 2.009 16.752 ;
     RECT  0.084 16.752 2.009 16.776 ;
     RECT  0.06 16.776 2.009 16.848 ;
     RECT  0.084 16.848 2.009 16.872 ;
     RECT  0.06 16.872 2.009 16.944 ;
     RECT  0.084 16.944 2.009 16.968 ;
     RECT  0.06 16.968 2.009 17.04 ;
     RECT  0.084 17.04 2.009 17.064 ;
     RECT  0.06 17.064 2.009 17.136 ;
     RECT  0.084 17.136 2.009 17.16 ;
     RECT  0.06 17.16 2.009 17.232 ;
     RECT  0.084 17.232 2.009 17.256 ;
     RECT  0.06 17.256 2.009 17.328 ;
     RECT  0.084 17.328 2.009 17.352 ;
     RECT  0.06 17.352 2.009 17.424 ;
     RECT  0.084 17.424 2.009 17.448 ;
     RECT  0.06 17.448 2.009 17.52 ;
     RECT  0.084 17.52 2.009 17.544 ;
     RECT  0.06 17.544 2.009 17.616 ;
     RECT  0.084 17.616 2.009 17.64 ;
     RECT  0.06 17.64 2.009 17.712 ;
     RECT  0.084 17.712 2.009 17.736 ;
     RECT  0.06 17.736 2.009 17.808 ;
     RECT  0.084 17.808 2.009 17.832 ;
     RECT  0.06 17.832 2.009 17.904 ;
     RECT  0.084 17.904 2.009 17.928 ;
     RECT  0.06 17.928 2.009 18 ;
     RECT  0.084 18 2.009 18.024 ;
     RECT  0.06 18.024 2.009 18.096 ;
     RECT  0.084 18.096 2.009 18.12 ;
     RECT  0.06 18.12 2.009 18.192 ;
     RECT  0.084 18.192 2.009 18.216 ;
     RECT  0.06 18.216 2.009 18.288 ;
     RECT  0.084 18.288 2.009 18.312 ;
     RECT  0.06 18.312 2.009 18.384 ;
     RECT  0.084 18.384 2.009 18.408 ;
     RECT  0.06 18.408 2.009 18.48 ;
     RECT  0.084 18.48 2.009 18.504 ;
     RECT  0.06 18.504 2.009 18.576 ;
     RECT  0.084 18.576 2.009 18.6 ;
     RECT  0.06 18.6 2.009 18.672 ;
     RECT  0.084 18.672 2.009 18.696 ;
     RECT  0.06 18.696 2.009 18.768 ;
     RECT  0.084 18.768 2.009 18.792 ;
     RECT  0.06 18.792 2.009 18.864 ;
     RECT  0.084 18.864 2.009 18.888 ;
     RECT  0.06 18.888 2.009 18.96 ;
     RECT  0.084 18.96 2.009 18.984 ;
     RECT  0.06 18.984 2.009 19.056 ;
     RECT  0.084 19.056 2.009 19.08 ;
     RECT  0.06 19.08 2.009 19.152 ;
     RECT  0.084 19.152 2.009 19.176 ;
     RECT  0.06 19.176 2.009 19.248 ;
     RECT  0.084 19.248 2.009 19.272 ;
     RECT  0.06 19.272 2.009 19.344 ;
     RECT  0.084 19.344 2.009 19.368 ;
     RECT  0.06 19.368 2.009 19.44 ;
     RECT  0.084 19.44 2.009 19.464 ;
     RECT  0.06 19.464 2.009 19.536 ;
     RECT  0.084 19.536 2.009 19.56 ;
     RECT  0.06 19.56 2.009 19.632 ;
     RECT  0.084 19.632 2.009 19.656 ;
     RECT  0.06 19.656 2.009 19.728 ;
     RECT  0.084 19.728 2.009 19.752 ;
     RECT  0.06 19.752 2.009 19.824 ;
     RECT  0.084 19.824 2.009 19.848 ;
     RECT  0.06 19.848 2.009 19.92 ;
     RECT  0.084 19.92 2.009 19.944 ;
     RECT  0.06 19.944 2.009 20.016 ;
     RECT  0.084 20.016 2.009 20.04 ;
     RECT  0.06 20.04 2.009 20.112 ;
     RECT  0.084 20.112 2.009 20.136 ;
     RECT  0.06 20.136 2.009 20.208 ;
     RECT  0.084 20.208 2.009 20.232 ;
     RECT  0.06 20.232 2.009 20.304 ;
     RECT  0.084 20.304 2.009 20.328 ;
     RECT  0.06 20.328 2.009 20.4 ;
     RECT  0.084 20.4 2.009 20.424 ;
     RECT  0.06 20.424 2.009 20.496 ;
     RECT  0.084 20.496 2.009 20.52 ;
     RECT  0.06 20.52 2.009 20.592 ;
     RECT  0.084 20.592 2.009 20.616 ;
     RECT  0.06 20.616 2.009 20.688 ;
     RECT  0.084 20.688 2.009 20.712 ;
     RECT  0.06 20.712 2.009 20.784 ;
     RECT  0.084 20.784 2.009 20.808 ;
     RECT  0.06 20.808 2.009 20.88 ;
     RECT  0.084 20.88 2.009 20.904 ;
     RECT  0.06 20.904 2.009 20.976 ;
     RECT  0.084 20.976 2.009 21 ;
     RECT  0.06 21 2.009 21.072 ;
     RECT  0.084 21.072 2.009 21.096 ;
     RECT  0.06 21.096 2.009 21.168 ;
     RECT  0.084 21.168 2.009 21.192 ;
     RECT  0.06 21.192 2.009 21.264 ;
     RECT  0.084 21.264 2.009 21.288 ;
     RECT  0.06 21.288 2.009 21.36 ;
     RECT  0.084 21.36 2.009 21.384 ;
     RECT  0.06 21.384 2.009 21.456 ;
     RECT  0.084 21.456 2.009 21.48 ;
     RECT  0.06 21.48 2.009 21.552 ;
     RECT  0.084 21.552 2.009 21.576 ;
     RECT  0.06 21.576 2.009 21.648 ;
     RECT  0.084 21.648 2.009 21.672 ;
     RECT  0.06 21.672 2.009 21.744 ;
     RECT  0.084 21.744 2.009 21.768 ;
     RECT  0.06 21.768 2.009 21.84 ;
     RECT  0.084 21.84 2.009 21.864 ;
     RECT  0.06 21.864 2.009 21.936 ;
     RECT  0.084 21.936 2.009 21.96 ;
     RECT  0.06 21.96 2.009 22.032 ;
     RECT  0.084 22.032 2.009 22.056 ;
     RECT  0.06 22.056 2.009 22.128 ;
     RECT  0.084 22.128 2.009 22.152 ;
     RECT  0.06 22.152 2.009 22.224 ;
     RECT  0.084 22.224 2.009 22.248 ;
     RECT  0.06 22.248 2.009 22.32 ;
     RECT  0.084 22.32 2.009 22.344 ;
     RECT  0.06 22.344 2.009 22.416 ;
     RECT  0.084 22.416 2.009 22.44 ;
     RECT  0.06 22.44 2.009 22.512 ;
     RECT  0.084 22.512 2.009 22.536 ;
     RECT  0.06 22.536 2.009 22.608 ;
     RECT  0.084 22.608 2.009 22.632 ;
     RECT  0.06 22.632 2.009 22.704 ;
     RECT  0.084 22.704 2.009 22.728 ;
     RECT  0.06 22.728 2.009 22.8 ;
     RECT  0.084 22.8 2.009 22.824 ;
     RECT  0.06 22.824 2.009 22.896 ;
     RECT  0.084 22.896 2.009 22.92 ;
     RECT  0.06 22.92 2.009 22.992 ;
     RECT  0.084 22.992 2.009 23.016 ;
     RECT  0.06 23.016 2.009 23.088 ;
     RECT  0.084 23.088 2.009 23.112 ;
     RECT  0.06 23.112 2.009 23.184 ;
     RECT  0.084 23.184 2.009 23.208 ;
     RECT  0.06 23.208 2.009 24.048 ;
     RECT  0.084 24.048 2.009 24.072 ;
     RECT  0.06 24.072 2.009 24.144 ;
     RECT  0.084 24.144 2.009 24.168 ;
     RECT  0.06 24.168 2.009 24.24 ;
     RECT  0.084 24.24 2.009 24.264 ;
     RECT  0.06 24.264 2.009 24.336 ;
     RECT  0.084 24.336 2.009 24.36 ;
     RECT  0.06 24.36 2.009 24.432 ;
     RECT  0.084 24.432 2.009 24.456 ;
     RECT  0.06 24.456 2.009 24.528 ;
     RECT  0.084 24.528 2.009 24.552 ;
     RECT  0.06 24.552 2.009 24.624 ;
     RECT  0.084 24.624 2.009 24.648 ;
     RECT  0.06 24.648 2.009 24.72 ;
     RECT  0.084 24.72 2.009 24.744 ;
     RECT  0.06 24.744 2.009 24.816 ;
     RECT  0.084 24.816 2.009 24.84 ;
     RECT  0.06 24.84 2.009 24.912 ;
     RECT  0.084 24.912 2.009 24.936 ;
     RECT  0.06 24.936 2.009 25.008 ;
     RECT  0.084 25.008 2.009 25.032 ;
     RECT  0.06 25.032 2.009 25.104 ;
     RECT  0.084 25.104 2.009 25.128 ;
     RECT  0.06 25.128 2.009 25.2 ;
     RECT  0.084 25.2 2.009 25.224 ;
     RECT  0.06 25.224 2.009 25.296 ;
     RECT  0.084 25.296 2.009 25.32 ;
     RECT  0.06 25.32 2.009 25.392 ;
     RECT  0.084 25.392 2.009 25.416 ;
     RECT  0.06 25.416 2.009 25.488 ;
     RECT  0.084 25.488 2.009 25.512 ;
     RECT  0.06 25.512 2.009 25.584 ;
     RECT  0.084 25.584 2.009 25.608 ;
     RECT  0.06 25.608 2.009 25.68 ;
     RECT  0.084 25.68 2.009 25.704 ;
     RECT  0.06 25.704 2.009 25.776 ;
     RECT  0.084 25.776 2.009 25.8 ;
     RECT  0.06 25.8 2.009 25.872 ;
     RECT  0.084 25.872 2.009 25.896 ;
     RECT  0.06 25.896 2.009 25.968 ;
     RECT  0.084 25.968 2.009 25.992 ;
     RECT  0.06 25.992 2.009 26.064 ;
     RECT  0.084 26.064 2.009 26.088 ;
     RECT  0.06 26.088 2.009 26.16 ;
     RECT  0.084 26.16 2.009 26.184 ;
     RECT  0.06 26.184 2.009 26.256 ;
     RECT  0.084 26.256 2.009 26.28 ;
     RECT  2.009 1.296 2.408 26.28 ;
     RECT  2.408 1.296 2.512 41.052 ;
     RECT  2.512 1.296 2.704 40.782 ;
     RECT  2.704 5.184 2.837 26.04 ;
     RECT  2.704 27.168 2.867 27.912 ;
     RECT  2.837 5.184 2.873 22.248 ;
     RECT  2.837 23.376 2.909 26.04 ;
     RECT  2.704 1.296 3.197 3.768 ;
     RECT  2.909 26.016 3.377 26.04 ;
     RECT  3.197 1.488 3.449 3.768 ;
     RECT  2.873 19.152 3.457 22.248 ;
     RECT  2.873 5.184 3.841 18.168 ;
     RECT  3.841 5.088 3.877 18.168 ;
     RECT  3.457 19.152 3.877 21.672 ;
     RECT  2.867 27.888 4.277 27.912 ;
     RECT  3.877 5.088 4.501 21.672 ;
     RECT  4.213 26.256 4.561 26.28 ;
     RECT  3.449 1.584 4.597 3.768 ;
     RECT  4.501 4.848 4.597 21.672 ;
     RECT  4.597 1.584 4.633 21.672 ;
     RECT  4.633 1.584 4.733 21.72 ;
     RECT  2.909 23.376 4.741 24.792 ;
     RECT  4.561 26.256 4.741 27.336 ;
     RECT  4.741 23.376 4.777 27.336 ;
     RECT  4.733 1.584 4.885 22.2 ;
     RECT  4.777 23.232 4.885 27.336 ;
     RECT  4.885 1.584 5.821 27.336 ;
     RECT  5.821 1.584 6.179 27.384 ;
     RECT  6.179 1.584 6.221 27 ;
     RECT  6.221 2.352 7.808 27 ;
     RECT  7.808 2.148 7.912 41.052 ;
     RECT  7.912 2.256 8.104 40.782 ;
     RECT  8.104 2.256 8.129 26.04 ;
     RECT  8.129 24.096 8.165 26.04 ;
     RECT  8.165 24.096 8.417 25.752 ;
     RECT  8.417 24.72 8.533 25.752 ;
     RECT  8.533 25.728 8.813 25.752 ;
     RECT  8.533 24.72 8.885 24.744 ;
     RECT  8.129 2.256 9.101 23.016 ;
     RECT  9.101 2.352 9.173 23.016 ;
     RECT  9.173 10.464 9.317 23.016 ;
     RECT  9.317 17.76 9.353 23.016 ;
     RECT  9.317 10.464 9.569 16.632 ;
     RECT  9.173 2.448 9.605 9.336 ;
     RECT  9.569 16.08 9.749 16.632 ;
     RECT  9.353 17.76 9.785 19.992 ;
     RECT  9.353 21.408 9.785 23.016 ;
     RECT  9.569 10.464 9.965 14.712 ;
     RECT  9.785 17.76 9.965 19.656 ;
     RECT  9.965 14.688 10.001 14.712 ;
     RECT  9.605 2.88 10.037 9.336 ;
     RECT  10.037 3.408 10.177 9.336 ;
     RECT  9.965 10.464 10.177 13.08 ;
     RECT  10.177 3.408 10.217 13.08 ;
     RECT  10.321 42.192 10.429 42.216 ;
     RECT  9.749 16.224 10.465 16.632 ;
     RECT  9.965 17.76 10.465 18.504 ;
     RECT  10.217 3.408 10.577 11.352 ;
     RECT  10.429 41.712 10.609 42.216 ;
     RECT  10.577 4.176 10.721 11.352 ;
     RECT  10.721 6.48 10.793 11.352 ;
     RECT  10.793 6.72 10.829 11.352 ;
     RECT  10.217 13.008 10.865 13.08 ;
     RECT  10.465 16.224 10.937 18.504 ;
     RECT  9.785 22.176 11.009 23.016 ;
     RECT  10.609 41.712 11.027 43.08 ;
     RECT  10.988 37.488 11.029 37.512 ;
     RECT  11.027 41.712 11.041 42.216 ;
     RECT  10.721 4.176 11.045 5.352 ;
     RECT  11.173 40.464 11.185 40.488 ;
     RECT  11.041 41.616 11.185 42.216 ;
     RECT  11.029 37.488 11.269 38.184 ;
     RECT  10.069 39.36 11.293 39.384 ;
     RECT  11.185 40.464 11.293 42.216 ;
     RECT  11.045 4.176 11.297 5.304 ;
     RECT  11.269 37.104 11.365 38.184 ;
     RECT  10.937 16.32 11.473 18.504 ;
     RECT  9.965 19.632 11.473 19.656 ;
     RECT  11.293 39.36 11.603 42.216 ;
     RECT  11.603 39.36 11.795 42.168 ;
     RECT  11.473 16.32 11.909 19.656 ;
     RECT  11.365 37.008 11.941 38.184 ;
     RECT  11.795 39.36 11.941 41.112 ;
     RECT  11.941 37.008 11.945 41.112 ;
     RECT  10.829 9.888 11.989 11.352 ;
     RECT  10.865 13.056 12.035 13.08 ;
     RECT  11.941 25.008 12.037 25.032 ;
     RECT  11.945 39.648 12.083 41.112 ;
     RECT  11.909 16.32 12.085 18.84 ;
     RECT  12.037 24.912 12.124 25.032 ;
     RECT  11.009 22.176 12.193 22.2 ;
     RECT  12.193 22.176 12.265 22.248 ;
     RECT  11.297 4.416 12.337 5.304 ;
     RECT  10.829 6.72 12.337 8.568 ;
     RECT  11.989 14.064 12.409 14.088 ;
     RECT  11.989 9.888 12.527 11.544 ;
     RECT  12.527 9.888 12.553 11.688 ;
     RECT  11.795 42.144 12.563 42.168 ;
     RECT  11.293 20.928 12.565 20.952 ;
     RECT  12.337 4.416 12.625 8.568 ;
     RECT  12.553 9.888 12.625 11.784 ;
     RECT  12.409 13.632 12.661 14.088 ;
     RECT  12.085 15.456 12.661 18.84 ;
     RECT  12.625 4.416 12.697 11.784 ;
     RECT  12.265 21.984 12.733 22.248 ;
     RECT  11.365 23.328 12.733 23.352 ;
     RECT  11.653 2.832 12.769 2.856 ;
     RECT  12.661 0.288 12.985 0.312 ;
     RECT  12.985 0.096 13.021 0.312 ;
     RECT  12.697 4.416 13.057 12.36 ;
     RECT  12.661 13.632 13.057 18.84 ;
     RECT  11.945 37.008 13.093 38.664 ;
     RECT  12.083 39.648 13.093 41.016 ;
     RECT  12.769 2.832 13.165 3.048 ;
     RECT  13.057 4.128 13.165 12.36 ;
     RECT  13.165 2.832 13.208 12.36 ;
     RECT  13.057 13.584 13.208 18.84 ;
     RECT  12.565 20.112 13.208 20.952 ;
     RECT  12.733 21.936 13.208 23.352 ;
     RECT  12.124 25.008 13.208 25.032 ;
     RECT  13.093 37.008 13.208 41.016 ;
     RECT  13.208 2.148 13.345 41.052 ;
     RECT  13.345 1.824 13.381 41.052 ;
     RECT  13.381 1.728 13.477 41.052 ;
     RECT  13.477 1.728 13.504 41.16 ;
     RECT  13.504 37.104 13.565 41.16 ;
     RECT  13.189 42.72 13.667 43.08 ;
     RECT  13.504 9.792 13.673 24.12 ;
     RECT  13.565 37.104 13.673 40.584 ;
     RECT  13.667 42.96 13.745 43.08 ;
     RECT  13.504 1.728 13.781 8.568 ;
     RECT  13.673 37.104 13.781 39.24 ;
     RECT  13.021 0.096 14.003 0.648 ;
     RECT  13.673 10.704 14.003 24.12 ;
     RECT  13.781 1.728 14.069 7.896 ;
     RECT  13.781 37.104 14.069 38.76 ;
     RECT  13.745 43.056 14.099 43.08 ;
     RECT  14.069 5.184 14.105 7.896 ;
     RECT  14.069 37.2 14.113 38.76 ;
     RECT  14.003 0.096 14.147 0.168 ;
     RECT  14.069 1.728 14.173 3.96 ;
     RECT  14.105 6.96 14.357 7.896 ;
     RECT  14.003 10.704 14.387 14.232 ;
     RECT  14.113 37.2 14.393 38.376 ;
     RECT  14.393 37.2 14.429 38.184 ;
     RECT  14.357 6.96 14.537 7.704 ;
     RECT  14.173 1.152 14.579 3.96 ;
     RECT  13.673 40.464 14.605 40.584 ;
     RECT  14.003 15.6 14.609 24.12 ;
     RECT  14.387 10.848 14.825 14.232 ;
     RECT  14.609 17.616 14.861 24.12 ;
     RECT  14.861 18.48 14.915 24.12 ;
     RECT  13.504 35.904 14.929 35.976 ;
     RECT  14.609 15.6 15.005 16.584 ;
     RECT  15.005 16.224 15.077 16.584 ;
     RECT  14.537 6.96 15.113 7.656 ;
     RECT  14.579 1.728 15.181 3.96 ;
     RECT  14.105 5.184 15.181 5.832 ;
     RECT  14.915 18.576 15.205 24.12 ;
     RECT  14.825 11.52 15.217 14.232 ;
     RECT  15.113 6.96 15.301 7.464 ;
     RECT  15.181 1.728 15.395 5.832 ;
     RECT  15.217 11.52 15.395 15.192 ;
     RECT  15.395 5.136 15.404 5.832 ;
     RECT  15.301 6.864 15.404 7.464 ;
     RECT  14.929 35.328 15.433 35.976 ;
     RECT  14.429 37.2 15.433 37.944 ;
     RECT  15.433 35.328 15.505 37.944 ;
     RECT  15.395 11.664 15.581 15.192 ;
     RECT  15.205 18.576 15.685 24.312 ;
     RECT  15.685 18.576 15.721 24.456 ;
     RECT  15.685 25.68 15.721 25.704 ;
     RECT  15.581 13.056 15.725 15.192 ;
     RECT  15.404 5.136 15.731 7.464 ;
     RECT  15.505 35.328 15.731 38.712 ;
     RECT  14.605 40.464 15.865 41.016 ;
     RECT  15.721 18.576 15.923 25.704 ;
     RECT  15.731 7.2 15.941 7.464 ;
     RECT  15.865 31.584 15.973 31.608 ;
     RECT  15.505 33.264 15.973 33.288 ;
     RECT  14.147 0.096 16.069 0.12 ;
     RECT  15.865 40.464 16.115 41.64 ;
     RECT  15.397 27.888 16.124 27.912 ;
     RECT  15.923 18.576 16.225 25.464 ;
     RECT  15.973 33.264 16.225 33.576 ;
     RECT  15.941 7.248 16.261 7.464 ;
     RECT  15.937 8.592 16.261 8.616 ;
     RECT  15.973 31.584 16.261 31.944 ;
     RECT  16.225 33.264 16.261 33.816 ;
     RECT  15.731 37.2 16.357 38.712 ;
     RECT  15.725 14.208 16.364 15.192 ;
     RECT  15.077 16.224 16.364 16.248 ;
     RECT  15.395 1.728 16.441 4.152 ;
     RECT  15.731 5.136 16.441 6.072 ;
     RECT  16.261 7.248 16.441 8.616 ;
     RECT  16.225 18.192 16.492 25.464 ;
     RECT  15.973 30.048 16.549 30.072 ;
     RECT  16.261 31.248 16.549 33.816 ;
     RECT  16.357 37.2 16.553 39.336 ;
     RECT  16.549 30.048 16.595 33.816 ;
     RECT  16.069 0.096 16.661 0.168 ;
     RECT  15.925 26.448 16.729 26.472 ;
     RECT  16.124 27.648 16.729 27.912 ;
     RECT  16.364 14.208 16.733 16.248 ;
     RECT  16.733 14.592 16.801 16.248 ;
     RECT  15.731 35.328 16.873 35.976 ;
     RECT  16.553 37.2 16.873 37.464 ;
     RECT  16.115 40.464 16.979 41.016 ;
     RECT  16.801 14.592 16.981 16.44 ;
     RECT  16.553 38.544 17.029 39.336 ;
     RECT  16.979 40.464 17.029 40.968 ;
     RECT  16.441 1.728 17.053 6.072 ;
     RECT  16.441 7.248 17.053 8.856 ;
     RECT  16.873 35.328 17.161 37.464 ;
     RECT  16.661 0.144 17.201 0.168 ;
     RECT  17.029 38.544 17.237 40.968 ;
     RECT  16.981 14.592 17.377 17.112 ;
     RECT  16.492 18.192 17.377 18.84 ;
     RECT  17.053 1.728 17.381 8.952 ;
     RECT  17.377 14.592 17.381 18.84 ;
     RECT  16.729 26.448 17.413 27.912 ;
     RECT  16.549 28.992 17.413 29.016 ;
     RECT  16.595 30.528 17.417 33.816 ;
     RECT  17.381 8.736 17.557 8.952 ;
     RECT  15.581 11.664 17.66 11.688 ;
     RECT  17.161 34.848 17.701 37.464 ;
     RECT  17.701 34.8 17.737 37.464 ;
     RECT  17.237 38.544 17.737 40.92 ;
     RECT  15.725 13.056 17.773 13.08 ;
     RECT  16.492 19.824 17.845 25.464 ;
     RECT  17.413 26.448 17.845 29.016 ;
     RECT  17.66 11.664 17.852 11.976 ;
     RECT  17.773 13.056 17.852 13.608 ;
     RECT  17.852 11.664 18.061 13.608 ;
     RECT  17.381 14.592 18.061 16.536 ;
     RECT  16.837 42.144 18.173 42.168 ;
     RECT  17.557 8.736 18.277 10.392 ;
     RECT  18.061 11.664 18.277 16.536 ;
     RECT  17.381 18 18.469 18.84 ;
     RECT  17.845 19.824 18.469 29.016 ;
     RECT  17.381 2.208 18.608 7.416 ;
     RECT  18.277 8.736 18.608 16.536 ;
     RECT  18.469 18 18.608 29.016 ;
     RECT  17.417 30.624 18.608 33.816 ;
     RECT  17.737 34.8 18.608 40.92 ;
     RECT  18.608 2.148 18.712 41.052 ;
     RECT  18.712 2.418 18.904 40.782 ;
     RECT  18.904 4.176 19.001 7.08 ;
     RECT  19.001 4.224 19.073 7.08 ;
     RECT  18.904 18.768 19.091 27.96 ;
     RECT  18.904 36.096 19.325 40.68 ;
     RECT  19.325 36.288 19.397 40.68 ;
     RECT  19.397 36.288 19.433 39.048 ;
     RECT  19.091 18.864 19.475 27.96 ;
     RECT  18.904 13.056 19.505 17.496 ;
     RECT  19.433 36.336 19.505 39.048 ;
     RECT  19.397 40.656 19.505 40.68 ;
     RECT  19.475 21.216 19.541 27.96 ;
     RECT  19.501 1.152 19.573 1.176 ;
     RECT  19.541 21.36 19.577 27.96 ;
     RECT  19.505 36.816 19.577 39.048 ;
     RECT  19.573 0.528 19.609 1.176 ;
     RECT  18.904 30.624 19.649 31.8 ;
     RECT  19.577 21.36 19.721 26.76 ;
     RECT  19.577 37.152 19.829 39.048 ;
     RECT  19.609 0.144 19.861 1.176 ;
     RECT  19.649 30.624 19.957 31.368 ;
     RECT  18.904 32.976 19.969 33.816 ;
     RECT  19.505 15.36 19.973 17.496 ;
     RECT  19.829 38.016 19.973 39.048 ;
     RECT  19.957 30.192 20.053 31.368 ;
     RECT  18.904 9.072 20.108 11.976 ;
     RECT  19.505 13.056 20.108 14.184 ;
     RECT  19.475 18.864 20.149 20.088 ;
     RECT  20.053 29.76 20.257 31.368 ;
     RECT  19.721 24.432 20.284 26.76 ;
     RECT  20.108 9.072 20.293 14.184 ;
     RECT  20.257 29.184 20.329 31.368 ;
     RECT  19.973 38.256 20.405 39.048 ;
     RECT  19.577 27.84 20.473 27.96 ;
     RECT  20.329 29.088 20.473 31.368 ;
     RECT  20.405 39.024 20.477 39.048 ;
     RECT  19.073 4.224 20.513 6.024 ;
     RECT  20.473 27.84 20.524 31.368 ;
     RECT  20.293 8.544 20.549 14.184 ;
     RECT  20.549 9.072 20.581 14.184 ;
     RECT  20.149 18.816 20.617 20.088 ;
     RECT  19.969 32.448 20.621 33.816 ;
     RECT  20.524 28.512 20.689 31.368 ;
     RECT  20.617 18.72 20.725 20.088 ;
     RECT  19.721 21.36 20.725 23.448 ;
     RECT  20.689 28.512 21.017 31.944 ;
     RECT  19.973 15.744 21.049 17.496 ;
     RECT  20.725 18.72 21.049 23.448 ;
     RECT  20.621 32.976 21.107 33.816 ;
     RECT  20.284 24.432 21.125 25.704 ;
     RECT  21.125 24.432 21.197 24.648 ;
     RECT  20.513 5.328 21.265 6.024 ;
     RECT  19.073 7.056 21.265 7.08 ;
     RECT  20.581 9.072 21.269 14.424 ;
     RECT  21.269 14.16 21.301 14.424 ;
     RECT  21.049 15.744 21.301 23.448 ;
     RECT  21.269 9.072 21.341 12.984 ;
     RECT  19.861 0.096 21.349 1.176 ;
     RECT  20.365 2.256 21.349 2.28 ;
     RECT  21.017 29.232 21.413 31.944 ;
     RECT  21.301 14.16 21.449 23.448 ;
     RECT  21.349 0.096 21.521 2.28 ;
     RECT  21.521 0.096 21.629 0.6 ;
     RECT  20.653 3.408 21.683 3.432 ;
     RECT  21.341 9.072 21.697 11.928 ;
     RECT  21.449 17.424 21.731 23.448 ;
     RECT  21.697 8.4 21.875 11.928 ;
     RECT  21.449 14.16 21.875 16.248 ;
     RECT  21.731 17.424 21.875 18.888 ;
     RECT  21.629 0.096 21.971 0.552 ;
     RECT  20.284 26.736 21.973 26.76 ;
     RECT  21.949 27.936 21.973 27.96 ;
     RECT  21.875 10.992 21.989 11.928 ;
     RECT  21.973 26.736 22.019 27.96 ;
     RECT  21.521 1.728 22.021 2.28 ;
     RECT  22.019 27.6 22.06 27.96 ;
     RECT  21.875 14.16 22.061 16.008 ;
     RECT  22.057 4.128 22.093 4.152 ;
     RECT  21.265 5.328 22.093 7.08 ;
     RECT  22.093 4.128 22.129 7.08 ;
     RECT  21.875 8.4 22.129 9.912 ;
     RECT  22.129 4.128 22.133 9.912 ;
     RECT  21.875 17.616 22.205 18.888 ;
     RECT  22.021 1.728 22.213 2.328 ;
     RECT  21.731 20.4 22.213 23.448 ;
     RECT  22.133 4.128 22.259 9.048 ;
     RECT  22.259 4.128 22.3 7.272 ;
     RECT  21.413 29.664 22.309 31.944 ;
     RECT  21.107 32.976 22.309 33.432 ;
     RECT  22.259 8.4 22.313 9.048 ;
     RECT  21.197 24.528 22.345 24.648 ;
     RECT  21.125 25.68 22.345 25.704 ;
     RECT  22.309 29.664 22.355 33.432 ;
     RECT  22.355 32.496 22.421 33.432 ;
     RECT  22.345 24.528 22.429 25.704 ;
     RECT  22.061 14.16 22.493 15.336 ;
     RECT  22.205 17.952 22.493 18.888 ;
     RECT  22.213 20.4 22.493 23.544 ;
     RECT  21.971 0.096 22.565 0.168 ;
     RECT  22.565 0.144 22.673 0.168 ;
     RECT  22.213 1.728 22.745 2.76 ;
     RECT  21.341 12.96 22.745 12.984 ;
     RECT  22.745 1.776 22.813 2.76 ;
     RECT  22.06 27.888 22.885 27.96 ;
     RECT  22.3 4.128 22.921 6.84 ;
     RECT  22.493 20.736 22.925 23.544 ;
     RECT  22.355 29.664 22.931 30.888 ;
     RECT  22.849 16.944 22.961 16.968 ;
     RECT  22.885 27.888 22.972 28.488 ;
     RECT  22.493 14.448 22.997 15.336 ;
     RECT  22.925 23.376 23.029 23.544 ;
     RECT  22.429 24.528 23.029 24.648 ;
     RECT  22.493 18.816 23.101 18.888 ;
     RECT  22.813 1.776 23.137 2.856 ;
     RECT  23.137 1.776 23.389 2.904 ;
     RECT  22.921 3.936 23.389 6.84 ;
     RECT  23.101 18.816 23.605 19.272 ;
     RECT  23.569 31.92 23.857 31.944 ;
     RECT  23.029 23.376 23.929 24.648 ;
     RECT  22.429 25.68 23.929 25.704 ;
     RECT  23.893 26.736 23.929 26.76 ;
     RECT  23.893 9.888 23.965 9.912 ;
     RECT  23.929 42.144 23.965 42.168 ;
     RECT  23.965 9.792 24.001 9.912 ;
     RECT  23.389 1.776 24.008 6.84 ;
     RECT  22.313 8.4 24.008 8.616 ;
     RECT  24.001 9.792 24.008 10.152 ;
     RECT  21.989 11.184 24.008 11.928 ;
     RECT  22.997 14.448 24.008 15.24 ;
     RECT  23.317 17.04 24.008 17.064 ;
     RECT  23.605 18.192 24.008 19.272 ;
     RECT  22.925 20.736 24.008 22.392 ;
     RECT  23.929 23.376 24.008 26.76 ;
     RECT  22.972 27.888 24.008 27.912 ;
     RECT  22.931 30.048 24.008 30.888 ;
     RECT  23.857 31.92 24.008 31.992 ;
     RECT  22.421 32.976 24.008 33.432 ;
     RECT  23.965 41.616 24.008 42.168 ;
     RECT  24.008 1.776 24.041 42.168 ;
     RECT  24.041 1.872 24.304 42.168 ;
     RECT  24.304 8.496 24.365 8.52 ;
     RECT  24.304 23.952 24.401 26.232 ;
     RECT  24.304 31.968 24.437 31.992 ;
     RECT  24.304 41.568 24.466 42.168 ;
     RECT  24.304 1.872 24.545 6.024 ;
     RECT  24.304 9.792 24.617 9.912 ;
     RECT  24.545 2.304 24.653 6.024 ;
     RECT  24.466 41.568 24.659 42.216 ;
     RECT  24.653 4.992 24.725 6.024 ;
     RECT  24.304 12.768 24.761 13.128 ;
     RECT  24.304 16.224 24.761 19.272 ;
     RECT  24.725 5.76 24.833 6.024 ;
     RECT  24.304 14.208 24.833 14.76 ;
     RECT  24.761 12.816 24.905 13.128 ;
     RECT  24.833 6 25.013 6.024 ;
     RECT  24.617 9.792 25.085 9.816 ;
     RECT  24.905 13.104 25.085 13.128 ;
     RECT  24.761 16.224 25.121 18.84 ;
     RECT  24.833 14.448 25.193 14.76 ;
     RECT  24.659 41.568 25.34 42.168 ;
     RECT  25.121 16.512 25.373 18.84 ;
     RECT  24.401 24.624 25.397 26.232 ;
     RECT  24.304 30.048 25.405 30.888 ;
     RECT  24.304 20.64 25.409 20.664 ;
     RECT  25.34 41.04 25.427 42.168 ;
     RECT  25.397 24.624 25.481 26.808 ;
     RECT  24.653 2.304 25.517 3.96 ;
     RECT  25.405 28.416 25.589 28.44 ;
     RECT  25.517 2.304 25.661 2.328 ;
     RECT  24.304 21.744 25.693 22.632 ;
     RECT  25.517 3.312 25.697 3.96 ;
     RECT  25.481 24.624 25.729 26.232 ;
     RECT  25.697 3.312 25.769 3.336 ;
     RECT  25.693 21.744 25.805 22.872 ;
     RECT  25.373 16.512 25.877 16.68 ;
     RECT  25.805 22.848 25.877 22.872 ;
     RECT  25.868 14.88 25.909 14.904 ;
     RECT  25.805 21.744 25.949 21.768 ;
     RECT  25.333 6.816 25.955 6.84 ;
     RECT  25.909 14.88 25.955 15.48 ;
     RECT  25.877 16.656 25.985 16.68 ;
     RECT  25.405 30.048 26.017 30.984 ;
     RECT  25.427 41.568 26.125 42.168 ;
     RECT  25.477 20.544 26.237 20.568 ;
     RECT  25.373 17.664 26.243 18.84 ;
     RECT  25.955 15.456 26.309 15.48 ;
     RECT  26.243 18.576 26.417 18.84 ;
     RECT  26.417 18.576 26.525 18.6 ;
     RECT  25.729 24.48 26.525 26.232 ;
     RECT  25.801 39.6 26.593 39.624 ;
     RECT  26.525 24.48 26.669 25.272 ;
     RECT  26.629 11.76 26.741 11.784 ;
     RECT  26.125 41.568 26.771 42.84 ;
     RECT  26.017 30.048 26.813 31.848 ;
     RECT  26.593 38.688 26.845 39.768 ;
     RECT  26.771 41.568 26.845 42.12 ;
     RECT  26.813 30.048 27.205 30.888 ;
     RECT  26.845 38.688 27.347 42.12 ;
     RECT  24.304 32.976 27.529 33.432 ;
     RECT  26.669 24.48 27.601 24.504 ;
     RECT  27.601 23.616 27.637 24.504 ;
     RECT  27.205 29.808 27.853 30.888 ;
     RECT  27.853 29.616 27.877 30.888 ;
     RECT  27.529 32.4 27.893 34.2 ;
     RECT  27.637 23.616 27.965 24.984 ;
     RECT  27.893 32.448 28.105 34.2 ;
     RECT  27.965 24.48 28.145 24.984 ;
     RECT  27.877 29.616 28.253 30.936 ;
     RECT  27.347 38.832 28.393 42.12 ;
     RECT  27.601 18.528 28.433 18.552 ;
     RECT  28.393 38.736 28.465 42.12 ;
     RECT  28.253 30.816 28.501 30.936 ;
     RECT  28.105 32.448 28.501 34.344 ;
     RECT  28.465 38.736 28.645 42.168 ;
     RECT  27.301 37.2 28.753 37.224 ;
     RECT  28.753 36.912 28.897 37.224 ;
     RECT  28.645 38.688 28.969 42.168 ;
     RECT  28.969 38.688 29.077 42.264 ;
     RECT  29.077 38.688 29.149 43.176 ;
     RECT  28.897 36 29.18 37.224 ;
     RECT  29.149 38.256 29.18 43.176 ;
     RECT  28.465 27.6 29.293 27.624 ;
     RECT  28.501 30.816 29.401 31.128 ;
     RECT  28.501 32.448 29.401 34.488 ;
     RECT  29.149 23.952 29.408 23.976 ;
     RECT  28.145 24.96 29.408 24.984 ;
     RECT  29.293 27.6 29.408 28.536 ;
     RECT  28.253 29.616 29.408 29.832 ;
     RECT  29.401 30.816 29.408 34.488 ;
     RECT  29.18 36 29.408 43.176 ;
     RECT  29.408 2.148 29.512 43.176 ;
     RECT  29.512 2.418 29.704 43.176 ;
     RECT  29.704 29.616 29.765 31.944 ;
     RECT  29.704 26.784 29.873 28.536 ;
     RECT  29.704 23.952 30.297 24.552 ;
     RECT  29.873 27.84 30.341 28.536 ;
     RECT  29.765 30.048 30.769 31.944 ;
     RECT  30.769 29.856 30.877 31.944 ;
     RECT  29.704 32.976 30.877 43.176 ;
     RECT  29.873 26.784 31.093 26.808 ;
     RECT  30.341 27.84 31.093 27.912 ;
     RECT  31.093 26.784 31.129 27.912 ;
     RECT  31.129 26.64 31.133 27.912 ;
     RECT  31.133 26.64 31.196 27.288 ;
     RECT  31.196 26.592 31.283 27.288 ;
     RECT  30.877 29.856 31.561 43.176 ;
     RECT  31.283 26.64 31.565 27.288 ;
     RECT  30.297 24.528 31.817 24.552 ;
     RECT  31.565 26.736 31.961 27.288 ;
     RECT  31.561 28.992 32.243 43.176 ;
     RECT  31.961 27.264 32.425 27.288 ;
     RECT  32.425 27.264 32.531 27.816 ;
     RECT  32.531 27.36 32.723 27.816 ;
     RECT  32.243 28.992 32.819 42.072 ;
     RECT  32.819 28.992 33.005 42.024 ;
     RECT  33.005 29.52 33.011 42.024 ;
     RECT  32.243 43.056 33.077 43.176 ;
     RECT  33.077 43.056 33.121 43.08 ;
     RECT  33.011 29.52 33.203 41.064 ;
     RECT  33.203 29.52 33.491 40.632 ;
     RECT  32.723 27.36 33.581 27.624 ;
     RECT  33.581 27.6 34.808 27.624 ;
     RECT  33.491 29.52 34.808 40.392 ;
     RECT  34.808 2.148 34.912 41.052 ;
     RECT  34.912 2.418 35.104 41.052 ;
     RECT  35.104 28.944 35.485 41.052 ;
     RECT  35.485 28.944 35.525 41.352 ;
     RECT  35.525 30.048 35.669 41.352 ;
     RECT  35.669 30.24 35.885 41.352 ;
     RECT  35.104 27.6 35.939 27.624 ;
     RECT  35.525 28.944 35.98 28.968 ;
     RECT  35.885 41.136 36.205 41.352 ;
     RECT  35.885 30.24 37.753 39.864 ;
     RECT  36.205 41.136 37.753 41.832 ;
     RECT  37.753 30.24 37.969 41.832 ;
     RECT  37.969 30.048 38.833 41.832 ;
     RECT  38.833 29.808 39.157 41.832 ;
     RECT  39.157 29.808 39.829 42.024 ;
     RECT  39.781 28.272 39.98 28.296 ;
     RECT  39.829 29.376 39.98 42.024 ;
     RECT  39.98 28.272 40.021 42.024 ;
     RECT  40.021 27.888 40.069 42.024 ;
     RECT  40.069 27.216 40.208 42.024 ;
     RECT  40.208 2.148 40.312 42.024 ;
     RECT  40.312 2.418 40.504 42.024 ;
     RECT  40.504 27.888 40.643 42.024 ;
     RECT  40.504 26.64 40.739 26.664 ;
     RECT  40.643 27.888 40.883 38.28 ;
     RECT  40.883 27.888 40.931 27.912 ;
     RECT  40.643 39.6 41.389 42.024 ;
     RECT  41.389 39.6 41.857 42.12 ;
     RECT  40.883 29.136 42.793 38.28 ;
     RECT  41.857 39.504 42.793 42.12 ;
     RECT  42.793 29.136 43.116 29.16 ;
     RECT  42.793 29.16 43.164 29.232 ;
     RECT  42.793 29.232 43.116 29.256 ;
     RECT  42.793 29.256 43.164 29.328 ;
     RECT  42.793 29.328 43.116 29.352 ;
     RECT  42.793 29.352 43.164 29.424 ;
     RECT  42.793 29.424 43.116 29.448 ;
     RECT  42.793 29.448 43.164 29.52 ;
     RECT  42.793 29.52 43.116 29.544 ;
     RECT  42.793 29.544 43.164 29.616 ;
     RECT  42.793 29.616 43.116 29.64 ;
     RECT  42.793 29.64 43.164 29.712 ;
     RECT  42.793 29.712 43.116 29.736 ;
     RECT  42.793 29.736 43.164 29.808 ;
     RECT  42.793 29.808 43.116 29.832 ;
     RECT  42.793 29.832 43.164 29.904 ;
     RECT  42.793 29.904 43.116 29.928 ;
     RECT  42.793 29.928 43.164 30 ;
     RECT  42.793 30 43.116 30.024 ;
     RECT  42.793 30.024 43.164 30.096 ;
     RECT  42.793 30.096 43.116 30.12 ;
     RECT  42.793 30.12 43.164 30.192 ;
     RECT  42.793 30.192 43.116 30.216 ;
     RECT  42.793 30.216 43.164 30.288 ;
     RECT  42.793 30.288 43.116 30.312 ;
     RECT  42.793 30.312 43.164 30.384 ;
     RECT  42.793 30.384 43.116 30.408 ;
     RECT  42.793 30.408 43.164 30.48 ;
     RECT  42.793 30.48 43.116 30.504 ;
     RECT  42.793 30.504 43.164 30.576 ;
     RECT  42.793 30.576 43.116 30.6 ;
     RECT  42.793 30.6 43.164 30.672 ;
     RECT  42.793 30.672 43.116 30.696 ;
     RECT  42.793 30.696 43.164 30.768 ;
     RECT  42.793 30.768 43.116 30.792 ;
     RECT  42.793 30.792 43.164 30.864 ;
     RECT  42.793 30.864 43.116 30.888 ;
     RECT  42.793 30.888 43.164 30.96 ;
     RECT  42.793 30.96 43.116 30.984 ;
     RECT  42.793 30.984 43.164 31.056 ;
     RECT  42.793 31.056 43.116 31.08 ;
     RECT  42.793 31.08 43.164 31.152 ;
     RECT  42.793 31.152 43.116 31.176 ;
     RECT  42.793 31.176 43.164 31.248 ;
     RECT  42.793 31.248 43.116 31.272 ;
     RECT  42.793 31.272 43.164 31.344 ;
     RECT  42.793 31.344 43.116 31.368 ;
     RECT  42.793 31.368 43.164 32.208 ;
     RECT  42.793 32.208 43.116 32.232 ;
     RECT  42.793 32.232 43.164 32.304 ;
     RECT  42.793 32.304 43.116 32.328 ;
     RECT  42.793 32.328 43.164 32.4 ;
     RECT  42.793 32.4 43.116 32.424 ;
     RECT  42.793 32.424 43.164 32.496 ;
     RECT  42.793 32.496 43.116 32.52 ;
     RECT  42.793 32.52 43.164 32.592 ;
     RECT  42.793 32.592 43.116 32.616 ;
     RECT  42.793 32.616 43.164 32.688 ;
     RECT  42.793 32.688 43.116 32.712 ;
     RECT  42.793 32.712 43.164 32.784 ;
     RECT  42.793 32.784 43.116 32.808 ;
     RECT  42.793 32.808 43.164 32.88 ;
     RECT  42.793 32.88 43.116 32.904 ;
     RECT  42.793 32.904 43.164 32.976 ;
     RECT  42.793 32.976 43.116 33 ;
     RECT  42.793 33 43.164 33.072 ;
     RECT  42.793 33.072 43.116 33.096 ;
     RECT  42.793 33.096 43.164 33.168 ;
     RECT  42.793 33.168 43.116 33.192 ;
     RECT  42.793 33.192 43.164 33.264 ;
     RECT  42.793 33.264 43.116 33.288 ;
     RECT  42.793 33.288 43.164 33.36 ;
     RECT  42.793 33.36 43.116 33.384 ;
     RECT  42.793 33.384 43.164 33.456 ;
     RECT  42.793 33.456 43.116 33.48 ;
     RECT  42.793 33.48 43.164 33.552 ;
     RECT  42.793 33.552 43.116 33.576 ;
     RECT  42.793 33.576 43.164 33.648 ;
     RECT  42.793 33.648 43.116 33.672 ;
     RECT  42.793 33.672 43.164 33.744 ;
     RECT  42.793 33.744 43.116 33.768 ;
     RECT  42.793 33.768 43.164 33.84 ;
     RECT  42.793 33.84 43.116 33.864 ;
     RECT  42.793 33.864 43.164 33.936 ;
     RECT  42.793 33.936 43.116 33.96 ;
     RECT  42.793 33.96 43.164 34.032 ;
     RECT  42.793 34.032 43.116 34.056 ;
     RECT  42.793 34.056 43.164 34.128 ;
     RECT  42.793 34.128 43.116 34.152 ;
     RECT  42.793 34.152 43.164 34.224 ;
     RECT  42.793 34.224 43.116 34.248 ;
     RECT  42.793 34.248 43.164 34.32 ;
     RECT  42.793 34.32 43.116 34.344 ;
     RECT  42.793 34.344 43.164 34.416 ;
     RECT  42.793 34.416 43.116 34.44 ;
     RECT  42.793 34.44 43.164 34.512 ;
     RECT  42.793 34.512 43.116 34.536 ;
     RECT  42.793 34.536 43.164 34.608 ;
     RECT  42.793 34.608 43.116 34.632 ;
     RECT  42.793 34.632 43.164 34.704 ;
     RECT  42.793 34.704 43.116 34.728 ;
     RECT  42.793 34.728 43.164 34.8 ;
     RECT  42.793 34.8 43.116 34.824 ;
     RECT  42.793 34.824 43.164 34.896 ;
     RECT  42.793 34.896 43.116 34.92 ;
     RECT  42.793 34.92 43.164 34.992 ;
     RECT  42.793 34.992 43.116 35.016 ;
     RECT  42.793 35.016 43.164 35.088 ;
     RECT  42.793 35.088 43.116 35.112 ;
     RECT  42.793 35.112 43.164 35.184 ;
     RECT  42.793 35.184 43.116 35.208 ;
     RECT  42.793 35.208 43.164 35.28 ;
     RECT  42.793 35.28 43.116 35.304 ;
     RECT  42.793 35.304 43.164 35.376 ;
     RECT  42.793 35.376 43.116 35.4 ;
     RECT  42.793 35.4 43.164 35.472 ;
     RECT  42.793 35.472 43.116 35.496 ;
     RECT  42.793 35.496 43.164 35.568 ;
     RECT  42.793 35.568 43.116 35.592 ;
     RECT  42.793 35.592 43.164 35.664 ;
     RECT  42.793 35.664 43.116 35.688 ;
     RECT  42.793 35.688 43.164 35.76 ;
     RECT  42.793 35.76 43.116 35.784 ;
     RECT  42.793 35.784 43.164 35.856 ;
     RECT  42.793 35.856 43.116 35.88 ;
     RECT  42.793 35.88 43.164 35.952 ;
     RECT  42.793 35.952 43.116 35.976 ;
     RECT  42.793 35.976 43.164 36.048 ;
     RECT  42.793 36.048 43.116 36.072 ;
     RECT  42.793 36.072 43.164 36.144 ;
     RECT  42.793 36.144 43.116 36.168 ;
     RECT  42.793 36.168 43.164 36.24 ;
     RECT  42.793 36.24 43.116 36.264 ;
     RECT  42.793 36.264 43.164 36.336 ;
     RECT  42.793 36.336 43.116 36.36 ;
     RECT  42.793 36.36 43.164 36.432 ;
     RECT  42.793 36.432 43.116 36.456 ;
     RECT  42.793 36.456 43.164 36.528 ;
     RECT  42.793 36.528 43.116 36.552 ;
     RECT  42.793 36.552 43.164 36.624 ;
     RECT  42.793 36.624 43.116 36.648 ;
     RECT  42.793 36.648 43.164 36.72 ;
     RECT  42.793 36.72 43.116 36.744 ;
     RECT  42.793 36.744 43.164 36.816 ;
     RECT  42.793 36.816 43.116 36.84 ;
     RECT  42.793 36.84 43.164 36.912 ;
     RECT  42.793 36.912 43.116 36.936 ;
     RECT  42.793 36.936 43.164 37.008 ;
     RECT  42.793 37.008 43.116 37.032 ;
     RECT  42.793 37.032 43.164 37.104 ;
     RECT  42.793 37.104 43.116 37.128 ;
     RECT  42.793 37.128 43.164 37.2 ;
     RECT  42.793 37.2 43.116 37.224 ;
     RECT  42.793 37.224 43.164 37.296 ;
     RECT  42.793 37.296 43.116 37.32 ;
     RECT  42.793 37.32 43.164 37.392 ;
     RECT  42.793 37.392 43.116 37.416 ;
     RECT  42.793 37.416 43.164 37.488 ;
     RECT  42.793 37.488 43.116 37.512 ;
     RECT  42.793 37.512 43.164 37.584 ;
     RECT  42.793 37.584 43.116 37.608 ;
     RECT  42.793 37.608 43.164 37.68 ;
     RECT  42.793 37.68 43.116 37.704 ;
     RECT  42.793 37.704 43.164 37.776 ;
     RECT  42.793 37.776 43.116 37.8 ;
     RECT  42.793 37.8 43.164 37.872 ;
     RECT  42.793 37.872 43.116 37.896 ;
     RECT  42.793 37.896 43.164 37.968 ;
     RECT  42.793 37.968 43.116 37.992 ;
     RECT  42.793 37.992 43.164 38.064 ;
     RECT  42.793 38.064 43.116 38.088 ;
     RECT  42.793 38.088 43.164 38.16 ;
     RECT  42.793 38.16 43.116 38.184 ;
     RECT  42.793 38.184 43.164 38.256 ;
     RECT  42.793 38.256 43.116 38.28 ;
     RECT  42.793 38.28 43.164 39.12 ;
     RECT  42.793 39.12 43.116 39.144 ;
     RECT  42.793 39.144 43.164 39.216 ;
     RECT  42.793 39.216 43.116 39.24 ;
     RECT  42.793 39.24 43.164 39.312 ;
     RECT  42.793 39.312 43.116 39.336 ;
     RECT  42.793 39.336 43.164 39.408 ;
     RECT  42.793 39.408 43.116 39.432 ;
     RECT  42.793 39.432 43.164 39.504 ;
     RECT  42.793 39.504 43.116 39.528 ;
     RECT  42.793 39.528 43.164 39.6 ;
     RECT  42.793 39.6 43.116 39.624 ;
     RECT  42.793 39.624 43.164 39.696 ;
     RECT  42.793 39.696 43.116 39.72 ;
     RECT  42.793 39.72 43.164 39.792 ;
     RECT  42.793 39.792 43.116 39.816 ;
     RECT  42.793 39.816 43.164 39.888 ;
     RECT  42.793 39.888 43.116 39.912 ;
     RECT  42.793 39.912 43.164 39.984 ;
     RECT  42.793 39.984 43.116 40.008 ;
     RECT  42.793 40.008 43.164 40.08 ;
     RECT  42.793 40.08 43.116 40.104 ;
     RECT  42.793 40.104 43.164 40.176 ;
     RECT  42.793 40.176 43.116 40.2 ;
     RECT  42.793 40.2 43.164 40.272 ;
     RECT  42.793 40.272 43.116 40.296 ;
     RECT  42.793 40.296 43.164 40.368 ;
     RECT  42.793 40.368 43.116 40.392 ;
     RECT  42.793 40.392 43.164 40.464 ;
     RECT  42.793 40.464 43.116 40.488 ;
     RECT  42.793 40.488 43.164 40.56 ;
     RECT  42.793 40.56 43.116 40.584 ;
     RECT  42.793 40.584 43.164 40.656 ;
     RECT  42.793 40.656 43.116 40.68 ;
     RECT  42.793 40.68 43.164 40.752 ;
     RECT  42.793 40.752 43.116 40.776 ;
     RECT  42.793 40.776 43.164 40.848 ;
     RECT  42.793 40.848 43.116 40.872 ;
     RECT  42.793 40.872 43.164 40.944 ;
     RECT  42.793 40.944 43.116 40.968 ;
     RECT  42.793 40.968 43.164 41.04 ;
     RECT  42.793 41.04 43.116 41.064 ;
     RECT  42.793 41.064 43.164 41.136 ;
     RECT  42.793 41.136 43.116 41.16 ;
     RECT  42.793 41.16 43.164 41.232 ;
     RECT  42.793 41.232 43.116 41.256 ;
     RECT  42.793 41.256 43.164 41.328 ;
     RECT  42.793 41.328 43.116 41.352 ;
     RECT  42.793 41.352 43.164 41.424 ;
     RECT  42.793 41.424 43.116 41.448 ;
     RECT  42.793 41.448 43.164 41.52 ;
     RECT  42.793 41.52 43.116 41.544 ;
     RECT  42.793 41.544 43.164 41.616 ;
     RECT  42.793 41.616 43.116 41.64 ;
     RECT  42.793 41.64 43.164 41.712 ;
     RECT  42.793 41.712 43.116 41.736 ;
     RECT  42.793 41.736 43.164 41.808 ;
     RECT  42.793 41.808 43.116 41.832 ;
     RECT  42.793 41.832 43.164 41.904 ;
     RECT  42.793 41.904 43.116 41.928 ;
     RECT  42.793 41.928 43.164 42 ;
     RECT  42.793 42 43.116 42.024 ;
     RECT  42.793 42.024 43.164 42.096 ;
     RECT  42.793 42.096 43.116 42.12 ;
    LAYER M5 ;
     RECT  13.032 0.016 13.104 0.084 ;
     RECT  13.128 0.016 13.2 0.084 ;
     RECT  13.224 0.016 13.296 0.084 ;
     RECT  13.32 0.016 13.392 0.084 ;
     RECT  13.416 0.016 13.488 0.084 ;
     RECT  13.512 0.016 13.584 0.084 ;
     RECT  13.608 0.016 13.68 0.084 ;
     RECT  13.704 0.016 13.776 0.084 ;
     RECT  13.8 0.016 13.872 0.084 ;
     RECT  13.896 0.016 13.968 0.084 ;
     RECT  13.992 0.016 14.064 0.084 ;
     RECT  14.088 0.016 14.16 0.084 ;
     RECT  14.184 0.016 14.256 0.084 ;
     RECT  14.28 0.016 14.352 0.084 ;
     RECT  14.376 0.016 14.448 0.084 ;
     RECT  14.472 0.016 14.544 0.084 ;
     RECT  14.568 0.016 14.64 0.084 ;
     RECT  14.664 0.016 14.736 0.084 ;
     RECT  14.76 0.016 14.832 0.084 ;
     RECT  14.856 0.016 14.928 0.084 ;
     RECT  14.952 0.016 15.024 0.084 ;
     RECT  15.048 0.016 15.12 0.084 ;
     RECT  15.144 0.016 15.216 0.084 ;
     RECT  15.24 0.016 15.312 0.084 ;
     RECT  15.336 0.016 15.408 0.084 ;
     RECT  15.432 0.016 15.504 0.084 ;
     RECT  15.528 0.016 15.6 0.084 ;
     RECT  15.624 0.016 15.696 0.084 ;
     RECT  15.72 0.016 15.792 0.084 ;
     RECT  15.816 0.016 15.888 0.084 ;
     RECT  15.912 0.016 15.984 0.084 ;
     RECT  16.008 0.016 16.08 0.084 ;
     RECT  16.104 0.016 16.176 0.084 ;
     RECT  16.2 0.016 16.272 0.084 ;
     RECT  16.296 0.016 16.368 0.084 ;
     RECT  13.008 0.084 16.392 0.131 ;
     RECT  19.944 0.016 20.016 0.084 ;
     RECT  20.04 0.016 20.112 0.084 ;
     RECT  20.136 0.016 20.208 0.084 ;
     RECT  20.232 0.016 20.304 0.084 ;
     RECT  20.328 0.016 20.4 0.084 ;
     RECT  20.424 0.016 20.496 0.084 ;
     RECT  20.52 0.016 20.592 0.084 ;
     RECT  20.616 0.016 20.688 0.084 ;
     RECT  20.712 0.016 20.784 0.084 ;
     RECT  20.808 0.016 20.88 0.084 ;
     RECT  20.904 0.016 20.976 0.084 ;
     RECT  21 0.016 21.072 0.084 ;
     RECT  21.096 0.016 21.168 0.084 ;
     RECT  21.192 0.016 21.264 0.084 ;
     RECT  21.288 0.016 21.36 0.084 ;
     RECT  21.384 0.016 21.456 0.084 ;
     RECT  21.48 0.016 21.552 0.084 ;
     RECT  21.576 0.016 21.648 0.084 ;
     RECT  21.672 0.016 21.744 0.084 ;
     RECT  21.768 0.016 21.84 0.084 ;
     RECT  21.864 0.016 21.936 0.084 ;
     RECT  21.96 0.016 22.032 0.084 ;
     RECT  22.056 0.016 22.128 0.084 ;
     RECT  22.152 0.016 22.224 0.084 ;
     RECT  22.248 0.016 22.32 0.084 ;
     RECT  22.344 0.016 22.416 0.084 ;
     RECT  22.44 0.016 22.512 0.084 ;
     RECT  22.536 0.016 22.608 0.084 ;
     RECT  22.632 0.016 22.704 0.084 ;
     RECT  22.728 0.016 22.8 0.084 ;
     RECT  22.824 0.016 22.896 0.084 ;
     RECT  19.92 0.084 22.92 0.131 ;
     RECT  13.104 0.131 16.392 0.227 ;
     RECT  13.2 0.227 16.392 0.611 ;
     RECT  20.016 0.131 22.92 1.187 ;
     RECT  13.392 0.611 16.392 1.907 ;
     RECT  13.392 1.907 14.088 1.955 ;
     RECT  13.392 1.955 13.656 2.137 ;
     RECT  2.4 2.137 2.52 2.151 ;
     RECT  7.8 2.137 7.92 2.151 ;
     RECT  18.6 2.137 18.72 2.151 ;
     RECT  24 2.137 24.12 2.151 ;
     RECT  29.4 2.137 29.52 2.151 ;
     RECT  34.8 2.137 34.92 2.151 ;
     RECT  40.2 2.137 40.32 2.151 ;
     RECT  18.6 2.151 18.912 2.197 ;
     RECT  20.592 1.187 22.92 2.291 ;
     RECT  21.648 2.291 22.92 2.339 ;
     RECT  21.648 2.339 22.824 2.579 ;
     RECT  21.648 2.579 22.248 2.771 ;
     RECT  5.184 2.485 5.208 2.963 ;
     RECT  13.2 2.137 13.656 3.397 ;
     RECT  16.608 2.197 17.016 3.443 ;
     RECT  21.648 2.771 21.672 3.443 ;
     RECT  15.216 1.907 15.576 3.875 ;
     RECT  0.144 2.533 0.168 3.923 ;
     RECT  7.8 2.151 8.112 3.925 ;
     RECT  18 2.197 18.912 4.019 ;
     RECT  18.6 4.019 18.912 4.501 ;
     RECT  16.608 3.443 16.968 4.595 ;
     RECT  15.264 3.875 15.576 4.643 ;
     RECT  6.192 3.637 6.216 4.837 ;
     RECT  16.944 4.595 16.968 4.837 ;
     RECT  7.8 3.925 9.096 4.933 ;
     RECT  7.392 4.933 9.096 5.077 ;
     RECT  15.312 4.643 15.576 5.171 ;
     RECT  4.512 3.397 4.536 5.267 ;
     RECT  7.392 5.077 9.672 5.269 ;
     RECT  0.144 5.221 0.168 5.411 ;
     RECT  0.288 5.509 0.312 5.651 ;
     RECT  13.2 3.397 14.232 5.795 ;
     RECT  7.248 5.269 9.672 6.229 ;
     RECT  15.312 5.171 15.336 6.229 ;
     RECT  13.2 5.795 13.656 6.373 ;
     RECT  5.52 4.837 6.216 6.661 ;
     RECT  13.104 6.373 13.656 6.709 ;
     RECT  2.4 2.151 2.712 6.853 ;
     RECT  15.312 6.229 15.72 6.899 ;
     RECT  2.304 6.853 2.712 6.995 ;
     RECT  16.944 4.837 17.4 7.141 ;
     RECT  18.6 4.501 19.224 7.141 ;
     RECT  13.008 6.709 13.656 7.189 ;
     RECT  15.456 6.899 15.72 7.475 ;
     RECT  11.664 2.821 11.688 7.621 ;
     RECT  11.664 7.621 11.976 7.667 ;
     RECT  22.224 7.237 22.248 8.003 ;
     RECT  11.952 7.667 11.976 8.149 ;
     RECT  13.008 7.189 14.376 8.149 ;
     RECT  0.144 6.565 0.168 8.387 ;
     RECT  5.424 6.661 6.216 8.677 ;
     RECT  7.248 6.229 9.768 8.677 ;
     RECT  5.424 8.677 9.768 8.819 ;
     RECT  0.144 9.397 0.168 9.587 ;
     RECT  16.944 7.141 19.224 9.731 ;
     RECT  18.192 9.731 19.224 10.357 ;
     RECT  11.952 8.149 14.376 10.739 ;
     RECT  11.952 10.739 13.848 11.171 ;
     RECT  2.4 6.995 2.712 11.269 ;
     RECT  4.272 8.341 4.296 11.269 ;
     RECT  5.424 8.819 8.112 11.317 ;
     RECT  9.12 8.819 9.768 11.317 ;
     RECT  5.424 11.317 9.768 11.411 ;
     RECT  15.696 7.475 15.72 11.509 ;
     RECT  12 11.171 13.848 11.941 ;
     RECT  16.944 9.731 16.968 11.941 ;
     RECT  18.192 10.357 20.184 11.941 ;
     RECT  12 11.941 13.992 12.229 ;
     RECT  15.36 11.509 15.72 12.229 ;
     RECT  2.4 11.269 4.296 12.563 ;
     RECT  16.944 11.941 20.184 12.949 ;
     RECT  21.84 10.165 21.864 12.949 ;
     RECT  16.944 12.949 21.864 12.995 ;
     RECT  3.984 12.563 4.296 13.139 ;
     RECT  0.144 13.141 0.168 13.331 ;
     RECT  2.4 12.563 2.808 13.477 ;
     RECT  12 12.229 15.72 13.523 ;
     RECT  12 13.523 13.992 14.099 ;
     RECT  3.984 13.139 4.008 14.101 ;
     RECT  5.424 11.411 6.216 14.101 ;
     RECT  15.36 13.523 15.72 14.243 ;
     RECT  21.12 12.995 21.864 14.243 ;
     RECT  0.24 13.573 0.312 14.629 ;
     RECT  3.984 14.101 6.216 14.675 ;
     RECT  16.944 12.995 19.224 14.725 ;
     RECT  2.304 13.477 2.808 14.773 ;
     RECT  0.144 14.629 0.312 14.819 ;
     RECT  4.176 14.675 6.216 15.301 ;
     RECT  7.2 11.411 9.768 15.301 ;
     RECT  21.648 14.243 21.864 15.349 ;
     RECT  2.304 14.773 2.856 15.395 ;
     RECT  16.944 14.725 19.368 15.395 ;
     RECT  25.92 6.805 25.944 15.445 ;
     RECT  25.92 15.445 26.232 15.491 ;
     RECT  15.504 14.243 15.72 15.637 ;
     RECT  16.944 15.395 19.32 15.637 ;
     RECT  12.576 14.099 13.992 16.019 ;
     RECT  2.4 15.395 2.856 16.501 ;
     RECT  0.24 14.819 0.312 16.643 ;
     RECT  0.24 16.643 0.264 16.837 ;
     RECT  2.4 16.501 2.952 16.981 ;
     RECT  4.176 15.301 9.768 16.981 ;
     RECT  0.144 16.837 0.264 17.123 ;
     RECT  1.248 16.885 1.272 17.123 ;
     RECT  15.504 15.637 19.32 17.507 ;
     RECT  26.208 15.491 26.232 17.699 ;
     RECT  0.24 17.123 0.264 17.747 ;
     RECT  2.4 16.981 9.768 18.181 ;
     RECT  15.504 17.507 19.224 18.469 ;
     RECT  21.312 15.349 21.864 18.707 ;
     RECT  12.576 16.019 13.752 18.899 ;
     RECT  2.4 18.181 9.816 18.995 ;
     RECT  21.312 18.707 21.72 19.139 ;
     RECT  14.88 18.469 19.224 19.427 ;
     RECT  21.648 19.139 21.72 19.571 ;
     RECT  14.928 19.427 19.224 19.765 ;
     RECT  21.696 19.571 21.72 19.811 ;
     RECT  2.4 18.995 9.768 20.003 ;
     RECT  12.576 18.899 13.656 20.339 ;
     RECT  2.4 20.003 9.24 21.155 ;
     RECT  13.2 20.339 13.656 21.251 ;
     RECT  2.4 21.155 4.536 21.347 ;
     RECT  14.928 19.765 19.464 21.349 ;
     RECT  5.664 21.155 9.24 21.683 ;
     RECT  13.2 21.251 13.512 22.021 ;
     RECT  21.12 20.725 21.144 22.021 ;
     RECT  0.192 21.781 0.216 22.067 ;
     RECT  5.664 21.683 8.904 22.165 ;
     RECT  13.104 22.021 13.512 22.211 ;
     RECT  14.928 21.349 20.088 22.211 ;
     RECT  21.12 22.021 21.24 22.499 ;
     RECT  21.216 22.499 21.24 22.931 ;
     RECT  4.752 22.165 8.904 23.027 ;
     RECT  22.224 21.637 22.248 23.317 ;
     RECT  2.4 21.347 3.72 23.411 ;
     RECT  15.216 22.211 20.088 23.459 ;
     RECT  21.264 23.317 22.248 23.555 ;
     RECT  29.4 2.151 29.712 23.941 ;
     RECT  15.216 23.459 16.2 24.323 ;
     RECT  4.752 23.027 8.52 24.325 ;
     RECT  15.696 24.323 16.2 24.467 ;
     RECT  21.264 23.555 21.288 24.563 ;
     RECT  29.4 23.941 30.264 24.563 ;
     RECT  17.712 23.459 20.088 24.613 ;
     RECT  2.4 23.411 2.712 24.757 ;
     RECT  12.048 23.317 12.072 24.947 ;
     RECT  17.712 24.613 20.376 25.043 ;
     RECT  4.224 24.325 8.52 25.139 ;
     RECT  24 2.151 24.312 25.621 ;
     RECT  15.888 24.467 16.2 25.715 ;
     RECT  22.368 25.045 22.392 25.715 ;
     RECT  0.144 25.765 0.168 26.051 ;
     RECT  24 25.621 25.128 26.197 ;
     RECT  4.224 25.139 8.112 26.243 ;
     RECT  24 26.197 25.464 26.243 ;
     RECT  4.224 26.243 6.168 26.291 ;
     RECT  15.936 25.715 16.2 26.483 ;
     RECT  31.248 24.517 31.272 26.627 ;
     RECT  40.2 2.151 40.512 26.629 ;
     RECT  20.064 25.043 20.376 26.725 ;
     RECT  4.896 26.291 6.168 26.819 ;
     RECT  25.44 26.243 25.464 26.819 ;
     RECT  5.664 26.819 6.168 26.867 ;
     RECT  7.392 26.243 8.112 27.011 ;
     RECT  2.4 24.757 2.856 27.203 ;
     RECT  40.2 26.629 40.728 27.205 ;
     RECT  6.144 26.867 6.168 27.395 ;
     RECT  32.496 27.253 32.52 27.395 ;
     RECT  34.8 2.151 35.112 27.589 ;
     RECT  21.984 26.725 22.008 27.635 ;
     RECT  16.176 26.483 16.2 27.683 ;
     RECT  20.064 26.725 20.472 27.875 ;
     RECT  40.08 27.205 40.728 27.877 ;
     RECT  40.08 27.877 40.92 28.261 ;
     RECT  34.8 27.589 35.928 28.979 ;
     RECT  20.064 27.875 20.376 29.077 ;
     RECT  22.896 28.453 22.92 29.699 ;
     RECT  16.56 27.877 16.584 30.037 ;
     RECT  15.984 30.037 16.584 30.083 ;
     RECT  20.064 29.077 20.616 30.181 ;
     RECT  19.968 30.181 20.616 30.563 ;
     RECT  19.968 30.563 20.568 30.851 ;
     RECT  34.8 28.979 35.112 30.853 ;
     RECT  32.688 27.781 32.712 30.901 ;
     RECT  20.064 30.851 20.568 30.947 ;
     RECT  27.888 29.941 27.912 30.947 ;
     RECT  30.768 30.805 31.032 30.947 ;
     RECT  32.688 30.901 33.096 30.947 ;
     RECT  15.984 30.083 16.008 31.237 ;
     RECT  39.792 28.261 40.92 31.429 ;
     RECT  39.072 31.429 40.92 31.619 ;
     RECT  15.984 31.237 16.296 31.765 ;
     RECT  17.712 25.043 18.912 31.765 ;
     RECT  15.984 31.765 18.912 31.955 ;
     RECT  33.072 30.947 33.096 32.149 ;
     RECT  34.8 30.853 35.304 32.341 ;
     RECT  22.32 31.237 22.344 32.531 ;
     RECT  38.304 31.861 38.808 32.675 ;
     RECT  33.024 32.149 33.096 32.723 ;
     RECT  20.544 30.947 20.568 33.013 ;
     RECT  29.4 24.563 29.712 33.013 ;
     RECT  20.544 33.013 21.096 33.059 ;
     RECT  33.072 32.723 33.096 33.397 ;
     RECT  34.224 32.341 35.304 33.397 ;
     RECT  16.272 31.955 18.912 33.539 ;
     RECT  33.072 33.397 35.304 33.587 ;
     RECT  21.072 33.059 21.096 33.827 ;
     RECT  33.552 33.587 35.304 33.829 ;
     RECT  38.304 32.675 38.664 33.925 ;
     RECT  39.792 31.619 40.92 33.925 ;
     RECT  31.248 33.637 31.272 34.163 ;
     RECT  28.512 33.013 29.712 34.499 ;
     RECT  38.304 33.925 40.92 34.501 ;
     RECT  38.064 34.501 40.92 34.787 ;
     RECT  17.136 33.539 18.912 34.835 ;
     RECT  33.552 33.829 35.352 35.125 ;
     RECT  30.768 34.453 30.792 35.507 ;
     RECT  32.448 34.741 32.472 36.275 ;
     RECT  29.4 34.499 29.712 36.325 ;
     RECT  33.552 35.125 36.072 36.515 ;
     RECT  38.304 34.787 40.92 36.515 ;
     RECT  17.136 34.835 17.208 36.563 ;
     RECT  33.552 36.515 35.304 36.613 ;
     RECT  33.456 36.613 35.304 36.661 ;
     RECT  17.136 36.563 17.16 36.755 ;
     RECT  15.696 35.317 15.72 36.851 ;
     RECT  18.6 34.835 18.912 36.997 ;
     RECT  11.376 36.997 11.4 37.093 ;
     RECT  11.28 37.093 11.4 37.477 ;
     RECT  18.6 36.997 19.032 37.573 ;
     RECT  18.192 37.573 19.032 37.619 ;
     RECT  33.12 36.661 35.304 37.859 ;
     RECT  38.304 36.515 40.776 37.955 ;
     RECT  11.04 37.477 11.4 38.195 ;
     RECT  39.072 37.955 40.776 38.243 ;
     RECT  39.072 38.243 40.632 38.291 ;
     RECT  33.12 37.859 33.576 38.339 ;
     RECT  29.232 36.325 29.712 38.437 ;
     RECT  30.816 38.341 30.84 38.437 ;
     RECT  33.12 38.339 33.528 38.627 ;
     RECT  29.232 38.437 30.84 38.677 ;
     RECT  13.2 22.211 13.512 38.725 ;
     RECT  28.656 38.677 30.84 38.819 ;
     RECT  34.656 37.859 35.304 38.819 ;
     RECT  39.936 38.291 40.632 38.819 ;
     RECT  33.12 38.627 33.48 38.821 ;
     RECT  37.392 38.773 37.416 38.965 ;
     RECT  18.192 37.619 18.912 39.011 ;
     RECT  32.496 38.821 33.48 39.011 ;
     RECT  37.392 38.965 37.512 39.107 ;
     RECT  34.656 38.819 35.208 39.203 ;
     RECT  37.392 39.107 37.416 39.203 ;
     RECT  27.312 37.189 27.336 39.251 ;
     RECT  11.28 38.195 11.4 39.395 ;
     RECT  11.376 39.395 11.4 39.589 ;
     RECT  13.2 38.725 14.088 39.589 ;
     RECT  11.376 39.589 11.832 39.637 ;
     RECT  13.104 39.589 14.088 39.637 ;
     RECT  29.088 38.819 30.6 39.683 ;
     RECT  16.368 39.301 16.392 39.877 ;
     RECT  33.408 39.011 33.48 39.923 ;
     RECT  29.4 39.683 30.6 40.405 ;
     RECT  34.8 39.203 35.208 40.451 ;
     RECT  11.376 39.637 14.088 40.453 ;
     RECT  16.368 39.877 17.064 40.453 ;
     RECT  33.456 39.923 33.48 40.643 ;
     RECT  29.4 40.405 30.696 40.981 ;
     RECT  29.4 40.981 31.176 41.029 ;
     RECT  2.4 27.203 2.712 41.049 ;
     RECT  7.8 27.011 8.112 41.049 ;
     RECT  18.6 39.011 18.912 41.049 ;
     RECT  34.8 40.451 35.112 41.049 ;
     RECT  40.2 38.819 40.512 41.049 ;
     RECT  2.4 41.049 2.52 41.063 ;
     RECT  7.8 41.049 7.92 41.063 ;
     RECT  18.6 41.049 18.72 41.063 ;
     RECT  24 26.243 24.312 41.063 ;
     RECT  29.4 41.029 31.272 41.063 ;
     RECT  34.8 41.049 34.92 41.063 ;
     RECT  40.2 41.049 40.32 41.063 ;
     RECT  33.168 41.029 33.192 41.269 ;
     RECT  32.592 41.269 33.192 41.317 ;
     RECT  30.48 41.063 31.272 41.461 ;
     RECT  32.496 41.317 33.192 41.461 ;
     RECT  24.24 41.063 24.312 41.557 ;
     RECT  25.392 41.029 25.416 41.557 ;
     RECT  26.928 40.693 26.952 41.557 ;
     RECT  24.24 41.557 26.952 41.605 ;
     RECT  24.24 41.605 27.048 42.133 ;
     RECT  11.184 40.453 17.064 42.181 ;
     RECT  30.48 41.461 33.192 42.181 ;
     RECT  11.088 42.181 17.064 43.045 ;
     RECT  30.288 42.181 33.192 43.045 ;
     RECT  10.992 43.045 17.064 43.116 ;
     RECT  11.016 43.116 11.088 43.152 ;
     RECT  11.112 43.116 11.184 43.152 ;
     RECT  11.208 43.116 11.28 43.152 ;
     RECT  11.304 43.116 11.376 43.152 ;
     RECT  11.4 43.116 11.472 43.152 ;
     RECT  11.496 43.116 11.568 43.152 ;
     RECT  11.592 43.116 11.664 43.152 ;
     RECT  11.688 43.116 11.76 43.152 ;
     RECT  11.784 43.116 11.856 43.152 ;
     RECT  11.88 43.116 11.952 43.152 ;
     RECT  11.976 43.116 12.048 43.152 ;
     RECT  12.072 43.116 12.144 43.152 ;
     RECT  12.168 43.116 12.24 43.152 ;
     RECT  12.264 43.116 12.336 43.152 ;
     RECT  12.36 43.116 12.432 43.152 ;
     RECT  12.456 43.116 12.528 43.152 ;
     RECT  12.552 43.116 12.624 43.152 ;
     RECT  12.648 43.116 12.72 43.152 ;
     RECT  12.744 43.116 12.816 43.152 ;
     RECT  12.84 43.116 12.912 43.152 ;
     RECT  12.936 43.116 13.008 43.152 ;
     RECT  13.032 43.116 13.104 43.152 ;
     RECT  13.128 43.116 13.2 43.152 ;
     RECT  13.224 43.116 13.296 43.152 ;
     RECT  13.32 43.116 13.392 43.152 ;
     RECT  13.416 43.116 13.488 43.152 ;
     RECT  13.512 43.116 13.584 43.152 ;
     RECT  13.608 43.116 13.68 43.152 ;
     RECT  13.704 43.116 13.776 43.152 ;
     RECT  13.8 43.116 13.872 43.152 ;
     RECT  13.896 43.116 13.968 43.152 ;
     RECT  13.992 43.116 14.448 43.152 ;
     RECT  14.472 43.116 14.544 43.152 ;
     RECT  14.568 43.116 14.64 43.152 ;
     RECT  14.664 43.116 14.736 43.152 ;
     RECT  14.76 43.116 14.832 43.152 ;
     RECT  14.856 43.116 14.928 43.152 ;
     RECT  14.952 43.116 15.024 43.152 ;
     RECT  15.048 43.116 15.12 43.152 ;
     RECT  15.144 43.116 15.216 43.152 ;
     RECT  15.24 43.116 15.312 43.152 ;
     RECT  15.336 43.116 15.408 43.152 ;
     RECT  15.432 43.116 15.504 43.152 ;
     RECT  15.528 43.116 15.6 43.152 ;
     RECT  15.624 43.116 15.696 43.152 ;
     RECT  15.72 43.116 15.792 43.152 ;
     RECT  15.816 43.116 15.888 43.152 ;
     RECT  15.912 43.116 15.984 43.152 ;
     RECT  16.008 43.116 16.08 43.152 ;
     RECT  16.104 43.116 16.176 43.152 ;
     RECT  16.2 43.116 16.272 43.152 ;
     RECT  16.296 43.116 16.368 43.152 ;
     RECT  16.392 43.116 16.464 43.152 ;
     RECT  16.488 43.116 16.56 43.152 ;
     RECT  16.584 43.116 16.656 43.152 ;
     RECT  16.68 43.116 16.752 43.152 ;
     RECT  16.776 43.116 16.848 43.152 ;
     RECT  16.872 43.116 16.944 43.152 ;
     RECT  16.968 43.116 17.04 43.152 ;
     RECT  24.048 42.133 27.048 43.116 ;
     RECT  24.072 43.116 24.144 43.152 ;
     RECT  24.168 43.116 24.24 43.152 ;
     RECT  24.264 43.116 24.336 43.152 ;
     RECT  24.36 43.116 24.432 43.152 ;
     RECT  24.456 43.116 24.528 43.152 ;
     RECT  24.552 43.116 24.624 43.152 ;
     RECT  24.648 43.116 24.72 43.152 ;
     RECT  24.744 43.116 24.816 43.152 ;
     RECT  24.84 43.116 24.912 43.152 ;
     RECT  24.936 43.116 25.008 43.152 ;
     RECT  25.032 43.116 25.104 43.152 ;
     RECT  25.128 43.116 25.2 43.152 ;
     RECT  25.224 43.116 25.296 43.152 ;
     RECT  25.32 43.116 25.392 43.152 ;
     RECT  25.416 43.116 25.488 43.152 ;
     RECT  25.512 43.116 25.584 43.152 ;
     RECT  25.608 43.116 25.68 43.152 ;
     RECT  25.704 43.116 25.776 43.152 ;
     RECT  25.8 43.116 25.872 43.152 ;
     RECT  25.896 43.116 25.968 43.152 ;
     RECT  25.992 43.116 26.064 43.152 ;
     RECT  26.088 43.116 26.16 43.152 ;
     RECT  26.184 43.116 26.256 43.152 ;
     RECT  26.28 43.116 26.352 43.152 ;
     RECT  26.376 43.116 26.448 43.152 ;
     RECT  26.472 43.116 26.544 43.152 ;
     RECT  26.568 43.116 26.64 43.152 ;
     RECT  26.664 43.116 26.736 43.152 ;
     RECT  26.76 43.116 26.832 43.152 ;
     RECT  26.856 43.116 26.928 43.152 ;
     RECT  26.952 43.116 27.024 43.152 ;
     RECT  30.192 43.045 33.192 43.116 ;
     RECT  30.216 43.116 30.288 43.152 ;
     RECT  30.312 43.116 30.384 43.152 ;
     RECT  30.408 43.116 30.48 43.152 ;
     RECT  30.504 43.116 30.576 43.152 ;
     RECT  30.6 43.116 30.672 43.152 ;
     RECT  30.696 43.116 30.768 43.152 ;
     RECT  30.792 43.116 30.864 43.152 ;
     RECT  30.888 43.116 30.96 43.152 ;
     RECT  30.984 43.116 31.056 43.152 ;
     RECT  31.08 43.116 31.152 43.152 ;
     RECT  31.176 43.116 31.248 43.152 ;
     RECT  31.272 43.116 31.344 43.152 ;
     RECT  31.368 43.116 31.44 43.152 ;
     RECT  31.464 43.116 31.536 43.152 ;
     RECT  31.56 43.116 31.632 43.152 ;
     RECT  31.656 43.116 31.728 43.152 ;
     RECT  31.752 43.116 31.824 43.152 ;
     RECT  31.848 43.116 31.92 43.152 ;
     RECT  31.944 43.116 32.016 43.152 ;
     RECT  32.04 43.116 32.112 43.152 ;
     RECT  32.136 43.116 32.208 43.152 ;
     RECT  32.232 43.116 32.304 43.152 ;
     RECT  32.328 43.116 32.4 43.152 ;
     RECT  32.424 43.116 32.496 43.152 ;
     RECT  32.52 43.116 32.592 43.152 ;
     RECT  32.616 43.116 32.688 43.152 ;
     RECT  32.712 43.116 32.784 43.152 ;
     RECT  32.808 43.116 32.88 43.152 ;
     RECT  32.904 43.116 32.976 43.152 ;
     RECT  33 43.116 33.072 43.152 ;
     RECT  33.096 43.116 33.168 43.152 ;
     RECT  13.2 0.611 13.392 2.137 ;
     RECT  14.088 1.907 15.216 1.955 ;
     RECT  15.576 1.907 16.392 2.197 ;
     RECT  13.656 1.955 15.216 3.397 ;
     RECT  22.92 2.137 24 2.339 ;
     RECT  15.576 2.197 16.608 4.595 ;
     RECT  17.016 2.197 18 3.443 ;
     RECT  22.824 2.339 24 2.579 ;
     RECT  11.688 2.821 13.2 6.373 ;
     RECT  14.232 3.397 15.216 3.875 ;
     RECT  16.968 3.443 18 4.019 ;
     RECT  14.232 3.875 15.264 4.643 ;
     RECT  0.144 3.923 0.168 5.221 ;
     RECT  16.968 4.019 18.6 4.837 ;
     RECT  15.576 4.595 16.944 5.171 ;
     RECT  14.232 4.643 15.312 5.795 ;
     RECT  4.536 4.837 5.52 5.267 ;
     RECT  17.4 4.837 18.6 7.141 ;
     RECT  6.216 4.933 7.392 5.269 ;
     RECT  15.336 5.171 16.944 6.229 ;
     RECT  5.424 5.267 5.52 6.661 ;
     RECT  6.216 5.269 7.248 8.677 ;
     RECT  0.144 5.411 0.168 5.509 ;
     RECT  0.144 5.509 0.288 5.651 ;
     RECT  0.144 5.651 0.168 6.565 ;
     RECT  13.656 5.795 15.312 6.899 ;
     RECT  15.72 6.229 16.944 15.637 ;
     RECT  11.688 6.373 13.104 6.709 ;
     RECT  11.688 6.709 13.008 7.621 ;
     RECT  13.656 6.899 15.456 7.189 ;
     RECT  14.376 7.189 15.456 7.475 ;
     RECT  14.376 7.475 15.696 10.739 ;
     RECT  11.976 7.621 13.008 8.149 ;
     RECT  4.296 8.341 5.424 13.139 ;
     RECT  0.144 8.387 0.168 9.397 ;
     RECT  8.112 8.819 9.12 11.317 ;
     RECT  16.968 9.731 18.192 11.941 ;
     RECT  13.848 10.739 15.696 11.509 ;
     RECT  6.216 11.411 7.2 15.301 ;
     RECT  13.848 11.509 15.36 11.941 ;
     RECT  13.992 11.941 15.36 12.229 ;
     RECT  2.808 12.563 3.984 14.675 ;
     RECT  4.008 13.139 5.424 14.101 ;
     RECT  0.144 13.331 0.168 13.573 ;
     RECT  13.992 13.523 15.36 14.243 ;
     RECT  0.144 13.573 0.24 14.629 ;
     RECT  13.992 14.243 15.504 16.019 ;
     RECT  21.312 14.243 21.648 15.349 ;
     RECT  2.808 14.675 4.176 14.773 ;
     RECT  2.856 14.773 4.176 16.501 ;
     RECT  2.304 15.395 2.4 16.885 ;
     RECT  2.952 16.501 4.176 16.981 ;
     RECT  0.264 16.643 0.312 16.885 ;
     RECT  0.264 16.885 1.248 17.123 ;
     RECT  1.272 16.885 2.4 17.123 ;
     RECT  13.752 18.469 14.88 18.899 ;
     RECT  13.656 18.899 14.88 19.427 ;
     RECT  13.656 19.427 14.928 21.251 ;
     RECT  4.536 21.155 5.664 21.347 ;
     RECT  13.512 21.251 14.928 22.211 ;
     RECT  3.72 21.347 5.664 22.165 ;
     RECT  20.088 21.349 21.12 22.499 ;
     RECT  21.144 21.637 22.224 22.021 ;
     RECT  21.24 22.021 22.224 22.931 ;
     RECT  3.72 22.165 4.752 23.411 ;
     RECT  13.104 22.211 13.2 23.317 ;
     RECT  20.088 22.499 21.216 22.931 ;
     RECT  20.088 22.931 22.224 23.317 ;
     RECT  12.072 23.317 13.2 24.947 ;
     RECT  20.088 23.317 21.264 24.563 ;
     RECT  2.712 23.411 4.752 24.325 ;
     RECT  16.2 23.459 17.712 27.683 ;
     RECT  2.712 24.325 4.224 24.757 ;
     RECT  30.264 24.517 31.248 24.563 ;
     RECT  20.088 24.563 20.376 24.613 ;
     RECT  2.856 24.757 4.224 26.291 ;
     RECT  18.912 25.043 20.064 30.181 ;
     RECT  6.168 26.243 7.392 27.011 ;
     RECT  24.312 26.243 25.44 26.819 ;
     RECT  20.472 26.725 21.984 27.635 ;
     RECT  20.472 27.635 20.616 27.875 ;
     RECT  16.56 27.683 17.712 27.877 ;
     RECT  20.376 27.875 20.616 29.077 ;
     RECT  16.584 27.877 17.712 30.083 ;
     RECT  22.92 28.453 24 29.699 ;
     RECT  27.912 29.941 29.4 30.947 ;
     RECT  16.008 30.083 17.712 31.237 ;
     RECT  18.912 30.181 19.968 30.851 ;
     RECT  29.712 30.805 30.768 30.947 ;
     RECT  18.912 30.851 20.064 30.947 ;
     RECT  33.024 30.947 33.072 32.149 ;
     RECT  16.296 31.237 17.712 31.765 ;
     RECT  39.072 31.619 39.792 31.861 ;
     RECT  38.808 31.861 39.792 32.675 ;
     RECT  33.096 32.341 34.224 33.397 ;
     RECT  38.664 32.675 39.792 33.925 ;
     RECT  33.072 33.587 33.552 34.741 ;
     RECT  29.712 34.453 30.768 35.507 ;
     RECT  32.472 34.741 33.552 36.275 ;
     RECT  17.208 34.835 18.6 36.563 ;
     RECT  15.72 35.317 17.136 36.755 ;
     RECT  33.12 36.275 33.552 36.613 ;
     RECT  17.16 36.563 18.6 36.755 ;
     RECT  33.12 36.613 33.456 36.661 ;
     RECT  18.192 36.755 18.6 37.573 ;
     RECT  33.576 37.859 34.656 38.339 ;
     RECT  33.528 38.339 34.656 38.627 ;
     RECT  29.712 38.341 30.816 38.437 ;
     RECT  33.48 38.627 34.656 39.203 ;
     RECT  27.336 38.677 28.656 38.819 ;
     RECT  33.48 39.203 34.8 40.643 ;
     RECT  11.28 39.395 11.376 40.453 ;
     RECT  11.832 39.589 13.104 39.637 ;
     RECT  24.312 41.029 25.392 41.557 ;
     RECT  25.416 41.029 26.928 41.557 ;
     RECT  24.048 41.063 24.24 42.133 ;
     RECT  30.288 41.063 30.48 42.181 ;
     RECT  31.272 41.269 32.592 41.317 ;
     RECT  31.272 41.317 32.496 41.461 ;
  END
END ot_qwen_tp8_pv_wide_ctl_t
END LIBRARY
